VERSION 5.7 ;
  NOWIREEXTENSIONATPIN ON ;
  DIVIDERCHAR "/" ;
  BUSBITCHARS "[]" ;
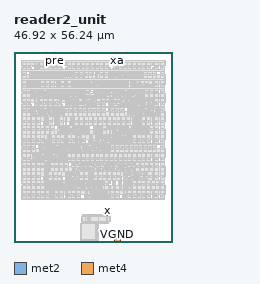
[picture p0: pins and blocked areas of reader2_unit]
MACRO reader2_unit
  CLASS BLOCK ;
  FOREIGN reader2_unit ;
  ORIGIN 0.000 0.000 ;
  SIZE 46.920 BY 56.240 ;
  PIN x
    DIRECTION INPUT ;
    USE SIGNAL ;
    ANTENNAGATEAREA 17.447500 ;
    ANTENNADIFFAREA 0.700000 ;
    PORT
      LAYER met2 ;
        RECT 27.690 9.000 27.970 9.400 ;
    END
  END x
  PIN VPWR
    DIRECTION INOUT ;
    USE POWER ;
    PORT
      LAYER met4 ;
        RECT 26.500 7.715 27.550 8.715 ;
    END
  END VPWR
  PIN VGND
    DIRECTION INOUT ;
    USE GROUND ;
    PORT
      LAYER met4 ;
        RECT 29.800 0.135 31.400 1.135 ;
    END
  END VGND
  PIN en
    DIRECTION INPUT ;
    USE SIGNAL ;
    ANTENNAGATEAREA 0.247500 ;
    PORT
      LAYER met2 ;
        RECT 9.290 55.960 9.570 56.240 ;
    END
  END en
  PIN pre
    DIRECTION INPUT ;
    USE SIGNAL ;
    ANTENNAGATEAREA 0.495000 ;
    PORT
      LAYER met2 ;
        RECT 12.050 55.960 12.330 56.240 ;
    END
  END pre
  PIN src[0]
    DIRECTION INPUT ;
    USE SIGNAL ;
    ANTENNAGATEAREA 1.615500 ;
    PORT
      LAYER met2 ;
        RECT 14.810 55.960 15.090 56.240 ;
    END
  END src[0]
  PIN src[1]
    DIRECTION INPUT ;
    USE SIGNAL ;
    ANTENNAGATEAREA 1.984500 ;
    PORT
      LAYER met2 ;
        RECT 17.570 55.960 17.850 56.240 ;
    END
  END src[1]
  PIN xa
    DIRECTION OUTPUT ;
    USE SIGNAL ;
    ANTENNADIFFAREA 0.445500 ;
    PORT
      LAYER met2 ;
        RECT 30.450 55.960 30.730 56.240 ;
    END
  END xa
  PIN xb
    DIRECTION OUTPUT ;
    USE SIGNAL ;
    ANTENNADIFFAREA 0.445500 ;
    PORT
      LAYER met2 ;
        RECT 33.210 55.960 33.490 56.240 ;
    END
  END xb
  OBS
      LAYER nwell ;
        RECT 2.110 52.105 44.810 53.710 ;
      LAYER pwell ;
        RECT 2.305 50.905 3.675 51.715 ;
        RECT 3.685 50.905 5.055 51.715 ;
        RECT 5.995 50.905 7.345 51.815 ;
        RECT 7.365 50.905 8.735 51.715 ;
        RECT 8.745 50.905 10.115 51.715 ;
        RECT 10.125 50.905 11.495 51.715 ;
        RECT 11.505 50.905 12.875 51.715 ;
        RECT 12.885 50.905 14.255 51.715 ;
        RECT 15.195 50.990 15.625 51.775 ;
        RECT 15.645 50.905 17.015 51.715 ;
        RECT 17.025 50.905 18.395 51.715 ;
        RECT 18.405 50.905 19.775 51.715 ;
        RECT 19.785 50.905 21.155 51.715 ;
        RECT 21.165 50.905 22.535 51.715 ;
        RECT 22.545 50.905 23.915 51.715 ;
        RECT 23.925 50.905 25.295 51.715 ;
        RECT 25.305 50.905 26.675 51.715 ;
        RECT 26.685 50.905 28.055 51.715 ;
        RECT 28.075 50.990 28.505 51.775 ;
        RECT 30.825 50.905 32.195 51.715 ;
        RECT 32.205 50.905 33.575 51.715 ;
        RECT 33.585 50.905 34.955 51.715 ;
        RECT 34.965 50.905 36.335 51.715 ;
        RECT 36.345 50.905 37.715 51.715 ;
        RECT 37.725 50.905 39.095 51.715 ;
        RECT 39.105 50.905 40.475 51.715 ;
        RECT 40.955 50.990 41.385 51.775 ;
        RECT 41.405 50.905 42.775 51.715 ;
        RECT 43.245 50.905 44.615 51.715 ;
        RECT 2.445 50.695 2.615 50.905 ;
        RECT 3.825 50.715 3.995 50.905 ;
        RECT 4.745 50.695 4.915 50.885 ;
        RECT 5.215 50.750 5.375 50.860 ;
        RECT 7.045 50.715 7.215 50.905 ;
        RECT 7.505 50.715 7.675 50.905 ;
        RECT 8.885 50.715 9.055 50.905 ;
        RECT 10.265 50.715 10.435 50.905 ;
        RECT 11.645 50.715 11.815 50.905 ;
        RECT 13.025 50.715 13.195 50.905 ;
        RECT 14.410 50.695 14.580 50.885 ;
        RECT 15.785 50.715 15.955 50.905 ;
        RECT 17.165 50.715 17.335 50.905 ;
        RECT 18.085 50.695 18.255 50.885 ;
        RECT 18.545 50.715 18.715 50.905 ;
        RECT 19.465 50.695 19.635 50.885 ;
        RECT 19.925 50.715 20.095 50.905 ;
        RECT 20.845 50.695 21.015 50.885 ;
        RECT 21.305 50.715 21.475 50.905 ;
        RECT 22.225 50.695 22.395 50.885 ;
        RECT 22.685 50.715 22.855 50.905 ;
        RECT 23.600 50.745 23.720 50.855 ;
        RECT 24.065 50.715 24.235 50.905 ;
        RECT 25.445 50.695 25.615 50.905 ;
        RECT 26.825 50.695 26.995 50.905 ;
        RECT 28.665 50.695 28.835 50.885 ;
        RECT 29.585 50.715 29.755 50.885 ;
        RECT 30.965 50.715 31.135 50.905 ;
        RECT 32.345 50.715 32.515 50.905 ;
        RECT 33.725 50.715 33.895 50.905 ;
        RECT 35.105 50.715 35.275 50.905 ;
        RECT 36.485 50.715 36.655 50.905 ;
        RECT 37.865 50.715 38.035 50.905 ;
        RECT 38.325 50.695 38.495 50.885 ;
        RECT 39.245 50.715 39.415 50.905 ;
        RECT 39.705 50.695 39.875 50.885 ;
        RECT 40.620 50.745 40.740 50.855 ;
        RECT 41.085 50.695 41.255 50.885 ;
        RECT 41.545 50.715 41.715 50.905 ;
        RECT 42.475 50.740 42.635 50.850 ;
        RECT 42.920 50.745 43.040 50.855 ;
        RECT 44.305 50.695 44.475 50.905 ;
        RECT 2.305 49.885 3.675 50.695 ;
        RECT 4.605 50.015 14.215 50.695 ;
        RECT 9.115 49.795 10.045 50.015 ;
        RECT 12.875 49.785 14.215 50.015 ;
        RECT 14.265 49.785 17.920 50.695 ;
        RECT 17.945 49.885 19.315 50.695 ;
        RECT 19.325 49.885 20.695 50.695 ;
        RECT 20.705 49.885 22.075 50.695 ;
        RECT 22.085 49.885 23.455 50.695 ;
        RECT 25.305 49.885 26.675 50.695 ;
        RECT 26.685 49.885 28.055 50.695 ;
        RECT 28.075 49.825 28.505 50.610 ;
        RECT 28.525 50.015 38.135 50.695 ;
        RECT 33.035 49.795 33.965 50.015 ;
        RECT 36.795 49.785 38.135 50.015 ;
        RECT 38.185 49.885 39.555 50.695 ;
        RECT 39.565 49.885 40.935 50.695 ;
        RECT 40.945 49.885 42.315 50.695 ;
        RECT 43.245 49.885 44.615 50.695 ;
      LAYER nwell ;
        RECT 2.110 46.665 44.810 49.495 ;
      LAYER pwell ;
        RECT 2.305 45.465 3.675 46.275 ;
        RECT 3.695 45.465 5.045 46.375 ;
        RECT 5.075 45.465 6.425 46.375 ;
        RECT 6.455 45.465 7.805 46.375 ;
        RECT 7.825 45.465 9.195 46.275 ;
        RECT 9.205 45.465 10.575 46.275 ;
        RECT 10.585 45.465 11.955 46.275 ;
        RECT 12.435 45.465 13.785 46.375 ;
        RECT 13.805 45.465 15.175 46.275 ;
        RECT 15.195 45.550 15.625 46.335 ;
        RECT 15.645 45.465 17.015 46.275 ;
        RECT 17.025 45.465 22.845 46.375 ;
        RECT 27.515 46.145 28.445 46.365 ;
        RECT 31.275 46.145 32.615 46.375 ;
        RECT 23.005 45.465 32.615 46.145 ;
        RECT 32.675 45.465 34.025 46.375 ;
        RECT 34.515 45.465 35.865 46.375 ;
        RECT 35.895 45.465 37.245 46.375 ;
        RECT 37.265 45.465 38.635 46.275 ;
        RECT 38.645 45.465 40.015 46.275 ;
        RECT 40.955 45.550 41.385 46.335 ;
        RECT 41.405 45.465 42.775 46.275 ;
        RECT 43.245 45.465 44.615 46.275 ;
        RECT 2.445 45.255 2.615 45.465 ;
        RECT 3.825 45.255 3.995 45.445 ;
        RECT 4.745 45.275 4.915 45.465 ;
        RECT 5.205 45.255 5.375 45.445 ;
        RECT 6.125 45.275 6.295 45.465 ;
        RECT 7.505 45.275 7.675 45.465 ;
        RECT 7.965 45.275 8.135 45.465 ;
        RECT 9.345 45.275 9.515 45.465 ;
        RECT 10.725 45.275 10.895 45.465 ;
        RECT 12.100 45.305 12.220 45.415 ;
        RECT 12.565 45.275 12.735 45.465 ;
        RECT 13.945 45.275 14.115 45.465 ;
        RECT 15.785 45.275 15.955 45.465 ;
        RECT 17.165 45.275 17.335 45.465 ;
        RECT 17.625 45.255 17.795 45.445 ;
        RECT 18.090 45.255 18.260 45.445 ;
        RECT 21.305 45.255 21.475 45.445 ;
        RECT 22.695 45.300 22.855 45.410 ;
        RECT 23.145 45.275 23.315 45.465 ;
        RECT 23.580 45.255 23.750 45.445 ;
        RECT 27.740 45.305 27.860 45.415 ;
        RECT 28.660 45.305 28.780 45.415 ;
        RECT 29.125 45.255 29.295 45.445 ;
        RECT 33.725 45.275 33.895 45.465 ;
        RECT 34.180 45.305 34.300 45.415 ;
        RECT 34.645 45.275 34.815 45.465 ;
        RECT 36.025 45.275 36.195 45.465 ;
        RECT 37.405 45.275 37.575 45.465 ;
        RECT 38.785 45.255 38.955 45.465 ;
        RECT 40.165 45.255 40.335 45.445 ;
        RECT 41.545 45.255 41.715 45.465 ;
        RECT 42.920 45.305 43.040 45.415 ;
        RECT 44.305 45.255 44.475 45.465 ;
        RECT 2.305 44.445 3.675 45.255 ;
        RECT 3.685 44.445 5.055 45.255 ;
        RECT 5.065 44.575 14.675 45.255 ;
        RECT 16.095 45.225 17.935 45.255 ;
        RECT 9.575 44.355 10.505 44.575 ;
        RECT 13.335 44.345 14.675 44.575 ;
        RECT 14.770 44.575 17.935 45.225 ;
        RECT 18.090 45.025 21.145 45.255 ;
        RECT 14.770 44.545 17.450 44.575 ;
        RECT 16.095 44.345 17.450 44.545 ;
        RECT 17.945 44.345 21.145 45.025 ;
        RECT 21.165 44.445 22.535 45.255 ;
        RECT 23.520 44.345 27.595 45.255 ;
        RECT 28.075 44.385 28.505 45.170 ;
        RECT 28.985 44.575 38.595 45.255 ;
        RECT 33.495 44.355 34.425 44.575 ;
        RECT 37.255 44.345 38.595 44.575 ;
        RECT 38.645 44.445 40.015 45.255 ;
        RECT 40.025 44.445 41.395 45.255 ;
        RECT 41.405 44.445 42.775 45.255 ;
        RECT 43.245 44.445 44.615 45.255 ;
      LAYER nwell ;
        RECT 2.110 41.225 44.810 44.055 ;
      LAYER pwell ;
        RECT 2.305 40.025 3.675 40.835 ;
        RECT 3.685 40.025 5.055 40.835 ;
        RECT 5.995 40.025 7.345 40.935 ;
        RECT 7.365 40.025 8.735 40.835 ;
        RECT 8.745 40.025 10.115 40.835 ;
        RECT 10.125 40.025 11.495 40.835 ;
        RECT 11.505 40.025 12.875 40.835 ;
        RECT 12.885 40.025 14.255 40.835 ;
        RECT 15.195 40.110 15.625 40.895 ;
        RECT 17.015 40.735 18.370 40.935 ;
        RECT 15.690 40.705 18.370 40.735 ;
        RECT 15.690 40.055 18.855 40.705 ;
        RECT 17.015 40.025 18.855 40.055 ;
        RECT 18.865 40.025 20.235 40.835 ;
        RECT 20.300 40.025 24.375 40.935 ;
        RECT 24.385 40.025 25.755 40.835 ;
        RECT 25.765 40.025 27.135 40.835 ;
        RECT 28.075 40.025 29.425 40.935 ;
        RECT 29.445 40.025 30.815 40.835 ;
        RECT 31.325 40.705 32.665 40.935 ;
        RECT 35.495 40.705 36.425 40.925 ;
        RECT 31.325 40.025 40.935 40.705 ;
        RECT 40.955 40.110 41.385 40.895 ;
        RECT 41.405 40.025 42.775 40.835 ;
        RECT 43.245 40.025 44.615 40.835 ;
        RECT 2.445 39.815 2.615 40.025 ;
        RECT 3.825 39.815 3.995 40.025 ;
        RECT 5.205 39.815 5.375 40.005 ;
        RECT 7.045 39.835 7.215 40.025 ;
        RECT 7.505 39.835 7.675 40.025 ;
        RECT 8.885 39.835 9.055 40.025 ;
        RECT 10.265 39.835 10.435 40.025 ;
        RECT 11.645 39.835 11.815 40.025 ;
        RECT 13.025 39.835 13.195 40.025 ;
        RECT 14.415 39.870 14.575 39.980 ;
        RECT 14.865 39.815 15.035 40.005 ;
        RECT 16.245 39.815 16.415 40.005 ;
        RECT 17.625 39.815 17.795 40.005 ;
        RECT 18.545 39.835 18.715 40.025 ;
        RECT 19.005 39.815 19.175 40.025 ;
        RECT 20.360 40.005 20.530 40.025 ;
        RECT 20.360 39.835 20.555 40.005 ;
        RECT 20.385 39.815 20.555 39.835 ;
        RECT 21.765 39.815 21.935 40.005 ;
        RECT 23.145 39.815 23.315 40.005 ;
        RECT 24.525 39.815 24.695 40.025 ;
        RECT 25.905 39.815 26.075 40.025 ;
        RECT 27.295 39.860 27.455 39.980 ;
        RECT 28.205 39.835 28.375 40.025 ;
        RECT 28.665 39.815 28.835 40.005 ;
        RECT 29.585 39.835 29.755 40.025 ;
        RECT 30.045 39.815 30.215 40.005 ;
        RECT 30.960 39.865 31.080 39.975 ;
        RECT 31.425 39.815 31.595 40.005 ;
        RECT 32.815 39.860 32.975 39.970 ;
        RECT 40.625 39.835 40.795 40.025 ;
        RECT 41.545 39.835 41.715 40.025 ;
        RECT 42.925 39.975 43.095 40.005 ;
        RECT 42.920 39.865 43.095 39.975 ;
        RECT 42.925 39.815 43.095 39.865 ;
        RECT 44.305 39.815 44.475 40.025 ;
        RECT 2.305 39.005 3.675 39.815 ;
        RECT 3.685 39.005 5.055 39.815 ;
        RECT 5.065 39.135 14.675 39.815 ;
        RECT 9.575 38.915 10.505 39.135 ;
        RECT 13.335 38.905 14.675 39.135 ;
        RECT 14.725 39.005 16.095 39.815 ;
        RECT 16.105 39.005 17.475 39.815 ;
        RECT 17.485 39.005 18.855 39.815 ;
        RECT 18.865 39.005 20.235 39.815 ;
        RECT 20.245 39.005 21.615 39.815 ;
        RECT 21.625 39.005 22.995 39.815 ;
        RECT 23.005 39.005 24.375 39.815 ;
        RECT 24.385 39.005 25.755 39.815 ;
        RECT 25.765 39.005 27.135 39.815 ;
        RECT 28.075 38.945 28.505 39.730 ;
        RECT 28.525 39.005 29.895 39.815 ;
        RECT 29.905 39.005 31.275 39.815 ;
        RECT 31.285 39.005 32.655 39.815 ;
        RECT 33.625 39.135 43.235 39.815 ;
        RECT 33.625 38.905 34.965 39.135 ;
        RECT 37.795 38.915 38.725 39.135 ;
        RECT 43.245 39.005 44.615 39.815 ;
      LAYER nwell ;
        RECT 2.110 35.785 44.810 38.615 ;
      LAYER pwell ;
        RECT 2.305 34.585 3.675 35.395 ;
        RECT 3.685 34.585 5.055 35.395 ;
        RECT 5.065 34.585 6.435 35.395 ;
        RECT 6.445 34.585 7.815 35.395 ;
        RECT 8.755 34.585 10.105 35.495 ;
        RECT 10.125 34.585 11.495 35.395 ;
        RECT 11.975 34.585 13.325 35.495 ;
        RECT 13.345 34.585 14.715 35.395 ;
        RECT 15.195 34.670 15.625 35.455 ;
        RECT 16.575 34.585 17.925 35.495 ;
        RECT 17.945 34.585 19.315 35.395 ;
        RECT 19.325 34.585 20.695 35.395 ;
        RECT 20.705 34.585 22.075 35.395 ;
        RECT 22.085 34.585 23.455 35.395 ;
        RECT 23.465 34.585 24.835 35.395 ;
        RECT 24.845 34.585 26.215 35.395 ;
        RECT 26.225 34.585 27.595 35.395 ;
        RECT 27.605 34.585 28.975 35.395 ;
        RECT 28.985 34.585 30.355 35.395 ;
        RECT 30.365 34.585 31.735 35.395 ;
        RECT 31.745 34.585 33.115 35.395 ;
        RECT 33.125 34.585 34.495 35.395 ;
        RECT 34.975 34.585 36.325 35.495 ;
        RECT 36.355 34.585 37.705 35.495 ;
        RECT 37.725 34.585 39.095 35.395 ;
        RECT 39.105 34.585 40.475 35.395 ;
        RECT 40.955 34.670 41.385 35.455 ;
        RECT 41.405 34.585 42.775 35.395 ;
        RECT 43.245 34.585 44.615 35.395 ;
        RECT 2.445 34.375 2.615 34.585 ;
        RECT 3.825 34.375 3.995 34.585 ;
        RECT 5.205 34.375 5.375 34.585 ;
        RECT 6.585 34.375 6.755 34.585 ;
        RECT 7.965 34.375 8.135 34.565 ;
        RECT 9.345 34.375 9.515 34.565 ;
        RECT 9.805 34.395 9.975 34.585 ;
        RECT 10.265 34.395 10.435 34.585 ;
        RECT 10.725 34.375 10.895 34.565 ;
        RECT 11.640 34.425 11.760 34.535 ;
        RECT 12.105 34.395 12.275 34.585 ;
        RECT 13.025 34.375 13.195 34.565 ;
        RECT 13.485 34.395 13.655 34.585 ;
        RECT 14.860 34.425 14.980 34.535 ;
        RECT 15.795 34.430 15.955 34.540 ;
        RECT 17.625 34.395 17.795 34.585 ;
        RECT 18.085 34.395 18.255 34.585 ;
        RECT 19.465 34.395 19.635 34.585 ;
        RECT 20.845 34.395 21.015 34.585 ;
        RECT 22.225 34.395 22.395 34.585 ;
        RECT 22.695 34.420 22.855 34.530 ;
        RECT 23.605 34.375 23.775 34.585 ;
        RECT 24.985 34.395 25.155 34.585 ;
        RECT 25.905 34.375 26.075 34.565 ;
        RECT 26.365 34.375 26.535 34.585 ;
        RECT 27.745 34.535 27.915 34.585 ;
        RECT 27.740 34.425 27.915 34.535 ;
        RECT 28.660 34.425 28.780 34.535 ;
        RECT 27.745 34.395 27.915 34.425 ;
        RECT 29.125 34.375 29.295 34.585 ;
        RECT 30.505 34.375 30.675 34.585 ;
        RECT 31.885 34.395 32.055 34.585 ;
        RECT 33.265 34.395 33.435 34.585 ;
        RECT 34.640 34.425 34.760 34.535 ;
        RECT 35.105 34.395 35.275 34.585 ;
        RECT 36.485 34.395 36.655 34.585 ;
        RECT 37.865 34.395 38.035 34.585 ;
        RECT 39.245 34.395 39.415 34.585 ;
        RECT 40.165 34.375 40.335 34.565 ;
        RECT 40.620 34.425 40.740 34.535 ;
        RECT 41.545 34.375 41.715 34.585 ;
        RECT 42.920 34.425 43.040 34.535 ;
        RECT 44.305 34.375 44.475 34.585 ;
        RECT 2.305 33.565 3.675 34.375 ;
        RECT 3.685 33.565 5.055 34.375 ;
        RECT 5.065 33.565 6.435 34.375 ;
        RECT 6.445 33.565 7.815 34.375 ;
        RECT 7.825 33.565 9.195 34.375 ;
        RECT 9.205 33.565 10.575 34.375 ;
        RECT 10.585 33.565 11.955 34.375 ;
        RECT 12.885 33.695 22.495 34.375 ;
        RECT 17.395 33.475 18.325 33.695 ;
        RECT 21.155 33.465 22.495 33.695 ;
        RECT 23.475 33.465 24.825 34.375 ;
        RECT 24.855 33.465 26.205 34.375 ;
        RECT 26.225 33.565 27.595 34.375 ;
        RECT 28.075 33.505 28.505 34.290 ;
        RECT 28.995 33.465 30.345 34.375 ;
        RECT 30.365 33.695 39.975 34.375 ;
        RECT 34.875 33.475 35.805 33.695 ;
        RECT 38.635 33.465 39.975 33.695 ;
        RECT 40.025 33.565 41.395 34.375 ;
        RECT 41.405 33.565 42.775 34.375 ;
        RECT 43.245 33.565 44.615 34.375 ;
      LAYER nwell ;
        RECT 2.110 30.345 44.810 33.175 ;
      LAYER pwell ;
        RECT 2.305 29.145 3.675 29.955 ;
        RECT 3.685 29.145 5.055 29.955 ;
        RECT 5.065 29.145 6.435 29.955 ;
        RECT 6.445 29.145 7.815 29.955 ;
        RECT 7.825 29.145 9.195 29.955 ;
        RECT 9.675 29.145 11.025 30.055 ;
        RECT 11.045 29.145 12.415 29.955 ;
        RECT 12.425 29.145 13.795 29.955 ;
        RECT 13.805 29.145 15.175 29.955 ;
        RECT 15.195 29.230 15.625 30.015 ;
        RECT 15.645 29.145 17.015 29.955 ;
        RECT 17.025 29.145 18.395 29.955 ;
        RECT 18.415 29.145 19.765 30.055 ;
        RECT 19.785 29.145 21.155 29.955 ;
        RECT 22.095 29.145 23.445 30.055 ;
        RECT 28.435 29.825 29.365 30.045 ;
        RECT 32.195 29.825 33.535 30.055 ;
        RECT 23.925 29.145 33.535 29.825 ;
        RECT 33.595 29.145 34.945 30.055 ;
        RECT 34.965 29.145 36.335 29.955 ;
        RECT 36.345 29.145 37.715 29.955 ;
        RECT 37.725 29.145 39.095 29.955 ;
        RECT 39.105 29.145 40.475 29.955 ;
        RECT 40.955 29.230 41.385 30.015 ;
        RECT 41.405 29.145 42.775 29.955 ;
        RECT 43.245 29.145 44.615 29.955 ;
        RECT 2.445 28.935 2.615 29.145 ;
        RECT 3.825 28.935 3.995 29.145 ;
        RECT 5.205 28.935 5.375 29.145 ;
        RECT 6.585 28.955 6.755 29.145 ;
        RECT 7.965 28.955 8.135 29.145 ;
        RECT 8.425 28.935 8.595 29.125 ;
        RECT 8.885 28.935 9.055 29.125 ;
        RECT 9.340 28.985 9.460 29.095 ;
        RECT 10.725 28.955 10.895 29.145 ;
        RECT 11.185 28.955 11.355 29.145 ;
        RECT 12.565 28.955 12.735 29.145 ;
        RECT 13.945 28.955 14.115 29.145 ;
        RECT 15.785 28.955 15.955 29.145 ;
        RECT 17.165 28.955 17.335 29.145 ;
        RECT 18.545 28.935 18.715 29.125 ;
        RECT 19.465 28.955 19.635 29.145 ;
        RECT 19.925 28.955 20.095 29.145 ;
        RECT 21.315 28.990 21.475 29.100 ;
        RECT 23.145 28.955 23.315 29.145 ;
        RECT 23.600 28.985 23.720 29.095 ;
        RECT 24.065 28.955 24.235 29.145 ;
        RECT 28.665 28.935 28.835 29.125 ;
        RECT 30.045 28.935 30.215 29.125 ;
        RECT 31.425 28.935 31.595 29.125 ;
        RECT 32.805 28.935 32.975 29.125 ;
        RECT 34.185 28.935 34.355 29.125 ;
        RECT 34.645 28.955 34.815 29.145 ;
        RECT 35.105 28.955 35.275 29.145 ;
        RECT 35.565 28.935 35.735 29.125 ;
        RECT 36.485 28.955 36.655 29.145 ;
        RECT 36.945 28.935 37.115 29.125 ;
        RECT 37.865 28.955 38.035 29.145 ;
        RECT 38.325 28.935 38.495 29.125 ;
        RECT 39.245 28.955 39.415 29.145 ;
        RECT 39.705 28.935 39.875 29.125 ;
        RECT 40.620 28.985 40.740 29.095 ;
        RECT 41.085 28.935 41.255 29.125 ;
        RECT 41.545 28.955 41.715 29.145 ;
        RECT 42.475 28.980 42.635 29.090 ;
        RECT 42.920 28.985 43.040 29.095 ;
        RECT 44.305 28.935 44.475 29.145 ;
        RECT 2.305 28.125 3.675 28.935 ;
        RECT 3.685 28.125 5.055 28.935 ;
        RECT 5.065 28.125 6.435 28.935 ;
        RECT 7.375 28.025 8.725 28.935 ;
        RECT 8.745 28.255 18.355 28.935 ;
        RECT 18.405 28.255 28.015 28.935 ;
        RECT 13.255 28.035 14.185 28.255 ;
        RECT 17.015 28.025 18.355 28.255 ;
        RECT 22.915 28.035 23.845 28.255 ;
        RECT 26.675 28.025 28.015 28.255 ;
        RECT 28.075 28.065 28.505 28.850 ;
        RECT 28.525 28.125 29.895 28.935 ;
        RECT 29.905 28.125 31.275 28.935 ;
        RECT 31.285 28.125 32.655 28.935 ;
        RECT 32.665 28.125 34.035 28.935 ;
        RECT 34.045 28.125 35.415 28.935 ;
        RECT 35.425 28.125 36.795 28.935 ;
        RECT 36.805 28.125 38.175 28.935 ;
        RECT 38.185 28.125 39.555 28.935 ;
        RECT 39.565 28.125 40.935 28.935 ;
        RECT 40.945 28.125 42.315 28.935 ;
        RECT 43.245 28.125 44.615 28.935 ;
      LAYER nwell ;
        RECT 2.110 24.905 44.810 27.735 ;
      LAYER pwell ;
        RECT 2.305 23.705 3.675 24.515 ;
        RECT 3.685 23.705 5.055 24.515 ;
        RECT 10.035 24.385 10.965 24.605 ;
        RECT 13.795 24.385 15.135 24.615 ;
        RECT 5.525 23.705 15.135 24.385 ;
        RECT 15.195 23.790 15.625 24.575 ;
        RECT 15.645 23.705 17.015 24.515 ;
        RECT 17.025 23.705 18.395 24.515 ;
        RECT 18.405 23.705 19.775 24.515 ;
        RECT 19.785 23.705 21.155 24.515 ;
        RECT 21.165 23.705 22.535 24.515 ;
        RECT 22.545 23.705 23.915 24.515 ;
        RECT 23.925 23.705 25.295 24.515 ;
        RECT 25.305 23.705 26.675 24.515 ;
        RECT 26.685 23.705 28.055 24.515 ;
        RECT 28.065 23.705 29.435 24.515 ;
        RECT 29.445 23.705 30.815 24.515 ;
        RECT 30.825 23.705 32.195 24.515 ;
        RECT 32.205 23.705 33.575 24.515 ;
        RECT 33.585 23.705 34.955 24.515 ;
        RECT 34.965 23.705 36.335 24.515 ;
        RECT 36.345 23.705 37.715 24.515 ;
        RECT 37.725 23.705 39.095 24.515 ;
        RECT 39.105 23.705 40.475 24.515 ;
        RECT 40.955 23.790 41.385 24.575 ;
        RECT 41.405 23.705 42.775 24.515 ;
        RECT 43.245 23.705 44.615 24.515 ;
        RECT 2.445 23.495 2.615 23.705 ;
        RECT 3.825 23.495 3.995 23.705 ;
        RECT 5.205 23.655 5.375 23.685 ;
        RECT 5.200 23.545 5.375 23.655 ;
        RECT 5.205 23.495 5.375 23.545 ;
        RECT 5.665 23.515 5.835 23.705 ;
        RECT 6.585 23.495 6.755 23.685 ;
        RECT 7.965 23.495 8.135 23.685 ;
        RECT 10.265 23.495 10.435 23.685 ;
        RECT 10.725 23.495 10.895 23.685 ;
        RECT 12.105 23.495 12.275 23.685 ;
        RECT 13.485 23.495 13.655 23.685 ;
        RECT 14.865 23.495 15.035 23.685 ;
        RECT 15.785 23.515 15.955 23.705 ;
        RECT 16.255 23.540 16.415 23.650 ;
        RECT 17.165 23.495 17.335 23.705 ;
        RECT 18.545 23.515 18.715 23.705 ;
        RECT 19.925 23.515 20.095 23.705 ;
        RECT 20.845 23.495 21.015 23.685 ;
        RECT 21.305 23.515 21.475 23.705 ;
        RECT 22.685 23.515 22.855 23.705 ;
        RECT 24.065 23.515 24.235 23.705 ;
        RECT 24.525 23.495 24.695 23.685 ;
        RECT 25.445 23.515 25.615 23.705 ;
        RECT 26.825 23.515 26.995 23.705 ;
        RECT 28.205 23.515 28.375 23.705 ;
        RECT 28.665 23.495 28.835 23.685 ;
        RECT 29.585 23.515 29.755 23.705 ;
        RECT 30.965 23.515 31.135 23.705 ;
        RECT 32.345 23.515 32.515 23.705 ;
        RECT 33.725 23.515 33.895 23.705 ;
        RECT 35.105 23.515 35.275 23.705 ;
        RECT 35.565 23.495 35.735 23.685 ;
        RECT 36.025 23.495 36.195 23.685 ;
        RECT 36.485 23.515 36.655 23.705 ;
        RECT 37.405 23.495 37.575 23.685 ;
        RECT 37.865 23.515 38.035 23.705 ;
        RECT 38.785 23.495 38.955 23.685 ;
        RECT 39.245 23.515 39.415 23.705 ;
        RECT 40.165 23.495 40.335 23.685 ;
        RECT 40.620 23.545 40.740 23.655 ;
        RECT 41.545 23.495 41.715 23.705 ;
        RECT 42.920 23.545 43.040 23.655 ;
        RECT 44.305 23.495 44.475 23.705 ;
        RECT 2.305 22.685 3.675 23.495 ;
        RECT 3.685 22.685 5.055 23.495 ;
        RECT 5.065 22.685 6.435 23.495 ;
        RECT 6.445 22.685 7.815 23.495 ;
        RECT 7.825 22.685 9.195 23.495 ;
        RECT 9.215 22.585 10.565 23.495 ;
        RECT 10.585 22.685 11.955 23.495 ;
        RECT 11.965 22.685 13.335 23.495 ;
        RECT 13.345 22.685 14.715 23.495 ;
        RECT 14.725 22.685 16.095 23.495 ;
        RECT 17.135 22.815 20.600 23.495 ;
        RECT 20.815 22.815 24.280 23.495 ;
        RECT 24.495 22.815 27.960 23.495 ;
        RECT 19.680 22.585 20.600 22.815 ;
        RECT 23.360 22.585 24.280 22.815 ;
        RECT 27.040 22.585 27.960 22.815 ;
        RECT 28.075 22.625 28.505 23.410 ;
        RECT 28.635 22.815 32.100 23.495 ;
        RECT 31.180 22.585 32.100 22.815 ;
        RECT 32.300 22.815 35.765 23.495 ;
        RECT 32.300 22.585 33.220 22.815 ;
        RECT 35.885 22.685 37.255 23.495 ;
        RECT 37.265 22.685 38.635 23.495 ;
        RECT 38.645 22.685 40.015 23.495 ;
        RECT 40.025 22.685 41.395 23.495 ;
        RECT 41.405 22.685 42.775 23.495 ;
        RECT 43.245 22.685 44.615 23.495 ;
      LAYER nwell ;
        RECT 2.110 19.465 44.810 22.295 ;
      LAYER pwell ;
        RECT 2.305 18.265 3.675 19.075 ;
        RECT 3.685 18.265 5.055 19.075 ;
        RECT 5.065 18.265 6.435 19.075 ;
        RECT 6.445 18.265 7.815 19.075 ;
        RECT 8.755 18.265 10.105 19.175 ;
        RECT 10.125 18.265 11.495 19.075 ;
        RECT 11.505 18.265 12.875 19.075 ;
        RECT 12.885 18.265 14.255 19.075 ;
        RECT 15.195 18.350 15.625 19.135 ;
        RECT 15.740 18.945 16.660 19.175 ;
        RECT 15.740 18.265 19.205 18.945 ;
        RECT 19.325 18.265 20.695 19.075 ;
        RECT 20.705 18.265 22.075 19.075 ;
        RECT 22.095 18.265 23.445 19.175 ;
        RECT 23.465 18.265 24.835 19.075 ;
        RECT 24.845 18.265 26.215 19.075 ;
        RECT 26.225 18.265 27.595 19.075 ;
        RECT 27.605 18.265 28.975 19.075 ;
        RECT 28.985 18.265 30.355 19.075 ;
        RECT 30.365 18.265 31.735 19.075 ;
        RECT 34.860 18.945 35.780 19.175 ;
        RECT 32.315 18.265 35.780 18.945 ;
        RECT 35.980 18.945 36.900 19.175 ;
        RECT 35.980 18.265 39.445 18.945 ;
        RECT 39.565 18.265 40.935 19.075 ;
        RECT 40.955 18.350 41.385 19.135 ;
        RECT 41.405 18.265 42.775 19.075 ;
        RECT 43.245 18.265 44.615 19.075 ;
        RECT 2.445 18.055 2.615 18.265 ;
        RECT 3.825 18.055 3.995 18.265 ;
        RECT 5.205 18.055 5.375 18.265 ;
        RECT 6.585 18.055 6.755 18.265 ;
        RECT 7.965 18.055 8.135 18.245 ;
        RECT 9.805 18.075 9.975 18.265 ;
        RECT 10.265 18.075 10.435 18.265 ;
        RECT 11.645 18.075 11.815 18.265 ;
        RECT 13.025 18.075 13.195 18.265 ;
        RECT 14.415 18.110 14.575 18.220 ;
        RECT 18.545 18.055 18.715 18.245 ;
        RECT 19.005 18.075 19.175 18.265 ;
        RECT 19.465 18.075 19.635 18.265 ;
        RECT 20.845 18.075 21.015 18.265 ;
        RECT 23.145 18.075 23.315 18.265 ;
        RECT 23.605 18.075 23.775 18.265 ;
        RECT 24.985 18.245 25.155 18.265 ;
        RECT 24.980 18.075 25.155 18.245 ;
        RECT 26.365 18.075 26.535 18.265 ;
        RECT 24.980 18.055 25.150 18.075 ;
        RECT 26.365 18.055 26.470 18.075 ;
        RECT 26.825 18.055 26.995 18.245 ;
        RECT 27.745 18.075 27.915 18.265 ;
        RECT 28.660 18.105 28.780 18.215 ;
        RECT 29.125 18.075 29.295 18.265 ;
        RECT 30.505 18.215 30.675 18.265 ;
        RECT 30.500 18.105 30.675 18.215 ;
        RECT 30.505 18.075 30.675 18.105 ;
        RECT 30.965 18.075 31.135 18.245 ;
        RECT 31.880 18.105 32.000 18.215 ;
        RECT 32.345 18.075 32.515 18.265 ;
        RECT 29.190 18.055 29.295 18.075 ;
        RECT 31.030 18.055 31.135 18.075 ;
        RECT 32.410 18.055 32.515 18.075 ;
        RECT 33.730 18.055 33.900 18.245 ;
        RECT 35.105 18.055 35.275 18.245 ;
        RECT 36.485 18.055 36.655 18.245 ;
        RECT 37.865 18.055 38.035 18.245 ;
        RECT 39.245 18.055 39.415 18.265 ;
        RECT 39.705 18.075 39.875 18.265 ;
        RECT 40.625 18.055 40.795 18.245 ;
        RECT 41.545 18.075 41.715 18.265 ;
        RECT 42.005 18.055 42.175 18.245 ;
        RECT 42.920 18.105 43.040 18.215 ;
        RECT 44.305 18.055 44.475 18.265 ;
        RECT 2.305 17.245 3.675 18.055 ;
        RECT 3.685 17.245 5.055 18.055 ;
        RECT 5.065 17.245 6.435 18.055 ;
        RECT 6.445 17.245 7.815 18.055 ;
        RECT 7.825 17.245 9.195 18.055 ;
        RECT 9.245 17.375 18.855 18.055 ;
        RECT 9.245 17.145 10.585 17.375 ;
        RECT 13.415 17.155 14.345 17.375 ;
        RECT 19.215 17.145 25.295 18.055 ;
        RECT 25.540 17.145 26.470 18.055 ;
        RECT 26.685 17.245 28.055 18.055 ;
        RECT 28.075 17.185 28.505 17.970 ;
        RECT 29.190 17.145 30.120 18.055 ;
        RECT 31.030 17.145 31.960 18.055 ;
        RECT 32.410 17.145 33.340 18.055 ;
        RECT 33.585 17.145 34.935 18.055 ;
        RECT 34.965 17.245 36.335 18.055 ;
        RECT 36.345 17.245 37.715 18.055 ;
        RECT 37.725 17.245 39.095 18.055 ;
        RECT 39.105 17.245 40.475 18.055 ;
        RECT 40.485 17.245 41.855 18.055 ;
        RECT 41.865 17.245 43.235 18.055 ;
        RECT 43.245 17.245 44.615 18.055 ;
      LAYER nwell ;
        RECT 2.110 14.025 44.810 16.855 ;
      LAYER pwell ;
        RECT 2.305 12.825 3.675 13.635 ;
        RECT 3.685 12.825 5.055 13.635 ;
        RECT 5.065 12.825 6.435 13.635 ;
        RECT 6.445 12.825 7.815 13.635 ;
        RECT 7.825 12.825 9.195 13.635 ;
        RECT 9.205 12.825 10.575 13.635 ;
        RECT 10.595 12.825 11.945 13.735 ;
        RECT 11.965 12.825 13.335 13.635 ;
        RECT 13.345 12.825 14.715 13.635 ;
        RECT 15.195 12.910 15.625 13.695 ;
        RECT 15.645 12.825 17.015 13.635 ;
        RECT 17.025 12.825 18.395 13.635 ;
        RECT 18.405 12.825 19.775 13.635 ;
        RECT 20.910 12.825 21.840 13.735 ;
        RECT 22.085 12.825 27.795 13.735 ;
        RECT 28.075 12.910 28.505 13.695 ;
        RECT 28.525 12.825 29.895 13.635 ;
        RECT 29.905 12.825 31.275 13.635 ;
        RECT 32.205 12.825 33.555 13.735 ;
        RECT 33.585 12.825 34.955 13.635 ;
        RECT 34.965 12.825 36.335 13.635 ;
        RECT 36.345 12.825 37.715 13.635 ;
        RECT 37.725 12.825 39.095 13.635 ;
        RECT 39.105 12.825 40.475 13.635 ;
        RECT 40.955 12.910 41.385 13.695 ;
        RECT 41.405 12.825 42.775 13.635 ;
        RECT 43.245 12.825 44.615 13.635 ;
        RECT 2.445 12.635 2.615 12.825 ;
        RECT 3.825 12.635 3.995 12.825 ;
        RECT 5.205 12.635 5.375 12.825 ;
        RECT 6.585 12.635 6.755 12.825 ;
        RECT 7.965 12.635 8.135 12.825 ;
        RECT 9.345 12.635 9.515 12.825 ;
        RECT 10.725 12.635 10.895 12.825 ;
        RECT 12.105 12.635 12.275 12.825 ;
        RECT 13.485 12.635 13.655 12.825 ;
        RECT 14.860 12.665 14.980 12.775 ;
        RECT 15.785 12.635 15.955 12.825 ;
        RECT 17.165 12.635 17.335 12.825 ;
        RECT 18.545 12.635 18.715 12.825 ;
        RECT 20.910 12.805 21.015 12.825 ;
        RECT 19.935 12.670 20.095 12.780 ;
        RECT 20.845 12.635 21.015 12.805 ;
        RECT 22.230 12.635 22.400 12.825 ;
        RECT 28.665 12.635 28.835 12.825 ;
        RECT 30.045 12.635 30.215 12.825 ;
        RECT 31.435 12.670 31.595 12.780 ;
        RECT 32.350 12.635 32.520 12.825 ;
        RECT 33.725 12.635 33.895 12.825 ;
        RECT 35.105 12.635 35.275 12.825 ;
        RECT 36.485 12.635 36.655 12.825 ;
        RECT 37.865 12.635 38.035 12.825 ;
        RECT 39.245 12.635 39.415 12.825 ;
        RECT 40.620 12.665 40.740 12.775 ;
        RECT 41.545 12.635 41.715 12.825 ;
        RECT 42.920 12.665 43.040 12.775 ;
        RECT 44.305 12.635 44.475 12.825 ;
      LAYER nwell ;
        RECT 19.940 6.100 28.600 7.460 ;
      LAYER pwell ;
        RECT 19.590 0.870 25.140 5.430 ;
      LAYER li1 ;
        RECT 2.300 53.435 44.620 53.605 ;
        RECT 2.385 52.345 3.595 53.435 ;
        RECT 3.765 52.345 4.975 53.435 ;
        RECT 2.385 51.635 2.905 52.175 ;
        RECT 3.075 51.805 3.595 52.345 ;
        RECT 3.765 51.635 4.285 52.175 ;
        RECT 4.455 51.805 4.975 52.345 ;
        RECT 6.125 52.295 6.335 53.435 ;
        RECT 6.505 52.285 6.835 53.265 ;
        RECT 7.005 52.295 7.235 53.435 ;
        RECT 7.445 52.345 8.655 53.435 ;
        RECT 8.825 52.345 10.035 53.435 ;
        RECT 10.205 52.345 11.415 53.435 ;
        RECT 11.585 52.345 12.795 53.435 ;
        RECT 12.965 52.345 14.175 53.435 ;
        RECT 2.385 50.885 3.595 51.635 ;
        RECT 3.765 50.885 4.975 51.635 ;
        RECT 6.125 50.885 6.335 51.705 ;
        RECT 6.505 51.685 6.755 52.285 ;
        RECT 6.925 51.875 7.255 52.125 ;
        RECT 6.505 51.055 6.835 51.685 ;
        RECT 7.005 50.885 7.235 51.705 ;
        RECT 7.445 51.635 7.965 52.175 ;
        RECT 8.135 51.805 8.655 52.345 ;
        RECT 8.825 51.635 9.345 52.175 ;
        RECT 9.515 51.805 10.035 52.345 ;
        RECT 10.205 51.635 10.725 52.175 ;
        RECT 10.895 51.805 11.415 52.345 ;
        RECT 11.585 51.635 12.105 52.175 ;
        RECT 12.275 51.805 12.795 52.345 ;
        RECT 12.965 51.635 13.485 52.175 ;
        RECT 13.655 51.805 14.175 52.345 ;
        RECT 15.265 52.270 15.555 53.435 ;
        RECT 15.725 52.345 16.935 53.435 ;
        RECT 17.105 52.345 18.315 53.435 ;
        RECT 18.485 52.345 19.695 53.435 ;
        RECT 19.865 52.345 21.075 53.435 ;
        RECT 21.245 52.345 22.455 53.435 ;
        RECT 22.625 52.345 23.835 53.435 ;
        RECT 24.005 52.345 25.215 53.435 ;
        RECT 25.385 52.345 26.595 53.435 ;
        RECT 26.765 52.345 27.975 53.435 ;
        RECT 15.725 51.635 16.245 52.175 ;
        RECT 16.415 51.805 16.935 52.345 ;
        RECT 17.105 51.635 17.625 52.175 ;
        RECT 17.795 51.805 18.315 52.345 ;
        RECT 18.485 51.635 19.005 52.175 ;
        RECT 19.175 51.805 19.695 52.345 ;
        RECT 19.865 51.635 20.385 52.175 ;
        RECT 20.555 51.805 21.075 52.345 ;
        RECT 21.245 51.635 21.765 52.175 ;
        RECT 21.935 51.805 22.455 52.345 ;
        RECT 22.625 51.635 23.145 52.175 ;
        RECT 23.315 51.805 23.835 52.345 ;
        RECT 24.005 51.635 24.525 52.175 ;
        RECT 24.695 51.805 25.215 52.345 ;
        RECT 25.385 51.635 25.905 52.175 ;
        RECT 26.075 51.805 26.595 52.345 ;
        RECT 26.765 51.635 27.285 52.175 ;
        RECT 27.455 51.805 27.975 52.345 ;
        RECT 28.145 52.270 28.435 53.435 ;
        RECT 29.715 52.710 30.045 53.435 ;
        RECT 7.445 50.885 8.655 51.635 ;
        RECT 8.825 50.885 10.035 51.635 ;
        RECT 10.205 50.885 11.415 51.635 ;
        RECT 11.585 50.885 12.795 51.635 ;
        RECT 12.965 50.885 14.175 51.635 ;
        RECT 15.265 50.885 15.555 51.610 ;
        RECT 15.725 50.885 16.935 51.635 ;
        RECT 17.105 50.885 18.315 51.635 ;
        RECT 18.485 50.885 19.695 51.635 ;
        RECT 19.865 50.885 21.075 51.635 ;
        RECT 21.245 50.885 22.455 51.635 ;
        RECT 22.625 50.885 23.835 51.635 ;
        RECT 24.005 50.885 25.215 51.635 ;
        RECT 25.385 50.885 26.595 51.635 ;
        RECT 26.765 50.885 27.975 51.635 ;
        RECT 28.145 50.885 28.435 51.610 ;
        RECT 29.525 51.055 30.045 52.540 ;
        RECT 30.215 51.715 30.735 53.265 ;
        RECT 30.905 52.345 32.115 53.435 ;
        RECT 32.285 52.345 33.495 53.435 ;
        RECT 33.665 52.345 34.875 53.435 ;
        RECT 35.045 52.345 36.255 53.435 ;
        RECT 36.425 52.345 37.635 53.435 ;
        RECT 37.805 52.345 39.015 53.435 ;
        RECT 39.185 52.345 40.395 53.435 ;
        RECT 30.905 51.635 31.425 52.175 ;
        RECT 31.595 51.805 32.115 52.345 ;
        RECT 32.285 51.635 32.805 52.175 ;
        RECT 32.975 51.805 33.495 52.345 ;
        RECT 33.665 51.635 34.185 52.175 ;
        RECT 34.355 51.805 34.875 52.345 ;
        RECT 35.045 51.635 35.565 52.175 ;
        RECT 35.735 51.805 36.255 52.345 ;
        RECT 36.425 51.635 36.945 52.175 ;
        RECT 37.115 51.805 37.635 52.345 ;
        RECT 37.805 51.635 38.325 52.175 ;
        RECT 38.495 51.805 39.015 52.345 ;
        RECT 39.185 51.635 39.705 52.175 ;
        RECT 39.875 51.805 40.395 52.345 ;
        RECT 41.025 52.270 41.315 53.435 ;
        RECT 41.485 52.345 42.695 53.435 ;
        RECT 41.485 51.635 42.005 52.175 ;
        RECT 42.175 51.805 42.695 52.345 ;
        RECT 43.325 52.345 44.535 53.435 ;
        RECT 43.325 51.805 43.845 52.345 ;
        RECT 44.015 51.635 44.535 52.175 ;
        RECT 30.215 50.885 30.555 51.545 ;
        RECT 30.905 50.885 32.115 51.635 ;
        RECT 32.285 50.885 33.495 51.635 ;
        RECT 33.665 50.885 34.875 51.635 ;
        RECT 35.045 50.885 36.255 51.635 ;
        RECT 36.425 50.885 37.635 51.635 ;
        RECT 37.805 50.885 39.015 51.635 ;
        RECT 39.185 50.885 40.395 51.635 ;
        RECT 41.025 50.885 41.315 51.610 ;
        RECT 41.485 50.885 42.695 51.635 ;
        RECT 43.325 50.885 44.535 51.635 ;
        RECT 2.300 50.715 44.620 50.885 ;
        RECT 2.385 49.965 3.595 50.715 ;
        RECT 4.690 50.165 4.945 50.455 ;
        RECT 5.115 50.335 5.445 50.715 ;
        RECT 4.690 49.995 5.440 50.165 ;
        RECT 2.385 49.425 2.905 49.965 ;
        RECT 3.075 49.255 3.595 49.795 ;
        RECT 2.385 48.165 3.595 49.255 ;
        RECT 4.690 49.175 5.040 49.825 ;
        RECT 5.210 49.005 5.440 49.995 ;
        RECT 4.690 48.835 5.440 49.005 ;
        RECT 4.690 48.335 4.945 48.835 ;
        RECT 5.115 48.165 5.445 48.665 ;
        RECT 5.615 48.335 5.785 50.455 ;
        RECT 6.145 50.355 6.475 50.715 ;
        RECT 6.645 50.325 7.140 50.495 ;
        RECT 7.345 50.325 8.200 50.495 ;
        RECT 6.015 49.135 6.475 50.185 ;
        RECT 5.955 48.350 6.280 49.135 ;
        RECT 6.645 48.965 6.815 50.325 ;
        RECT 6.985 49.415 7.335 50.035 ;
        RECT 7.505 49.815 7.860 50.035 ;
        RECT 7.505 49.225 7.675 49.815 ;
        RECT 8.030 49.615 8.200 50.325 ;
        RECT 9.075 50.255 9.405 50.715 ;
        RECT 9.615 50.355 9.965 50.525 ;
        RECT 8.405 49.785 9.195 50.035 ;
        RECT 9.615 49.965 9.875 50.355 ;
        RECT 10.185 50.265 11.135 50.545 ;
        RECT 11.305 50.275 11.495 50.715 ;
        RECT 11.665 50.335 12.735 50.505 ;
        RECT 9.365 49.615 9.535 49.795 ;
        RECT 6.645 48.795 7.040 48.965 ;
        RECT 7.210 48.835 7.675 49.225 ;
        RECT 7.845 49.445 9.535 49.615 ;
        RECT 6.870 48.665 7.040 48.795 ;
        RECT 7.845 48.665 8.015 49.445 ;
        RECT 9.705 49.275 9.875 49.965 ;
        RECT 8.375 49.105 9.875 49.275 ;
        RECT 10.065 49.305 10.275 50.095 ;
        RECT 10.445 49.475 10.795 50.095 ;
        RECT 10.965 49.485 11.135 50.265 ;
        RECT 11.665 50.105 11.835 50.335 ;
        RECT 11.305 49.935 11.835 50.105 ;
        RECT 11.305 49.655 11.525 49.935 ;
        RECT 12.005 49.765 12.245 50.165 ;
        RECT 10.965 49.315 11.370 49.485 ;
        RECT 11.705 49.395 12.245 49.765 ;
        RECT 12.415 49.980 12.735 50.335 ;
        RECT 12.980 50.255 13.285 50.715 ;
        RECT 13.455 50.005 13.705 50.535 ;
        RECT 12.415 49.805 12.740 49.980 ;
        RECT 12.415 49.505 13.330 49.805 ;
        RECT 12.590 49.475 13.330 49.505 ;
        RECT 10.065 49.145 10.740 49.305 ;
        RECT 11.200 49.225 11.370 49.315 ;
        RECT 10.065 49.135 11.030 49.145 ;
        RECT 9.705 48.965 9.875 49.105 ;
        RECT 6.450 48.165 6.700 48.625 ;
        RECT 6.870 48.335 7.120 48.665 ;
        RECT 7.335 48.335 8.015 48.665 ;
        RECT 8.185 48.765 9.260 48.935 ;
        RECT 9.705 48.795 10.265 48.965 ;
        RECT 10.570 48.845 11.030 49.135 ;
        RECT 11.200 49.055 12.420 49.225 ;
        RECT 8.185 48.425 8.355 48.765 ;
        RECT 8.590 48.165 8.920 48.595 ;
        RECT 9.090 48.425 9.260 48.765 ;
        RECT 9.555 48.165 9.925 48.625 ;
        RECT 10.095 48.335 10.265 48.795 ;
        RECT 11.200 48.675 11.370 49.055 ;
        RECT 12.590 48.885 12.760 49.475 ;
        RECT 13.500 49.355 13.705 50.005 ;
        RECT 13.875 49.960 14.125 50.715 ;
        RECT 14.355 50.375 14.690 50.545 ;
        RECT 14.355 49.975 14.970 50.375 ;
        RECT 15.650 50.335 15.985 50.715 ;
        RECT 16.575 50.275 16.810 50.715 ;
        RECT 16.980 50.185 17.310 50.545 ;
        RECT 17.480 50.355 17.810 50.715 ;
        RECT 15.140 49.975 16.410 50.165 ;
        RECT 16.980 50.015 17.800 50.185 ;
        RECT 14.345 49.475 14.620 49.805 ;
        RECT 10.500 48.335 11.370 48.675 ;
        RECT 11.960 48.715 12.760 48.885 ;
        RECT 11.540 48.165 11.790 48.625 ;
        RECT 11.960 48.425 12.130 48.715 ;
        RECT 12.310 48.165 12.640 48.545 ;
        RECT 12.980 48.165 13.285 49.305 ;
        RECT 13.455 48.475 13.705 49.355 ;
        RECT 13.875 48.165 14.125 49.305 ;
        RECT 14.790 49.290 14.970 49.975 ;
        RECT 15.140 49.475 15.500 49.805 ;
        RECT 15.790 49.695 16.080 49.805 ;
        RECT 15.785 49.525 16.080 49.695 ;
        RECT 15.790 49.475 16.080 49.525 ;
        RECT 16.250 49.475 16.585 49.805 ;
        RECT 16.755 49.475 17.435 49.805 ;
        RECT 16.755 49.290 16.925 49.475 ;
        RECT 14.350 49.035 16.925 49.290 ;
        RECT 14.350 48.335 14.615 49.035 ;
        RECT 14.785 48.165 15.115 48.865 ;
        RECT 15.285 48.335 15.955 49.035 ;
        RECT 17.605 48.895 17.800 50.015 ;
        RECT 18.025 49.965 19.235 50.715 ;
        RECT 19.405 49.965 20.615 50.715 ;
        RECT 20.785 49.965 21.995 50.715 ;
        RECT 22.165 49.965 23.375 50.715 ;
        RECT 18.025 49.425 18.545 49.965 ;
        RECT 18.715 49.255 19.235 49.795 ;
        RECT 19.405 49.425 19.925 49.965 ;
        RECT 20.095 49.255 20.615 49.795 ;
        RECT 20.785 49.425 21.305 49.965 ;
        RECT 21.475 49.255 21.995 49.795 ;
        RECT 22.165 49.425 22.685 49.965 ;
        RECT 22.855 49.255 23.375 49.795 ;
        RECT 16.460 48.165 16.890 48.865 ;
        RECT 17.070 48.725 17.800 48.895 ;
        RECT 17.070 48.335 17.260 48.725 ;
        RECT 17.430 48.165 17.760 48.545 ;
        RECT 18.025 48.165 19.235 49.255 ;
        RECT 19.405 48.165 20.615 49.255 ;
        RECT 20.785 48.165 21.995 49.255 ;
        RECT 22.165 48.165 23.375 49.255 ;
        RECT 24.005 49.060 24.525 50.545 ;
        RECT 24.695 50.055 25.035 50.715 ;
        RECT 25.385 49.965 26.595 50.715 ;
        RECT 26.765 49.965 27.975 50.715 ;
        RECT 28.145 49.990 28.435 50.715 ;
        RECT 28.610 50.165 28.865 50.455 ;
        RECT 29.035 50.335 29.365 50.715 ;
        RECT 28.610 49.995 29.360 50.165 ;
        RECT 24.195 48.165 24.525 48.890 ;
        RECT 24.695 48.335 25.215 49.885 ;
        RECT 25.385 49.425 25.905 49.965 ;
        RECT 26.075 49.255 26.595 49.795 ;
        RECT 26.765 49.425 27.285 49.965 ;
        RECT 27.455 49.255 27.975 49.795 ;
        RECT 25.385 48.165 26.595 49.255 ;
        RECT 26.765 48.165 27.975 49.255 ;
        RECT 28.145 48.165 28.435 49.330 ;
        RECT 28.610 49.175 28.960 49.825 ;
        RECT 29.130 49.005 29.360 49.995 ;
        RECT 28.610 48.835 29.360 49.005 ;
        RECT 28.610 48.335 28.865 48.835 ;
        RECT 29.035 48.165 29.365 48.665 ;
        RECT 29.535 48.335 29.705 50.455 ;
        RECT 30.065 50.355 30.395 50.715 ;
        RECT 30.565 50.325 31.060 50.495 ;
        RECT 31.265 50.325 32.120 50.495 ;
        RECT 29.935 49.135 30.395 50.185 ;
        RECT 29.875 48.350 30.200 49.135 ;
        RECT 30.565 48.965 30.735 50.325 ;
        RECT 30.905 49.415 31.255 50.035 ;
        RECT 31.425 49.815 31.780 50.035 ;
        RECT 31.425 49.225 31.595 49.815 ;
        RECT 31.950 49.615 32.120 50.325 ;
        RECT 32.995 50.255 33.325 50.715 ;
        RECT 33.535 50.355 33.885 50.525 ;
        RECT 32.325 49.785 33.115 50.035 ;
        RECT 33.535 49.965 33.795 50.355 ;
        RECT 34.105 50.265 35.055 50.545 ;
        RECT 35.225 50.275 35.415 50.715 ;
        RECT 35.585 50.335 36.655 50.505 ;
        RECT 33.285 49.615 33.455 49.795 ;
        RECT 30.565 48.795 30.960 48.965 ;
        RECT 31.130 48.835 31.595 49.225 ;
        RECT 31.765 49.445 33.455 49.615 ;
        RECT 30.790 48.665 30.960 48.795 ;
        RECT 31.765 48.665 31.935 49.445 ;
        RECT 33.625 49.275 33.795 49.965 ;
        RECT 32.295 49.105 33.795 49.275 ;
        RECT 33.985 49.305 34.195 50.095 ;
        RECT 34.365 49.475 34.715 50.095 ;
        RECT 34.885 49.485 35.055 50.265 ;
        RECT 35.585 50.105 35.755 50.335 ;
        RECT 35.225 49.935 35.755 50.105 ;
        RECT 35.225 49.655 35.445 49.935 ;
        RECT 35.925 49.765 36.165 50.165 ;
        RECT 34.885 49.315 35.290 49.485 ;
        RECT 35.625 49.395 36.165 49.765 ;
        RECT 36.335 49.980 36.655 50.335 ;
        RECT 36.900 50.255 37.205 50.715 ;
        RECT 37.375 50.005 37.625 50.535 ;
        RECT 36.335 49.805 36.660 49.980 ;
        RECT 36.335 49.505 37.250 49.805 ;
        RECT 36.510 49.475 37.250 49.505 ;
        RECT 33.985 49.145 34.660 49.305 ;
        RECT 35.120 49.225 35.290 49.315 ;
        RECT 33.985 49.135 34.950 49.145 ;
        RECT 33.625 48.965 33.795 49.105 ;
        RECT 30.370 48.165 30.620 48.625 ;
        RECT 30.790 48.335 31.040 48.665 ;
        RECT 31.255 48.335 31.935 48.665 ;
        RECT 32.105 48.765 33.180 48.935 ;
        RECT 33.625 48.795 34.185 48.965 ;
        RECT 34.490 48.845 34.950 49.135 ;
        RECT 35.120 49.055 36.340 49.225 ;
        RECT 32.105 48.425 32.275 48.765 ;
        RECT 32.510 48.165 32.840 48.595 ;
        RECT 33.010 48.425 33.180 48.765 ;
        RECT 33.475 48.165 33.845 48.625 ;
        RECT 34.015 48.335 34.185 48.795 ;
        RECT 35.120 48.675 35.290 49.055 ;
        RECT 36.510 48.885 36.680 49.475 ;
        RECT 37.420 49.355 37.625 50.005 ;
        RECT 37.795 49.960 38.045 50.715 ;
        RECT 38.265 49.965 39.475 50.715 ;
        RECT 39.645 49.965 40.855 50.715 ;
        RECT 41.025 49.965 42.235 50.715 ;
        RECT 43.325 49.965 44.535 50.715 ;
        RECT 38.265 49.425 38.785 49.965 ;
        RECT 34.420 48.335 35.290 48.675 ;
        RECT 35.880 48.715 36.680 48.885 ;
        RECT 35.460 48.165 35.710 48.625 ;
        RECT 35.880 48.425 36.050 48.715 ;
        RECT 36.230 48.165 36.560 48.545 ;
        RECT 36.900 48.165 37.205 49.305 ;
        RECT 37.375 48.475 37.625 49.355 ;
        RECT 37.795 48.165 38.045 49.305 ;
        RECT 38.955 49.255 39.475 49.795 ;
        RECT 39.645 49.425 40.165 49.965 ;
        RECT 40.335 49.255 40.855 49.795 ;
        RECT 41.025 49.425 41.545 49.965 ;
        RECT 41.715 49.255 42.235 49.795 ;
        RECT 38.265 48.165 39.475 49.255 ;
        RECT 39.645 48.165 40.855 49.255 ;
        RECT 41.025 48.165 42.235 49.255 ;
        RECT 43.325 49.255 43.845 49.795 ;
        RECT 44.015 49.425 44.535 49.965 ;
        RECT 43.325 48.165 44.535 49.255 ;
        RECT 2.300 47.995 44.620 48.165 ;
        RECT 2.385 46.905 3.595 47.995 ;
        RECT 2.385 46.195 2.905 46.735 ;
        RECT 3.075 46.365 3.595 46.905 ;
        RECT 3.825 46.855 4.035 47.995 ;
        RECT 4.205 46.845 4.535 47.825 ;
        RECT 4.705 46.855 4.935 47.995 ;
        RECT 5.205 46.855 5.415 47.995 ;
        RECT 5.585 46.845 5.915 47.825 ;
        RECT 6.085 46.855 6.315 47.995 ;
        RECT 6.585 46.855 6.795 47.995 ;
        RECT 6.965 46.845 7.295 47.825 ;
        RECT 7.465 46.855 7.695 47.995 ;
        RECT 7.905 46.905 9.115 47.995 ;
        RECT 9.285 46.905 10.495 47.995 ;
        RECT 10.665 46.905 11.875 47.995 ;
        RECT 2.385 45.445 3.595 46.195 ;
        RECT 3.825 45.445 4.035 46.265 ;
        RECT 4.205 46.245 4.455 46.845 ;
        RECT 4.625 46.435 4.955 46.685 ;
        RECT 4.205 45.615 4.535 46.245 ;
        RECT 4.705 45.445 4.935 46.265 ;
        RECT 5.205 45.445 5.415 46.265 ;
        RECT 5.585 46.245 5.835 46.845 ;
        RECT 6.005 46.435 6.335 46.685 ;
        RECT 5.585 45.615 5.915 46.245 ;
        RECT 6.085 45.445 6.315 46.265 ;
        RECT 6.585 45.445 6.795 46.265 ;
        RECT 6.965 46.245 7.215 46.845 ;
        RECT 7.385 46.435 7.715 46.685 ;
        RECT 6.965 45.615 7.295 46.245 ;
        RECT 7.465 45.445 7.695 46.265 ;
        RECT 7.905 46.195 8.425 46.735 ;
        RECT 8.595 46.365 9.115 46.905 ;
        RECT 9.285 46.195 9.805 46.735 ;
        RECT 9.975 46.365 10.495 46.905 ;
        RECT 10.665 46.195 11.185 46.735 ;
        RECT 11.355 46.365 11.875 46.905 ;
        RECT 12.545 46.855 12.775 47.995 ;
        RECT 12.945 46.845 13.275 47.825 ;
        RECT 13.445 46.855 13.655 47.995 ;
        RECT 13.885 46.905 15.095 47.995 ;
        RECT 12.525 46.435 12.855 46.685 ;
        RECT 7.905 45.445 9.115 46.195 ;
        RECT 9.285 45.445 10.495 46.195 ;
        RECT 10.665 45.445 11.875 46.195 ;
        RECT 12.545 45.445 12.775 46.265 ;
        RECT 13.025 46.245 13.275 46.845 ;
        RECT 12.945 45.615 13.275 46.245 ;
        RECT 13.445 45.445 13.655 46.265 ;
        RECT 13.885 46.195 14.405 46.735 ;
        RECT 14.575 46.365 15.095 46.905 ;
        RECT 15.265 46.830 15.555 47.995 ;
        RECT 15.725 46.905 16.935 47.995 ;
        RECT 17.140 47.495 17.420 47.825 ;
        RECT 17.590 47.495 17.840 47.995 ;
        RECT 18.010 47.655 19.100 47.825 ;
        RECT 18.010 47.495 18.260 47.655 ;
        RECT 18.850 47.495 19.100 47.655 ;
        RECT 17.165 47.485 17.335 47.495 ;
        RECT 18.085 47.485 18.255 47.495 ;
        RECT 19.305 47.485 19.620 47.825 ;
        RECT 19.790 47.495 20.040 47.995 ;
        RECT 18.430 47.315 18.680 47.485 ;
        RECT 19.410 47.315 19.620 47.485 ;
        RECT 20.210 47.315 20.460 47.825 ;
        RECT 20.630 47.495 20.935 47.995 ;
        RECT 21.105 47.655 22.715 47.825 ;
        RECT 21.105 47.315 21.875 47.655 ;
        RECT 15.725 46.195 16.245 46.735 ;
        RECT 16.415 46.365 16.935 46.905 ;
        RECT 17.140 47.145 19.240 47.315 ;
        RECT 19.410 47.145 21.875 47.315 ;
        RECT 17.140 46.265 17.310 47.145 ;
        RECT 19.070 46.975 19.240 47.145 ;
        RECT 22.045 46.985 22.295 47.485 ;
        RECT 22.465 47.155 22.715 47.655 ;
        RECT 23.090 47.325 23.345 47.825 ;
        RECT 23.515 47.495 23.845 47.995 ;
        RECT 23.090 47.155 23.840 47.325 ;
        RECT 17.725 46.805 18.900 46.975 ;
        RECT 19.070 46.805 21.805 46.975 ;
        RECT 17.725 46.635 17.895 46.805 ;
        RECT 18.730 46.635 18.900 46.805 ;
        RECT 17.565 46.435 17.895 46.635 ;
        RECT 18.065 46.435 18.560 46.635 ;
        RECT 18.730 46.435 20.250 46.635 ;
        RECT 20.440 46.435 21.110 46.635 ;
        RECT 21.635 46.605 21.805 46.805 ;
        RECT 22.045 46.775 22.915 46.985 ;
        RECT 21.635 46.435 22.295 46.605 ;
        RECT 21.305 46.265 21.475 46.295 ;
        RECT 22.505 46.265 22.915 46.775 ;
        RECT 23.090 46.335 23.440 46.985 ;
        RECT 13.885 45.445 15.095 46.195 ;
        RECT 15.265 45.445 15.555 46.170 ;
        RECT 15.725 45.445 16.935 46.195 ;
        RECT 17.140 46.085 18.720 46.265 ;
        RECT 17.210 45.445 17.380 45.915 ;
        RECT 17.550 45.615 17.880 46.085 ;
        RECT 18.050 45.445 18.220 45.915 ;
        RECT 18.390 45.615 18.720 46.085 ;
        RECT 19.330 46.085 20.420 46.265 ;
        RECT 18.890 45.445 19.060 45.915 ;
        RECT 19.330 45.615 19.660 46.085 ;
        RECT 19.830 45.445 20.000 45.915 ;
        RECT 20.170 45.835 20.420 46.085 ;
        RECT 20.645 46.085 22.915 46.265 ;
        RECT 23.610 46.165 23.840 47.155 ;
        RECT 20.645 46.005 20.975 46.085 ;
        RECT 22.005 46.005 22.335 46.085 ;
        RECT 23.090 45.995 23.840 46.165 ;
        RECT 20.170 45.615 21.400 45.835 ;
        RECT 21.665 45.445 21.835 45.915 ;
        RECT 22.505 45.445 22.675 45.915 ;
        RECT 23.090 45.705 23.345 45.995 ;
        RECT 23.515 45.445 23.845 45.825 ;
        RECT 24.015 45.705 24.185 47.825 ;
        RECT 24.355 47.025 24.680 47.810 ;
        RECT 24.850 47.535 25.100 47.995 ;
        RECT 25.270 47.495 25.520 47.825 ;
        RECT 25.735 47.495 26.415 47.825 ;
        RECT 25.270 47.365 25.440 47.495 ;
        RECT 25.045 47.195 25.440 47.365 ;
        RECT 24.415 45.975 24.875 47.025 ;
        RECT 25.045 45.835 25.215 47.195 ;
        RECT 25.610 46.935 26.075 47.325 ;
        RECT 25.385 46.125 25.735 46.745 ;
        RECT 25.905 46.345 26.075 46.935 ;
        RECT 26.245 46.715 26.415 47.495 ;
        RECT 26.585 47.395 26.755 47.735 ;
        RECT 26.990 47.565 27.320 47.995 ;
        RECT 27.490 47.395 27.660 47.735 ;
        RECT 27.955 47.535 28.325 47.995 ;
        RECT 26.585 47.225 27.660 47.395 ;
        RECT 28.495 47.365 28.665 47.825 ;
        RECT 28.900 47.485 29.770 47.825 ;
        RECT 29.940 47.535 30.190 47.995 ;
        RECT 28.105 47.195 28.665 47.365 ;
        RECT 28.105 47.055 28.275 47.195 ;
        RECT 26.775 46.885 28.275 47.055 ;
        RECT 28.970 47.025 29.430 47.315 ;
        RECT 26.245 46.545 27.935 46.715 ;
        RECT 25.905 46.125 26.260 46.345 ;
        RECT 26.430 45.835 26.600 46.545 ;
        RECT 26.805 46.125 27.595 46.375 ;
        RECT 27.765 46.365 27.935 46.545 ;
        RECT 28.105 46.195 28.275 46.885 ;
        RECT 24.545 45.445 24.875 45.805 ;
        RECT 25.045 45.665 25.540 45.835 ;
        RECT 25.745 45.665 26.600 45.835 ;
        RECT 27.475 45.445 27.805 45.905 ;
        RECT 28.015 45.805 28.275 46.195 ;
        RECT 28.465 47.015 29.430 47.025 ;
        RECT 29.600 47.105 29.770 47.485 ;
        RECT 30.360 47.445 30.530 47.735 ;
        RECT 30.710 47.615 31.040 47.995 ;
        RECT 30.360 47.275 31.160 47.445 ;
        RECT 28.465 46.855 29.140 47.015 ;
        RECT 29.600 46.935 30.820 47.105 ;
        RECT 28.465 46.065 28.675 46.855 ;
        RECT 29.600 46.845 29.770 46.935 ;
        RECT 28.845 46.065 29.195 46.685 ;
        RECT 29.365 46.675 29.770 46.845 ;
        RECT 29.365 45.895 29.535 46.675 ;
        RECT 29.705 46.225 29.925 46.505 ;
        RECT 30.105 46.395 30.645 46.765 ;
        RECT 30.990 46.685 31.160 47.275 ;
        RECT 31.380 46.855 31.685 47.995 ;
        RECT 31.855 46.805 32.105 47.685 ;
        RECT 32.275 46.855 32.525 47.995 ;
        RECT 32.805 46.855 33.015 47.995 ;
        RECT 30.990 46.655 31.730 46.685 ;
        RECT 29.705 46.055 30.235 46.225 ;
        RECT 28.015 45.635 28.365 45.805 ;
        RECT 28.585 45.615 29.535 45.895 ;
        RECT 29.705 45.445 29.895 45.885 ;
        RECT 30.065 45.825 30.235 46.055 ;
        RECT 30.405 45.995 30.645 46.395 ;
        RECT 30.815 46.355 31.730 46.655 ;
        RECT 30.815 46.180 31.140 46.355 ;
        RECT 30.815 45.825 31.135 46.180 ;
        RECT 31.900 46.155 32.105 46.805 ;
        RECT 33.185 46.845 33.515 47.825 ;
        RECT 33.685 46.855 33.915 47.995 ;
        RECT 34.625 46.855 34.855 47.995 ;
        RECT 35.025 46.845 35.355 47.825 ;
        RECT 35.525 46.855 35.735 47.995 ;
        RECT 36.005 46.855 36.235 47.995 ;
        RECT 36.405 46.845 36.735 47.825 ;
        RECT 36.905 46.855 37.115 47.995 ;
        RECT 37.345 46.905 38.555 47.995 ;
        RECT 38.725 46.905 39.935 47.995 ;
        RECT 30.065 45.655 31.135 45.825 ;
        RECT 31.380 45.445 31.685 45.905 ;
        RECT 31.855 45.625 32.105 46.155 ;
        RECT 32.275 45.445 32.525 46.200 ;
        RECT 32.805 45.445 33.015 46.265 ;
        RECT 33.185 46.245 33.435 46.845 ;
        RECT 33.605 46.435 33.935 46.685 ;
        RECT 34.605 46.435 34.935 46.685 ;
        RECT 33.185 45.615 33.515 46.245 ;
        RECT 33.685 45.445 33.915 46.265 ;
        RECT 34.625 45.445 34.855 46.265 ;
        RECT 35.105 46.245 35.355 46.845 ;
        RECT 35.985 46.435 36.315 46.685 ;
        RECT 35.025 45.615 35.355 46.245 ;
        RECT 35.525 45.445 35.735 46.265 ;
        RECT 36.005 45.445 36.235 46.265 ;
        RECT 36.485 46.245 36.735 46.845 ;
        RECT 36.405 45.615 36.735 46.245 ;
        RECT 36.905 45.445 37.115 46.265 ;
        RECT 37.345 46.195 37.865 46.735 ;
        RECT 38.035 46.365 38.555 46.905 ;
        RECT 38.725 46.195 39.245 46.735 ;
        RECT 39.415 46.365 39.935 46.905 ;
        RECT 41.025 46.830 41.315 47.995 ;
        RECT 41.485 46.905 42.695 47.995 ;
        RECT 41.485 46.195 42.005 46.735 ;
        RECT 42.175 46.365 42.695 46.905 ;
        RECT 43.325 46.905 44.535 47.995 ;
        RECT 43.325 46.365 43.845 46.905 ;
        RECT 44.015 46.195 44.535 46.735 ;
        RECT 37.345 45.445 38.555 46.195 ;
        RECT 38.725 45.445 39.935 46.195 ;
        RECT 41.025 45.445 41.315 46.170 ;
        RECT 41.485 45.445 42.695 46.195 ;
        RECT 43.325 45.445 44.535 46.195 ;
        RECT 2.300 45.275 44.620 45.445 ;
        RECT 2.385 44.525 3.595 45.275 ;
        RECT 3.765 44.525 4.975 45.275 ;
        RECT 5.150 44.725 5.405 45.015 ;
        RECT 5.575 44.895 5.905 45.275 ;
        RECT 5.150 44.555 5.900 44.725 ;
        RECT 2.385 43.985 2.905 44.525 ;
        RECT 3.075 43.815 3.595 44.355 ;
        RECT 3.765 43.985 4.285 44.525 ;
        RECT 4.455 43.815 4.975 44.355 ;
        RECT 2.385 42.725 3.595 43.815 ;
        RECT 3.765 42.725 4.975 43.815 ;
        RECT 5.150 43.735 5.500 44.385 ;
        RECT 5.670 43.565 5.900 44.555 ;
        RECT 5.150 43.395 5.900 43.565 ;
        RECT 5.150 42.895 5.405 43.395 ;
        RECT 5.575 42.725 5.905 43.225 ;
        RECT 6.075 42.895 6.245 45.015 ;
        RECT 6.605 44.915 6.935 45.275 ;
        RECT 7.105 44.885 7.600 45.055 ;
        RECT 7.805 44.885 8.660 45.055 ;
        RECT 6.475 43.695 6.935 44.745 ;
        RECT 6.415 42.910 6.740 43.695 ;
        RECT 7.105 43.525 7.275 44.885 ;
        RECT 7.445 43.975 7.795 44.595 ;
        RECT 7.965 44.375 8.320 44.595 ;
        RECT 7.965 43.785 8.135 44.375 ;
        RECT 8.490 44.175 8.660 44.885 ;
        RECT 9.535 44.815 9.865 45.275 ;
        RECT 10.075 44.915 10.425 45.085 ;
        RECT 8.865 44.345 9.655 44.595 ;
        RECT 10.075 44.525 10.335 44.915 ;
        RECT 10.645 44.825 11.595 45.105 ;
        RECT 11.765 44.835 11.955 45.275 ;
        RECT 12.125 44.895 13.195 45.065 ;
        RECT 9.825 44.175 9.995 44.355 ;
        RECT 7.105 43.355 7.500 43.525 ;
        RECT 7.670 43.395 8.135 43.785 ;
        RECT 8.305 44.005 9.995 44.175 ;
        RECT 7.330 43.225 7.500 43.355 ;
        RECT 8.305 43.225 8.475 44.005 ;
        RECT 10.165 43.835 10.335 44.525 ;
        RECT 8.835 43.665 10.335 43.835 ;
        RECT 10.525 43.865 10.735 44.655 ;
        RECT 10.905 44.035 11.255 44.655 ;
        RECT 11.425 44.045 11.595 44.825 ;
        RECT 12.125 44.665 12.295 44.895 ;
        RECT 11.765 44.495 12.295 44.665 ;
        RECT 11.765 44.215 11.985 44.495 ;
        RECT 12.465 44.325 12.705 44.725 ;
        RECT 11.425 43.875 11.830 44.045 ;
        RECT 12.165 43.955 12.705 44.325 ;
        RECT 12.875 44.540 13.195 44.895 ;
        RECT 13.440 44.815 13.745 45.275 ;
        RECT 13.915 44.565 14.165 45.095 ;
        RECT 12.875 44.365 13.200 44.540 ;
        RECT 12.875 44.065 13.790 44.365 ;
        RECT 13.050 44.035 13.790 44.065 ;
        RECT 10.525 43.705 11.200 43.865 ;
        RECT 11.660 43.785 11.830 43.875 ;
        RECT 10.525 43.695 11.490 43.705 ;
        RECT 10.165 43.525 10.335 43.665 ;
        RECT 6.910 42.725 7.160 43.185 ;
        RECT 7.330 42.895 7.580 43.225 ;
        RECT 7.795 42.895 8.475 43.225 ;
        RECT 8.645 43.325 9.720 43.495 ;
        RECT 10.165 43.355 10.725 43.525 ;
        RECT 11.030 43.405 11.490 43.695 ;
        RECT 11.660 43.615 12.880 43.785 ;
        RECT 8.645 42.985 8.815 43.325 ;
        RECT 9.050 42.725 9.380 43.155 ;
        RECT 9.550 42.985 9.720 43.325 ;
        RECT 10.015 42.725 10.385 43.185 ;
        RECT 10.555 42.895 10.725 43.355 ;
        RECT 11.660 43.235 11.830 43.615 ;
        RECT 13.050 43.445 13.220 44.035 ;
        RECT 13.960 43.915 14.165 44.565 ;
        RECT 14.335 44.520 14.585 45.275 ;
        RECT 14.855 44.755 15.110 45.055 ;
        RECT 15.280 44.875 15.610 45.275 ;
        RECT 14.805 44.705 15.110 44.755 ;
        RECT 15.780 44.705 15.950 45.055 ;
        RECT 16.250 44.795 16.420 45.275 ;
        RECT 16.655 44.765 17.005 45.095 ;
        RECT 17.175 44.795 17.345 45.275 ;
        RECT 14.805 44.625 15.950 44.705 ;
        RECT 14.805 44.595 16.515 44.625 ;
        RECT 14.805 44.535 16.665 44.595 ;
        RECT 10.960 42.895 11.830 43.235 ;
        RECT 12.420 43.275 13.220 43.445 ;
        RECT 12.000 42.725 12.250 43.185 ;
        RECT 12.420 42.985 12.590 43.275 ;
        RECT 12.770 42.725 13.100 43.105 ;
        RECT 13.440 42.725 13.745 43.865 ;
        RECT 13.915 43.035 14.165 43.915 ;
        RECT 14.805 43.865 14.975 44.535 ;
        RECT 15.780 44.455 16.665 44.535 ;
        RECT 16.345 44.425 16.665 44.455 ;
        RECT 15.150 44.035 15.450 44.365 ;
        RECT 14.335 42.725 14.585 43.865 ;
        RECT 14.805 43.435 15.110 43.865 ;
        RECT 15.280 43.575 15.450 44.035 ;
        RECT 15.710 43.745 16.245 44.285 ;
        RECT 16.495 44.035 16.665 44.425 ;
        RECT 16.835 43.865 17.005 44.765 ;
        RECT 17.595 44.625 17.855 45.070 ;
        RECT 16.610 43.660 17.005 43.865 ;
        RECT 17.175 44.455 17.855 44.625 ;
        RECT 18.050 44.520 18.285 44.850 ;
        RECT 18.455 44.535 18.785 45.275 ;
        RECT 19.020 44.895 20.215 45.105 ;
        RECT 15.280 43.490 16.390 43.575 ;
        RECT 17.175 43.550 17.345 44.455 ;
        RECT 17.515 43.720 17.855 44.285 ;
        RECT 18.050 43.865 18.220 44.520 ;
        RECT 19.020 44.455 19.295 44.895 ;
        RECT 19.465 44.555 19.795 44.725 ;
        RECT 19.470 44.455 19.795 44.555 ;
        RECT 19.965 44.665 20.215 44.895 ;
        RECT 20.385 44.835 20.555 45.275 ;
        RECT 20.725 44.665 21.075 45.105 ;
        RECT 19.965 44.455 21.075 44.665 ;
        RECT 21.245 44.525 22.455 45.275 ;
        RECT 23.630 44.725 23.960 45.105 ;
        RECT 24.130 44.895 25.315 45.065 ;
        RECT 25.575 44.805 25.745 45.275 ;
        RECT 23.630 44.555 24.175 44.725 ;
        RECT 18.395 44.035 18.740 44.365 ;
        RECT 18.970 43.865 19.300 44.285 ;
        RECT 18.050 43.695 19.300 43.865 ;
        RECT 17.175 43.490 17.855 43.550 ;
        RECT 18.050 43.500 18.350 43.695 ;
        RECT 19.470 43.525 19.750 44.455 ;
        RECT 19.930 44.085 21.075 44.285 ;
        RECT 19.930 43.915 20.120 44.085 ;
        RECT 21.245 43.985 21.765 44.525 ;
        RECT 19.925 43.745 20.120 43.915 ;
        RECT 19.930 43.705 20.120 43.745 ;
        RECT 20.300 43.525 20.575 43.865 ;
        RECT 15.280 43.405 17.855 43.490 ;
        RECT 16.220 43.320 17.855 43.405 ;
        RECT 14.805 42.995 16.005 43.235 ;
        RECT 16.185 42.725 16.515 43.150 ;
        RECT 17.030 42.725 17.390 43.150 ;
        RECT 17.595 43.140 17.855 43.320 ;
        RECT 18.520 42.725 18.775 43.525 ;
        RECT 18.975 43.355 20.575 43.525 ;
        RECT 18.975 42.895 19.305 43.355 ;
        RECT 19.475 42.725 20.050 43.185 ;
        RECT 20.220 42.895 20.575 43.355 ;
        RECT 20.745 42.725 21.075 43.865 ;
        RECT 21.935 43.815 22.455 44.355 ;
        RECT 23.545 44.035 23.805 44.385 ;
        RECT 24.005 43.915 24.175 44.555 ;
        RECT 24.545 44.625 24.930 44.715 ;
        RECT 25.915 44.625 26.245 45.090 ;
        RECT 24.545 44.455 26.245 44.625 ;
        RECT 26.415 44.455 26.585 45.275 ;
        RECT 26.755 44.625 27.085 45.095 ;
        RECT 27.255 44.795 27.425 45.275 ;
        RECT 26.755 44.455 27.515 44.625 ;
        RECT 28.145 44.550 28.435 45.275 ;
        RECT 29.070 44.725 29.325 45.015 ;
        RECT 29.495 44.895 29.825 45.275 ;
        RECT 29.070 44.555 29.820 44.725 ;
        RECT 24.345 44.085 24.690 44.285 ;
        RECT 24.860 44.085 25.250 44.285 ;
        RECT 24.005 43.865 24.790 43.915 ;
        RECT 21.245 42.725 22.455 43.815 ;
        RECT 23.710 43.690 24.790 43.865 ;
        RECT 23.710 42.895 24.040 43.690 ;
        RECT 24.210 42.725 24.450 43.510 ;
        RECT 24.620 43.485 24.790 43.690 ;
        RECT 24.960 43.655 25.250 44.085 ;
        RECT 25.440 44.075 25.925 44.285 ;
        RECT 26.095 44.075 26.535 44.285 ;
        RECT 26.705 44.075 27.035 44.285 ;
        RECT 25.440 43.655 25.745 44.075 ;
        RECT 26.705 43.905 26.875 44.075 ;
        RECT 25.915 43.735 26.875 43.905 ;
        RECT 25.915 43.485 26.085 43.735 ;
        RECT 24.620 43.315 26.085 43.485 ;
        RECT 25.010 42.895 25.765 43.315 ;
        RECT 26.255 42.725 26.585 43.565 ;
        RECT 27.205 43.485 27.515 44.455 ;
        RECT 26.755 43.315 27.515 43.485 ;
        RECT 26.755 42.895 27.005 43.315 ;
        RECT 27.175 42.725 27.515 43.145 ;
        RECT 28.145 42.725 28.435 43.890 ;
        RECT 29.070 43.735 29.420 44.385 ;
        RECT 29.590 43.565 29.820 44.555 ;
        RECT 29.070 43.395 29.820 43.565 ;
        RECT 29.070 42.895 29.325 43.395 ;
        RECT 29.495 42.725 29.825 43.225 ;
        RECT 29.995 42.895 30.165 45.015 ;
        RECT 30.525 44.915 30.855 45.275 ;
        RECT 31.025 44.885 31.520 45.055 ;
        RECT 31.725 44.885 32.580 45.055 ;
        RECT 30.395 43.695 30.855 44.745 ;
        RECT 30.335 42.910 30.660 43.695 ;
        RECT 31.025 43.525 31.195 44.885 ;
        RECT 31.365 43.975 31.715 44.595 ;
        RECT 31.885 44.375 32.240 44.595 ;
        RECT 31.885 43.785 32.055 44.375 ;
        RECT 32.410 44.175 32.580 44.885 ;
        RECT 33.455 44.815 33.785 45.275 ;
        RECT 33.995 44.915 34.345 45.085 ;
        RECT 32.785 44.345 33.575 44.595 ;
        RECT 33.995 44.525 34.255 44.915 ;
        RECT 34.565 44.825 35.515 45.105 ;
        RECT 35.685 44.835 35.875 45.275 ;
        RECT 36.045 44.895 37.115 45.065 ;
        RECT 33.745 44.175 33.915 44.355 ;
        RECT 31.025 43.355 31.420 43.525 ;
        RECT 31.590 43.395 32.055 43.785 ;
        RECT 32.225 44.005 33.915 44.175 ;
        RECT 31.250 43.225 31.420 43.355 ;
        RECT 32.225 43.225 32.395 44.005 ;
        RECT 34.085 43.835 34.255 44.525 ;
        RECT 32.755 43.665 34.255 43.835 ;
        RECT 34.445 43.865 34.655 44.655 ;
        RECT 34.825 44.035 35.175 44.655 ;
        RECT 35.345 44.045 35.515 44.825 ;
        RECT 36.045 44.665 36.215 44.895 ;
        RECT 35.685 44.495 36.215 44.665 ;
        RECT 35.685 44.215 35.905 44.495 ;
        RECT 36.385 44.325 36.625 44.725 ;
        RECT 35.345 43.875 35.750 44.045 ;
        RECT 36.085 43.955 36.625 44.325 ;
        RECT 36.795 44.540 37.115 44.895 ;
        RECT 37.360 44.815 37.665 45.275 ;
        RECT 37.835 44.565 38.085 45.095 ;
        RECT 36.795 44.365 37.120 44.540 ;
        RECT 36.795 44.065 37.710 44.365 ;
        RECT 36.970 44.035 37.710 44.065 ;
        RECT 34.445 43.705 35.120 43.865 ;
        RECT 35.580 43.785 35.750 43.875 ;
        RECT 34.445 43.695 35.410 43.705 ;
        RECT 34.085 43.525 34.255 43.665 ;
        RECT 30.830 42.725 31.080 43.185 ;
        RECT 31.250 42.895 31.500 43.225 ;
        RECT 31.715 42.895 32.395 43.225 ;
        RECT 32.565 43.325 33.640 43.495 ;
        RECT 34.085 43.355 34.645 43.525 ;
        RECT 34.950 43.405 35.410 43.695 ;
        RECT 35.580 43.615 36.800 43.785 ;
        RECT 32.565 42.985 32.735 43.325 ;
        RECT 32.970 42.725 33.300 43.155 ;
        RECT 33.470 42.985 33.640 43.325 ;
        RECT 33.935 42.725 34.305 43.185 ;
        RECT 34.475 42.895 34.645 43.355 ;
        RECT 35.580 43.235 35.750 43.615 ;
        RECT 36.970 43.445 37.140 44.035 ;
        RECT 37.880 43.915 38.085 44.565 ;
        RECT 38.255 44.520 38.505 45.275 ;
        RECT 38.725 44.525 39.935 45.275 ;
        RECT 40.105 44.525 41.315 45.275 ;
        RECT 41.485 44.525 42.695 45.275 ;
        RECT 43.325 44.525 44.535 45.275 ;
        RECT 38.725 43.985 39.245 44.525 ;
        RECT 34.880 42.895 35.750 43.235 ;
        RECT 36.340 43.275 37.140 43.445 ;
        RECT 35.920 42.725 36.170 43.185 ;
        RECT 36.340 42.985 36.510 43.275 ;
        RECT 36.690 42.725 37.020 43.105 ;
        RECT 37.360 42.725 37.665 43.865 ;
        RECT 37.835 43.035 38.085 43.915 ;
        RECT 38.255 42.725 38.505 43.865 ;
        RECT 39.415 43.815 39.935 44.355 ;
        RECT 40.105 43.985 40.625 44.525 ;
        RECT 40.795 43.815 41.315 44.355 ;
        RECT 41.485 43.985 42.005 44.525 ;
        RECT 42.175 43.815 42.695 44.355 ;
        RECT 38.725 42.725 39.935 43.815 ;
        RECT 40.105 42.725 41.315 43.815 ;
        RECT 41.485 42.725 42.695 43.815 ;
        RECT 43.325 43.815 43.845 44.355 ;
        RECT 44.015 43.985 44.535 44.525 ;
        RECT 43.325 42.725 44.535 43.815 ;
        RECT 2.300 42.555 44.620 42.725 ;
        RECT 2.385 41.465 3.595 42.555 ;
        RECT 3.765 41.465 4.975 42.555 ;
        RECT 2.385 40.755 2.905 41.295 ;
        RECT 3.075 40.925 3.595 41.465 ;
        RECT 3.765 40.755 4.285 41.295 ;
        RECT 4.455 40.925 4.975 41.465 ;
        RECT 6.125 41.415 6.335 42.555 ;
        RECT 6.505 41.405 6.835 42.385 ;
        RECT 7.005 41.415 7.235 42.555 ;
        RECT 7.445 41.465 8.655 42.555 ;
        RECT 8.825 41.465 10.035 42.555 ;
        RECT 10.205 41.465 11.415 42.555 ;
        RECT 11.585 41.465 12.795 42.555 ;
        RECT 12.965 41.465 14.175 42.555 ;
        RECT 2.385 40.005 3.595 40.755 ;
        RECT 3.765 40.005 4.975 40.755 ;
        RECT 6.125 40.005 6.335 40.825 ;
        RECT 6.505 40.805 6.755 41.405 ;
        RECT 6.925 40.995 7.255 41.245 ;
        RECT 6.505 40.175 6.835 40.805 ;
        RECT 7.005 40.005 7.235 40.825 ;
        RECT 7.445 40.755 7.965 41.295 ;
        RECT 8.135 40.925 8.655 41.465 ;
        RECT 8.825 40.755 9.345 41.295 ;
        RECT 9.515 40.925 10.035 41.465 ;
        RECT 10.205 40.755 10.725 41.295 ;
        RECT 10.895 40.925 11.415 41.465 ;
        RECT 11.585 40.755 12.105 41.295 ;
        RECT 12.275 40.925 12.795 41.465 ;
        RECT 12.965 40.755 13.485 41.295 ;
        RECT 13.655 40.925 14.175 41.465 ;
        RECT 15.265 41.390 15.555 42.555 ;
        RECT 15.725 42.045 16.925 42.285 ;
        RECT 17.105 42.130 17.435 42.555 ;
        RECT 17.950 42.130 18.310 42.555 ;
        RECT 18.515 41.960 18.775 42.140 ;
        RECT 17.140 41.875 18.775 41.960 ;
        RECT 15.725 41.415 16.030 41.845 ;
        RECT 16.200 41.790 18.775 41.875 ;
        RECT 16.200 41.705 17.310 41.790 ;
        RECT 18.095 41.730 18.775 41.790 ;
        RECT 7.445 40.005 8.655 40.755 ;
        RECT 8.825 40.005 10.035 40.755 ;
        RECT 10.205 40.005 11.415 40.755 ;
        RECT 11.585 40.005 12.795 40.755 ;
        RECT 12.965 40.005 14.175 40.755 ;
        RECT 15.725 40.745 15.895 41.415 ;
        RECT 16.200 41.245 16.370 41.705 ;
        RECT 16.070 40.915 16.370 41.245 ;
        RECT 16.630 40.995 17.165 41.535 ;
        RECT 17.530 41.415 17.925 41.620 ;
        RECT 17.415 40.855 17.585 41.245 ;
        RECT 17.265 40.825 17.585 40.855 ;
        RECT 16.700 40.745 17.585 40.825 ;
        RECT 15.265 40.005 15.555 40.730 ;
        RECT 15.725 40.685 17.585 40.745 ;
        RECT 15.725 40.655 17.435 40.685 ;
        RECT 15.725 40.575 16.870 40.655 ;
        RECT 15.725 40.525 16.030 40.575 ;
        RECT 15.775 40.225 16.030 40.525 ;
        RECT 16.200 40.005 16.530 40.405 ;
        RECT 16.700 40.225 16.870 40.575 ;
        RECT 17.755 40.515 17.925 41.415 ;
        RECT 18.095 40.825 18.265 41.730 ;
        RECT 18.435 40.995 18.775 41.560 ;
        RECT 18.945 41.465 20.155 42.555 ;
        RECT 18.095 40.655 18.775 40.825 ;
        RECT 17.170 40.005 17.340 40.485 ;
        RECT 17.575 40.185 17.925 40.515 ;
        RECT 18.095 40.005 18.265 40.485 ;
        RECT 18.515 40.210 18.775 40.655 ;
        RECT 18.945 40.755 19.465 41.295 ;
        RECT 19.635 40.925 20.155 41.465 ;
        RECT 20.490 41.590 20.820 42.385 ;
        RECT 20.990 41.770 21.230 42.555 ;
        RECT 21.790 41.965 22.545 42.385 ;
        RECT 21.400 41.795 22.865 41.965 ;
        RECT 21.400 41.590 21.570 41.795 ;
        RECT 20.490 41.415 21.570 41.590 ;
        RECT 20.785 41.365 21.570 41.415 ;
        RECT 20.325 40.895 20.585 41.245 ;
        RECT 18.945 40.005 20.155 40.755 ;
        RECT 20.785 40.725 20.955 41.365 ;
        RECT 21.740 41.195 22.030 41.625 ;
        RECT 21.125 40.995 21.470 41.195 ;
        RECT 21.640 40.995 22.030 41.195 ;
        RECT 22.220 41.205 22.525 41.625 ;
        RECT 22.695 41.545 22.865 41.795 ;
        RECT 23.035 41.715 23.365 42.555 ;
        RECT 23.535 41.965 23.785 42.385 ;
        RECT 23.955 42.135 24.295 42.555 ;
        RECT 23.535 41.795 24.295 41.965 ;
        RECT 22.695 41.375 23.655 41.545 ;
        RECT 23.485 41.205 23.655 41.375 ;
        RECT 22.220 40.995 22.705 41.205 ;
        RECT 22.875 40.995 23.315 41.205 ;
        RECT 23.485 40.995 23.815 41.205 ;
        RECT 23.985 40.825 24.295 41.795 ;
        RECT 24.465 41.465 25.675 42.555 ;
        RECT 25.845 41.465 27.055 42.555 ;
        RECT 20.410 40.555 20.955 40.725 ;
        RECT 21.325 40.655 23.025 40.825 ;
        RECT 21.325 40.565 21.710 40.655 ;
        RECT 20.410 40.175 20.740 40.555 ;
        RECT 20.910 40.215 22.095 40.385 ;
        RECT 22.355 40.005 22.525 40.475 ;
        RECT 22.695 40.190 23.025 40.655 ;
        RECT 23.195 40.005 23.365 40.825 ;
        RECT 23.535 40.655 24.295 40.825 ;
        RECT 24.465 40.755 24.985 41.295 ;
        RECT 25.155 40.925 25.675 41.465 ;
        RECT 25.845 40.755 26.365 41.295 ;
        RECT 26.535 40.925 27.055 41.465 ;
        RECT 28.185 41.415 28.415 42.555 ;
        RECT 28.585 41.405 28.915 42.385 ;
        RECT 29.085 41.415 29.295 42.555 ;
        RECT 29.525 41.465 30.735 42.555 ;
        RECT 28.165 40.995 28.495 41.245 ;
        RECT 23.535 40.185 23.865 40.655 ;
        RECT 24.035 40.005 24.205 40.485 ;
        RECT 24.465 40.005 25.675 40.755 ;
        RECT 25.845 40.005 27.055 40.755 ;
        RECT 28.185 40.005 28.415 40.825 ;
        RECT 28.665 40.805 28.915 41.405 ;
        RECT 28.585 40.175 28.915 40.805 ;
        RECT 29.085 40.005 29.295 40.825 ;
        RECT 29.525 40.755 30.045 41.295 ;
        RECT 30.215 40.925 30.735 41.465 ;
        RECT 31.415 41.415 31.665 42.555 ;
        RECT 31.835 41.365 32.085 42.245 ;
        RECT 32.255 41.415 32.560 42.555 ;
        RECT 32.900 42.175 33.230 42.555 ;
        RECT 33.410 42.005 33.580 42.295 ;
        RECT 33.750 42.095 34.000 42.555 ;
        RECT 32.780 41.835 33.580 42.005 ;
        RECT 34.170 42.045 35.040 42.385 ;
        RECT 29.525 40.005 30.735 40.755 ;
        RECT 31.415 40.005 31.665 40.760 ;
        RECT 31.835 40.715 32.040 41.365 ;
        RECT 32.780 41.245 32.950 41.835 ;
        RECT 34.170 41.665 34.340 42.045 ;
        RECT 35.275 41.925 35.445 42.385 ;
        RECT 35.615 42.095 35.985 42.555 ;
        RECT 36.280 41.955 36.450 42.295 ;
        RECT 36.620 42.125 36.950 42.555 ;
        RECT 37.185 41.955 37.355 42.295 ;
        RECT 33.120 41.495 34.340 41.665 ;
        RECT 34.510 41.585 34.970 41.875 ;
        RECT 35.275 41.755 35.835 41.925 ;
        RECT 36.280 41.785 37.355 41.955 ;
        RECT 37.525 42.055 38.205 42.385 ;
        RECT 38.420 42.055 38.670 42.385 ;
        RECT 38.840 42.095 39.090 42.555 ;
        RECT 35.665 41.615 35.835 41.755 ;
        RECT 34.510 41.575 35.475 41.585 ;
        RECT 34.170 41.405 34.340 41.495 ;
        RECT 34.800 41.415 35.475 41.575 ;
        RECT 32.210 41.215 32.950 41.245 ;
        RECT 32.210 40.915 33.125 41.215 ;
        RECT 32.800 40.740 33.125 40.915 ;
        RECT 31.835 40.185 32.085 40.715 ;
        RECT 32.255 40.005 32.560 40.465 ;
        RECT 32.805 40.385 33.125 40.740 ;
        RECT 33.295 40.955 33.835 41.325 ;
        RECT 34.170 41.235 34.575 41.405 ;
        RECT 33.295 40.555 33.535 40.955 ;
        RECT 34.015 40.785 34.235 41.065 ;
        RECT 33.705 40.615 34.235 40.785 ;
        RECT 33.705 40.385 33.875 40.615 ;
        RECT 34.405 40.455 34.575 41.235 ;
        RECT 34.745 40.625 35.095 41.245 ;
        RECT 35.265 40.625 35.475 41.415 ;
        RECT 35.665 41.445 37.165 41.615 ;
        RECT 35.665 40.755 35.835 41.445 ;
        RECT 37.525 41.275 37.695 42.055 ;
        RECT 38.500 41.925 38.670 42.055 ;
        RECT 36.005 41.105 37.695 41.275 ;
        RECT 37.865 41.495 38.330 41.885 ;
        RECT 38.500 41.755 38.895 41.925 ;
        RECT 36.005 40.925 36.175 41.105 ;
        RECT 32.805 40.215 33.875 40.385 ;
        RECT 34.045 40.005 34.235 40.445 ;
        RECT 34.405 40.175 35.355 40.455 ;
        RECT 35.665 40.365 35.925 40.755 ;
        RECT 36.345 40.685 37.135 40.935 ;
        RECT 35.575 40.195 35.925 40.365 ;
        RECT 36.135 40.005 36.465 40.465 ;
        RECT 37.340 40.395 37.510 41.105 ;
        RECT 37.865 40.905 38.035 41.495 ;
        RECT 37.680 40.685 38.035 40.905 ;
        RECT 38.205 40.685 38.555 41.305 ;
        RECT 38.725 40.395 38.895 41.755 ;
        RECT 39.260 41.585 39.585 42.370 ;
        RECT 39.065 40.535 39.525 41.585 ;
        RECT 37.340 40.225 38.195 40.395 ;
        RECT 38.400 40.225 38.895 40.395 ;
        RECT 39.065 40.005 39.395 40.365 ;
        RECT 39.755 40.265 39.925 42.385 ;
        RECT 40.095 42.055 40.425 42.555 ;
        RECT 40.595 41.885 40.850 42.385 ;
        RECT 40.100 41.715 40.850 41.885 ;
        RECT 40.100 40.725 40.330 41.715 ;
        RECT 40.500 40.895 40.850 41.545 ;
        RECT 41.025 41.390 41.315 42.555 ;
        RECT 41.485 41.465 42.695 42.555 ;
        RECT 41.485 40.755 42.005 41.295 ;
        RECT 42.175 40.925 42.695 41.465 ;
        RECT 43.325 41.465 44.535 42.555 ;
        RECT 43.325 40.925 43.845 41.465 ;
        RECT 44.015 40.755 44.535 41.295 ;
        RECT 40.100 40.555 40.850 40.725 ;
        RECT 40.095 40.005 40.425 40.385 ;
        RECT 40.595 40.265 40.850 40.555 ;
        RECT 41.025 40.005 41.315 40.730 ;
        RECT 41.485 40.005 42.695 40.755 ;
        RECT 43.325 40.005 44.535 40.755 ;
        RECT 2.300 39.835 44.620 40.005 ;
        RECT 2.385 39.085 3.595 39.835 ;
        RECT 3.765 39.085 4.975 39.835 ;
        RECT 5.150 39.285 5.405 39.575 ;
        RECT 5.575 39.455 5.905 39.835 ;
        RECT 5.150 39.115 5.900 39.285 ;
        RECT 2.385 38.545 2.905 39.085 ;
        RECT 3.075 38.375 3.595 38.915 ;
        RECT 3.765 38.545 4.285 39.085 ;
        RECT 4.455 38.375 4.975 38.915 ;
        RECT 2.385 37.285 3.595 38.375 ;
        RECT 3.765 37.285 4.975 38.375 ;
        RECT 5.150 38.295 5.500 38.945 ;
        RECT 5.670 38.125 5.900 39.115 ;
        RECT 5.150 37.955 5.900 38.125 ;
        RECT 5.150 37.455 5.405 37.955 ;
        RECT 5.575 37.285 5.905 37.785 ;
        RECT 6.075 37.455 6.245 39.575 ;
        RECT 6.605 39.475 6.935 39.835 ;
        RECT 7.105 39.445 7.600 39.615 ;
        RECT 7.805 39.445 8.660 39.615 ;
        RECT 6.475 38.255 6.935 39.305 ;
        RECT 6.415 37.470 6.740 38.255 ;
        RECT 7.105 38.085 7.275 39.445 ;
        RECT 7.445 38.535 7.795 39.155 ;
        RECT 7.965 38.935 8.320 39.155 ;
        RECT 7.965 38.345 8.135 38.935 ;
        RECT 8.490 38.735 8.660 39.445 ;
        RECT 9.535 39.375 9.865 39.835 ;
        RECT 10.075 39.475 10.425 39.645 ;
        RECT 8.865 38.905 9.655 39.155 ;
        RECT 10.075 39.085 10.335 39.475 ;
        RECT 10.645 39.385 11.595 39.665 ;
        RECT 11.765 39.395 11.955 39.835 ;
        RECT 12.125 39.455 13.195 39.625 ;
        RECT 9.825 38.735 9.995 38.915 ;
        RECT 7.105 37.915 7.500 38.085 ;
        RECT 7.670 37.955 8.135 38.345 ;
        RECT 8.305 38.565 9.995 38.735 ;
        RECT 7.330 37.785 7.500 37.915 ;
        RECT 8.305 37.785 8.475 38.565 ;
        RECT 10.165 38.395 10.335 39.085 ;
        RECT 8.835 38.225 10.335 38.395 ;
        RECT 10.525 38.425 10.735 39.215 ;
        RECT 10.905 38.595 11.255 39.215 ;
        RECT 11.425 38.605 11.595 39.385 ;
        RECT 12.125 39.225 12.295 39.455 ;
        RECT 11.765 39.055 12.295 39.225 ;
        RECT 11.765 38.775 11.985 39.055 ;
        RECT 12.465 38.885 12.705 39.285 ;
        RECT 11.425 38.435 11.830 38.605 ;
        RECT 12.165 38.515 12.705 38.885 ;
        RECT 12.875 39.100 13.195 39.455 ;
        RECT 13.440 39.375 13.745 39.835 ;
        RECT 13.915 39.125 14.165 39.655 ;
        RECT 12.875 38.925 13.200 39.100 ;
        RECT 12.875 38.625 13.790 38.925 ;
        RECT 13.050 38.595 13.790 38.625 ;
        RECT 10.525 38.265 11.200 38.425 ;
        RECT 11.660 38.345 11.830 38.435 ;
        RECT 10.525 38.255 11.490 38.265 ;
        RECT 10.165 38.085 10.335 38.225 ;
        RECT 6.910 37.285 7.160 37.745 ;
        RECT 7.330 37.455 7.580 37.785 ;
        RECT 7.795 37.455 8.475 37.785 ;
        RECT 8.645 37.885 9.720 38.055 ;
        RECT 10.165 37.915 10.725 38.085 ;
        RECT 11.030 37.965 11.490 38.255 ;
        RECT 11.660 38.175 12.880 38.345 ;
        RECT 8.645 37.545 8.815 37.885 ;
        RECT 9.050 37.285 9.380 37.715 ;
        RECT 9.550 37.545 9.720 37.885 ;
        RECT 10.015 37.285 10.385 37.745 ;
        RECT 10.555 37.455 10.725 37.915 ;
        RECT 11.660 37.795 11.830 38.175 ;
        RECT 13.050 38.005 13.220 38.595 ;
        RECT 13.960 38.475 14.165 39.125 ;
        RECT 14.335 39.080 14.585 39.835 ;
        RECT 14.805 39.085 16.015 39.835 ;
        RECT 16.185 39.085 17.395 39.835 ;
        RECT 17.565 39.085 18.775 39.835 ;
        RECT 18.945 39.085 20.155 39.835 ;
        RECT 20.325 39.085 21.535 39.835 ;
        RECT 21.705 39.085 22.915 39.835 ;
        RECT 23.085 39.085 24.295 39.835 ;
        RECT 24.465 39.085 25.675 39.835 ;
        RECT 25.845 39.085 27.055 39.835 ;
        RECT 28.145 39.110 28.435 39.835 ;
        RECT 28.605 39.085 29.815 39.835 ;
        RECT 29.985 39.085 31.195 39.835 ;
        RECT 31.365 39.085 32.575 39.835 ;
        RECT 14.805 38.545 15.325 39.085 ;
        RECT 10.960 37.455 11.830 37.795 ;
        RECT 12.420 37.835 13.220 38.005 ;
        RECT 12.000 37.285 12.250 37.745 ;
        RECT 12.420 37.545 12.590 37.835 ;
        RECT 12.770 37.285 13.100 37.665 ;
        RECT 13.440 37.285 13.745 38.425 ;
        RECT 13.915 37.595 14.165 38.475 ;
        RECT 14.335 37.285 14.585 38.425 ;
        RECT 15.495 38.375 16.015 38.915 ;
        RECT 16.185 38.545 16.705 39.085 ;
        RECT 16.875 38.375 17.395 38.915 ;
        RECT 17.565 38.545 18.085 39.085 ;
        RECT 18.255 38.375 18.775 38.915 ;
        RECT 18.945 38.545 19.465 39.085 ;
        RECT 19.635 38.375 20.155 38.915 ;
        RECT 20.325 38.545 20.845 39.085 ;
        RECT 21.015 38.375 21.535 38.915 ;
        RECT 21.705 38.545 22.225 39.085 ;
        RECT 22.395 38.375 22.915 38.915 ;
        RECT 23.085 38.545 23.605 39.085 ;
        RECT 23.775 38.375 24.295 38.915 ;
        RECT 24.465 38.545 24.985 39.085 ;
        RECT 25.155 38.375 25.675 38.915 ;
        RECT 25.845 38.545 26.365 39.085 ;
        RECT 26.535 38.375 27.055 38.915 ;
        RECT 28.605 38.545 29.125 39.085 ;
        RECT 14.805 37.285 16.015 38.375 ;
        RECT 16.185 37.285 17.395 38.375 ;
        RECT 17.565 37.285 18.775 38.375 ;
        RECT 18.945 37.285 20.155 38.375 ;
        RECT 20.325 37.285 21.535 38.375 ;
        RECT 21.705 37.285 22.915 38.375 ;
        RECT 23.085 37.285 24.295 38.375 ;
        RECT 24.465 37.285 25.675 38.375 ;
        RECT 25.845 37.285 27.055 38.375 ;
        RECT 28.145 37.285 28.435 38.450 ;
        RECT 29.295 38.375 29.815 38.915 ;
        RECT 29.985 38.545 30.505 39.085 ;
        RECT 30.675 38.375 31.195 38.915 ;
        RECT 31.365 38.545 31.885 39.085 ;
        RECT 33.715 39.080 33.965 39.835 ;
        RECT 34.135 39.125 34.385 39.655 ;
        RECT 34.555 39.375 34.860 39.835 ;
        RECT 35.105 39.455 36.175 39.625 ;
        RECT 32.055 38.375 32.575 38.915 ;
        RECT 34.135 38.475 34.340 39.125 ;
        RECT 35.105 39.100 35.425 39.455 ;
        RECT 35.100 38.925 35.425 39.100 ;
        RECT 34.510 38.625 35.425 38.925 ;
        RECT 35.595 38.885 35.835 39.285 ;
        RECT 36.005 39.225 36.175 39.455 ;
        RECT 36.345 39.395 36.535 39.835 ;
        RECT 36.705 39.385 37.655 39.665 ;
        RECT 37.875 39.475 38.225 39.645 ;
        RECT 36.005 39.055 36.535 39.225 ;
        RECT 34.510 38.595 35.250 38.625 ;
        RECT 28.605 37.285 29.815 38.375 ;
        RECT 29.985 37.285 31.195 38.375 ;
        RECT 31.365 37.285 32.575 38.375 ;
        RECT 33.715 37.285 33.965 38.425 ;
        RECT 34.135 37.595 34.385 38.475 ;
        RECT 34.555 37.285 34.860 38.425 ;
        RECT 35.080 38.005 35.250 38.595 ;
        RECT 35.595 38.515 36.135 38.885 ;
        RECT 36.315 38.775 36.535 39.055 ;
        RECT 36.705 38.605 36.875 39.385 ;
        RECT 36.470 38.435 36.875 38.605 ;
        RECT 37.045 38.595 37.395 39.215 ;
        RECT 36.470 38.345 36.640 38.435 ;
        RECT 37.565 38.425 37.775 39.215 ;
        RECT 35.420 38.175 36.640 38.345 ;
        RECT 37.100 38.265 37.775 38.425 ;
        RECT 35.080 37.835 35.880 38.005 ;
        RECT 35.200 37.285 35.530 37.665 ;
        RECT 35.710 37.545 35.880 37.835 ;
        RECT 36.470 37.795 36.640 38.175 ;
        RECT 36.810 38.255 37.775 38.265 ;
        RECT 37.965 39.085 38.225 39.475 ;
        RECT 38.435 39.375 38.765 39.835 ;
        RECT 39.640 39.445 40.495 39.615 ;
        RECT 40.700 39.445 41.195 39.615 ;
        RECT 41.365 39.475 41.695 39.835 ;
        RECT 37.965 38.395 38.135 39.085 ;
        RECT 38.305 38.735 38.475 38.915 ;
        RECT 38.645 38.905 39.435 39.155 ;
        RECT 39.640 38.735 39.810 39.445 ;
        RECT 39.980 38.935 40.335 39.155 ;
        RECT 38.305 38.565 39.995 38.735 ;
        RECT 36.810 37.965 37.270 38.255 ;
        RECT 37.965 38.225 39.465 38.395 ;
        RECT 37.965 38.085 38.135 38.225 ;
        RECT 37.575 37.915 38.135 38.085 ;
        RECT 36.050 37.285 36.300 37.745 ;
        RECT 36.470 37.455 37.340 37.795 ;
        RECT 37.575 37.455 37.745 37.915 ;
        RECT 38.580 37.885 39.655 38.055 ;
        RECT 37.915 37.285 38.285 37.745 ;
        RECT 38.580 37.545 38.750 37.885 ;
        RECT 38.920 37.285 39.250 37.715 ;
        RECT 39.485 37.545 39.655 37.885 ;
        RECT 39.825 37.785 39.995 38.565 ;
        RECT 40.165 38.345 40.335 38.935 ;
        RECT 40.505 38.535 40.855 39.155 ;
        RECT 40.165 37.955 40.630 38.345 ;
        RECT 41.025 38.085 41.195 39.445 ;
        RECT 41.365 38.255 41.825 39.305 ;
        RECT 40.800 37.915 41.195 38.085 ;
        RECT 40.800 37.785 40.970 37.915 ;
        RECT 39.825 37.455 40.505 37.785 ;
        RECT 40.720 37.455 40.970 37.785 ;
        RECT 41.140 37.285 41.390 37.745 ;
        RECT 41.560 37.470 41.885 38.255 ;
        RECT 42.055 37.455 42.225 39.575 ;
        RECT 42.395 39.455 42.725 39.835 ;
        RECT 42.895 39.285 43.150 39.575 ;
        RECT 42.400 39.115 43.150 39.285 ;
        RECT 42.400 38.125 42.630 39.115 ;
        RECT 43.325 39.085 44.535 39.835 ;
        RECT 42.800 38.295 43.150 38.945 ;
        RECT 43.325 38.375 43.845 38.915 ;
        RECT 44.015 38.545 44.535 39.085 ;
        RECT 42.400 37.955 43.150 38.125 ;
        RECT 42.395 37.285 42.725 37.785 ;
        RECT 42.895 37.455 43.150 37.955 ;
        RECT 43.325 37.285 44.535 38.375 ;
        RECT 2.300 37.115 44.620 37.285 ;
        RECT 2.385 36.025 3.595 37.115 ;
        RECT 3.765 36.025 4.975 37.115 ;
        RECT 5.145 36.025 6.355 37.115 ;
        RECT 6.525 36.025 7.735 37.115 ;
        RECT 2.385 35.315 2.905 35.855 ;
        RECT 3.075 35.485 3.595 36.025 ;
        RECT 3.765 35.315 4.285 35.855 ;
        RECT 4.455 35.485 4.975 36.025 ;
        RECT 5.145 35.315 5.665 35.855 ;
        RECT 5.835 35.485 6.355 36.025 ;
        RECT 6.525 35.315 7.045 35.855 ;
        RECT 7.215 35.485 7.735 36.025 ;
        RECT 8.885 35.975 9.095 37.115 ;
        RECT 9.265 35.965 9.595 36.945 ;
        RECT 9.765 35.975 9.995 37.115 ;
        RECT 10.205 36.025 11.415 37.115 ;
        RECT 2.385 34.565 3.595 35.315 ;
        RECT 3.765 34.565 4.975 35.315 ;
        RECT 5.145 34.565 6.355 35.315 ;
        RECT 6.525 34.565 7.735 35.315 ;
        RECT 8.885 34.565 9.095 35.385 ;
        RECT 9.265 35.365 9.515 35.965 ;
        RECT 9.685 35.555 10.015 35.805 ;
        RECT 9.265 34.735 9.595 35.365 ;
        RECT 9.765 34.565 9.995 35.385 ;
        RECT 10.205 35.315 10.725 35.855 ;
        RECT 10.895 35.485 11.415 36.025 ;
        RECT 12.085 35.975 12.315 37.115 ;
        RECT 12.485 35.965 12.815 36.945 ;
        RECT 12.985 35.975 13.195 37.115 ;
        RECT 13.425 36.025 14.635 37.115 ;
        RECT 12.065 35.555 12.395 35.805 ;
        RECT 10.205 34.565 11.415 35.315 ;
        RECT 12.085 34.565 12.315 35.385 ;
        RECT 12.565 35.365 12.815 35.965 ;
        RECT 12.485 34.735 12.815 35.365 ;
        RECT 12.985 34.565 13.195 35.385 ;
        RECT 13.425 35.315 13.945 35.855 ;
        RECT 14.115 35.485 14.635 36.025 ;
        RECT 15.265 35.950 15.555 37.115 ;
        RECT 16.705 35.975 16.915 37.115 ;
        RECT 17.085 35.965 17.415 36.945 ;
        RECT 17.585 35.975 17.815 37.115 ;
        RECT 18.025 36.025 19.235 37.115 ;
        RECT 19.405 36.025 20.615 37.115 ;
        RECT 20.785 36.025 21.995 37.115 ;
        RECT 22.165 36.025 23.375 37.115 ;
        RECT 23.545 36.025 24.755 37.115 ;
        RECT 24.925 36.025 26.135 37.115 ;
        RECT 26.305 36.025 27.515 37.115 ;
        RECT 27.685 36.025 28.895 37.115 ;
        RECT 29.065 36.025 30.275 37.115 ;
        RECT 30.445 36.025 31.655 37.115 ;
        RECT 31.825 36.025 33.035 37.115 ;
        RECT 33.205 36.025 34.415 37.115 ;
        RECT 13.425 34.565 14.635 35.315 ;
        RECT 15.265 34.565 15.555 35.290 ;
        RECT 16.705 34.565 16.915 35.385 ;
        RECT 17.085 35.365 17.335 35.965 ;
        RECT 17.505 35.555 17.835 35.805 ;
        RECT 17.085 34.735 17.415 35.365 ;
        RECT 17.585 34.565 17.815 35.385 ;
        RECT 18.025 35.315 18.545 35.855 ;
        RECT 18.715 35.485 19.235 36.025 ;
        RECT 19.405 35.315 19.925 35.855 ;
        RECT 20.095 35.485 20.615 36.025 ;
        RECT 20.785 35.315 21.305 35.855 ;
        RECT 21.475 35.485 21.995 36.025 ;
        RECT 22.165 35.315 22.685 35.855 ;
        RECT 22.855 35.485 23.375 36.025 ;
        RECT 23.545 35.315 24.065 35.855 ;
        RECT 24.235 35.485 24.755 36.025 ;
        RECT 24.925 35.315 25.445 35.855 ;
        RECT 25.615 35.485 26.135 36.025 ;
        RECT 26.305 35.315 26.825 35.855 ;
        RECT 26.995 35.485 27.515 36.025 ;
        RECT 27.685 35.315 28.205 35.855 ;
        RECT 28.375 35.485 28.895 36.025 ;
        RECT 29.065 35.315 29.585 35.855 ;
        RECT 29.755 35.485 30.275 36.025 ;
        RECT 30.445 35.315 30.965 35.855 ;
        RECT 31.135 35.485 31.655 36.025 ;
        RECT 31.825 35.315 32.345 35.855 ;
        RECT 32.515 35.485 33.035 36.025 ;
        RECT 33.205 35.315 33.725 35.855 ;
        RECT 33.895 35.485 34.415 36.025 ;
        RECT 35.085 35.975 35.315 37.115 ;
        RECT 35.485 35.965 35.815 36.945 ;
        RECT 35.985 35.975 36.195 37.115 ;
        RECT 36.465 35.975 36.695 37.115 ;
        RECT 36.865 35.965 37.195 36.945 ;
        RECT 37.365 35.975 37.575 37.115 ;
        RECT 37.805 36.025 39.015 37.115 ;
        RECT 39.185 36.025 40.395 37.115 ;
        RECT 35.065 35.555 35.395 35.805 ;
        RECT 18.025 34.565 19.235 35.315 ;
        RECT 19.405 34.565 20.615 35.315 ;
        RECT 20.785 34.565 21.995 35.315 ;
        RECT 22.165 34.565 23.375 35.315 ;
        RECT 23.545 34.565 24.755 35.315 ;
        RECT 24.925 34.565 26.135 35.315 ;
        RECT 26.305 34.565 27.515 35.315 ;
        RECT 27.685 34.565 28.895 35.315 ;
        RECT 29.065 34.565 30.275 35.315 ;
        RECT 30.445 34.565 31.655 35.315 ;
        RECT 31.825 34.565 33.035 35.315 ;
        RECT 33.205 34.565 34.415 35.315 ;
        RECT 35.085 34.565 35.315 35.385 ;
        RECT 35.565 35.365 35.815 35.965 ;
        RECT 36.445 35.555 36.775 35.805 ;
        RECT 35.485 34.735 35.815 35.365 ;
        RECT 35.985 34.565 36.195 35.385 ;
        RECT 36.465 34.565 36.695 35.385 ;
        RECT 36.945 35.365 37.195 35.965 ;
        RECT 36.865 34.735 37.195 35.365 ;
        RECT 37.365 34.565 37.575 35.385 ;
        RECT 37.805 35.315 38.325 35.855 ;
        RECT 38.495 35.485 39.015 36.025 ;
        RECT 39.185 35.315 39.705 35.855 ;
        RECT 39.875 35.485 40.395 36.025 ;
        RECT 41.025 35.950 41.315 37.115 ;
        RECT 41.485 36.025 42.695 37.115 ;
        RECT 41.485 35.315 42.005 35.855 ;
        RECT 42.175 35.485 42.695 36.025 ;
        RECT 43.325 36.025 44.535 37.115 ;
        RECT 43.325 35.485 43.845 36.025 ;
        RECT 44.015 35.315 44.535 35.855 ;
        RECT 37.805 34.565 39.015 35.315 ;
        RECT 39.185 34.565 40.395 35.315 ;
        RECT 41.025 34.565 41.315 35.290 ;
        RECT 41.485 34.565 42.695 35.315 ;
        RECT 43.325 34.565 44.535 35.315 ;
        RECT 2.300 34.395 44.620 34.565 ;
        RECT 2.385 33.645 3.595 34.395 ;
        RECT 3.765 33.645 4.975 34.395 ;
        RECT 5.145 33.645 6.355 34.395 ;
        RECT 6.525 33.645 7.735 34.395 ;
        RECT 7.905 33.645 9.115 34.395 ;
        RECT 9.285 33.645 10.495 34.395 ;
        RECT 10.665 33.645 11.875 34.395 ;
        RECT 12.970 33.845 13.225 34.135 ;
        RECT 13.395 34.015 13.725 34.395 ;
        RECT 12.970 33.675 13.720 33.845 ;
        RECT 2.385 33.105 2.905 33.645 ;
        RECT 3.075 32.935 3.595 33.475 ;
        RECT 3.765 33.105 4.285 33.645 ;
        RECT 4.455 32.935 4.975 33.475 ;
        RECT 5.145 33.105 5.665 33.645 ;
        RECT 5.835 32.935 6.355 33.475 ;
        RECT 6.525 33.105 7.045 33.645 ;
        RECT 7.215 32.935 7.735 33.475 ;
        RECT 7.905 33.105 8.425 33.645 ;
        RECT 8.595 32.935 9.115 33.475 ;
        RECT 9.285 33.105 9.805 33.645 ;
        RECT 9.975 32.935 10.495 33.475 ;
        RECT 10.665 33.105 11.185 33.645 ;
        RECT 11.355 32.935 11.875 33.475 ;
        RECT 2.385 31.845 3.595 32.935 ;
        RECT 3.765 31.845 4.975 32.935 ;
        RECT 5.145 31.845 6.355 32.935 ;
        RECT 6.525 31.845 7.735 32.935 ;
        RECT 7.905 31.845 9.115 32.935 ;
        RECT 9.285 31.845 10.495 32.935 ;
        RECT 10.665 31.845 11.875 32.935 ;
        RECT 12.970 32.855 13.320 33.505 ;
        RECT 13.490 32.685 13.720 33.675 ;
        RECT 12.970 32.515 13.720 32.685 ;
        RECT 12.970 32.015 13.225 32.515 ;
        RECT 13.395 31.845 13.725 32.345 ;
        RECT 13.895 32.015 14.065 34.135 ;
        RECT 14.425 34.035 14.755 34.395 ;
        RECT 14.925 34.005 15.420 34.175 ;
        RECT 15.625 34.005 16.480 34.175 ;
        RECT 14.295 32.815 14.755 33.865 ;
        RECT 14.235 32.030 14.560 32.815 ;
        RECT 14.925 32.645 15.095 34.005 ;
        RECT 15.265 33.095 15.615 33.715 ;
        RECT 15.785 33.495 16.140 33.715 ;
        RECT 15.785 32.905 15.955 33.495 ;
        RECT 16.310 33.295 16.480 34.005 ;
        RECT 17.355 33.935 17.685 34.395 ;
        RECT 17.895 34.035 18.245 34.205 ;
        RECT 16.685 33.465 17.475 33.715 ;
        RECT 17.895 33.645 18.155 34.035 ;
        RECT 18.465 33.945 19.415 34.225 ;
        RECT 19.585 33.955 19.775 34.395 ;
        RECT 19.945 34.015 21.015 34.185 ;
        RECT 17.645 33.295 17.815 33.475 ;
        RECT 14.925 32.475 15.320 32.645 ;
        RECT 15.490 32.515 15.955 32.905 ;
        RECT 16.125 33.125 17.815 33.295 ;
        RECT 15.150 32.345 15.320 32.475 ;
        RECT 16.125 32.345 16.295 33.125 ;
        RECT 17.985 32.955 18.155 33.645 ;
        RECT 16.655 32.785 18.155 32.955 ;
        RECT 18.345 32.985 18.555 33.775 ;
        RECT 18.725 33.155 19.075 33.775 ;
        RECT 19.245 33.165 19.415 33.945 ;
        RECT 19.945 33.785 20.115 34.015 ;
        RECT 19.585 33.615 20.115 33.785 ;
        RECT 19.585 33.335 19.805 33.615 ;
        RECT 20.285 33.445 20.525 33.845 ;
        RECT 19.245 32.995 19.650 33.165 ;
        RECT 19.985 33.075 20.525 33.445 ;
        RECT 20.695 33.660 21.015 34.015 ;
        RECT 21.260 33.935 21.565 34.395 ;
        RECT 21.735 33.685 21.985 34.215 ;
        RECT 20.695 33.485 21.020 33.660 ;
        RECT 20.695 33.185 21.610 33.485 ;
        RECT 20.870 33.155 21.610 33.185 ;
        RECT 18.345 32.825 19.020 32.985 ;
        RECT 19.480 32.905 19.650 32.995 ;
        RECT 18.345 32.815 19.310 32.825 ;
        RECT 17.985 32.645 18.155 32.785 ;
        RECT 14.730 31.845 14.980 32.305 ;
        RECT 15.150 32.015 15.400 32.345 ;
        RECT 15.615 32.015 16.295 32.345 ;
        RECT 16.465 32.445 17.540 32.615 ;
        RECT 17.985 32.475 18.545 32.645 ;
        RECT 18.850 32.525 19.310 32.815 ;
        RECT 19.480 32.735 20.700 32.905 ;
        RECT 16.465 32.105 16.635 32.445 ;
        RECT 16.870 31.845 17.200 32.275 ;
        RECT 17.370 32.105 17.540 32.445 ;
        RECT 17.835 31.845 18.205 32.305 ;
        RECT 18.375 32.015 18.545 32.475 ;
        RECT 19.480 32.355 19.650 32.735 ;
        RECT 20.870 32.565 21.040 33.155 ;
        RECT 21.780 33.035 21.985 33.685 ;
        RECT 22.155 33.640 22.405 34.395 ;
        RECT 23.585 33.575 23.815 34.395 ;
        RECT 23.985 33.595 24.315 34.225 ;
        RECT 23.565 33.155 23.895 33.405 ;
        RECT 18.780 32.015 19.650 32.355 ;
        RECT 20.240 32.395 21.040 32.565 ;
        RECT 19.820 31.845 20.070 32.305 ;
        RECT 20.240 32.105 20.410 32.395 ;
        RECT 20.590 31.845 20.920 32.225 ;
        RECT 21.260 31.845 21.565 32.985 ;
        RECT 21.735 32.155 21.985 33.035 ;
        RECT 24.065 32.995 24.315 33.595 ;
        RECT 24.485 33.575 24.695 34.395 ;
        RECT 24.985 33.575 25.195 34.395 ;
        RECT 25.365 33.595 25.695 34.225 ;
        RECT 22.155 31.845 22.405 32.985 ;
        RECT 23.585 31.845 23.815 32.985 ;
        RECT 23.985 32.015 24.315 32.995 ;
        RECT 25.365 32.995 25.615 33.595 ;
        RECT 25.865 33.575 26.095 34.395 ;
        RECT 26.305 33.645 27.515 34.395 ;
        RECT 28.145 33.670 28.435 34.395 ;
        RECT 25.785 33.155 26.115 33.405 ;
        RECT 26.305 33.105 26.825 33.645 ;
        RECT 29.105 33.575 29.335 34.395 ;
        RECT 29.505 33.595 29.835 34.225 ;
        RECT 24.485 31.845 24.695 32.985 ;
        RECT 24.985 31.845 25.195 32.985 ;
        RECT 25.365 32.015 25.695 32.995 ;
        RECT 25.865 31.845 26.095 32.985 ;
        RECT 26.995 32.935 27.515 33.475 ;
        RECT 29.085 33.155 29.415 33.405 ;
        RECT 26.305 31.845 27.515 32.935 ;
        RECT 28.145 31.845 28.435 33.010 ;
        RECT 29.585 32.995 29.835 33.595 ;
        RECT 30.005 33.575 30.215 34.395 ;
        RECT 30.450 33.845 30.705 34.135 ;
        RECT 30.875 34.015 31.205 34.395 ;
        RECT 30.450 33.675 31.200 33.845 ;
        RECT 29.105 31.845 29.335 32.985 ;
        RECT 29.505 32.015 29.835 32.995 ;
        RECT 30.005 31.845 30.215 32.985 ;
        RECT 30.450 32.855 30.800 33.505 ;
        RECT 30.970 32.685 31.200 33.675 ;
        RECT 30.450 32.515 31.200 32.685 ;
        RECT 30.450 32.015 30.705 32.515 ;
        RECT 30.875 31.845 31.205 32.345 ;
        RECT 31.375 32.015 31.545 34.135 ;
        RECT 31.905 34.035 32.235 34.395 ;
        RECT 32.405 34.005 32.900 34.175 ;
        RECT 33.105 34.005 33.960 34.175 ;
        RECT 31.775 32.815 32.235 33.865 ;
        RECT 31.715 32.030 32.040 32.815 ;
        RECT 32.405 32.645 32.575 34.005 ;
        RECT 32.745 33.095 33.095 33.715 ;
        RECT 33.265 33.495 33.620 33.715 ;
        RECT 33.265 32.905 33.435 33.495 ;
        RECT 33.790 33.295 33.960 34.005 ;
        RECT 34.835 33.935 35.165 34.395 ;
        RECT 35.375 34.035 35.725 34.205 ;
        RECT 34.165 33.465 34.955 33.715 ;
        RECT 35.375 33.645 35.635 34.035 ;
        RECT 35.945 33.945 36.895 34.225 ;
        RECT 37.065 33.955 37.255 34.395 ;
        RECT 37.425 34.015 38.495 34.185 ;
        RECT 35.125 33.295 35.295 33.475 ;
        RECT 32.405 32.475 32.800 32.645 ;
        RECT 32.970 32.515 33.435 32.905 ;
        RECT 33.605 33.125 35.295 33.295 ;
        RECT 32.630 32.345 32.800 32.475 ;
        RECT 33.605 32.345 33.775 33.125 ;
        RECT 35.465 32.955 35.635 33.645 ;
        RECT 34.135 32.785 35.635 32.955 ;
        RECT 35.825 32.985 36.035 33.775 ;
        RECT 36.205 33.155 36.555 33.775 ;
        RECT 36.725 33.165 36.895 33.945 ;
        RECT 37.425 33.785 37.595 34.015 ;
        RECT 37.065 33.615 37.595 33.785 ;
        RECT 37.065 33.335 37.285 33.615 ;
        RECT 37.765 33.445 38.005 33.845 ;
        RECT 36.725 32.995 37.130 33.165 ;
        RECT 37.465 33.075 38.005 33.445 ;
        RECT 38.175 33.660 38.495 34.015 ;
        RECT 38.740 33.935 39.045 34.395 ;
        RECT 39.215 33.685 39.465 34.215 ;
        RECT 38.175 33.485 38.500 33.660 ;
        RECT 38.175 33.185 39.090 33.485 ;
        RECT 38.350 33.155 39.090 33.185 ;
        RECT 35.825 32.825 36.500 32.985 ;
        RECT 36.960 32.905 37.130 32.995 ;
        RECT 35.825 32.815 36.790 32.825 ;
        RECT 35.465 32.645 35.635 32.785 ;
        RECT 32.210 31.845 32.460 32.305 ;
        RECT 32.630 32.015 32.880 32.345 ;
        RECT 33.095 32.015 33.775 32.345 ;
        RECT 33.945 32.445 35.020 32.615 ;
        RECT 35.465 32.475 36.025 32.645 ;
        RECT 36.330 32.525 36.790 32.815 ;
        RECT 36.960 32.735 38.180 32.905 ;
        RECT 33.945 32.105 34.115 32.445 ;
        RECT 34.350 31.845 34.680 32.275 ;
        RECT 34.850 32.105 35.020 32.445 ;
        RECT 35.315 31.845 35.685 32.305 ;
        RECT 35.855 32.015 36.025 32.475 ;
        RECT 36.960 32.355 37.130 32.735 ;
        RECT 38.350 32.565 38.520 33.155 ;
        RECT 39.260 33.035 39.465 33.685 ;
        RECT 39.635 33.640 39.885 34.395 ;
        RECT 40.105 33.645 41.315 34.395 ;
        RECT 41.485 33.645 42.695 34.395 ;
        RECT 43.325 33.645 44.535 34.395 ;
        RECT 40.105 33.105 40.625 33.645 ;
        RECT 36.260 32.015 37.130 32.355 ;
        RECT 37.720 32.395 38.520 32.565 ;
        RECT 37.300 31.845 37.550 32.305 ;
        RECT 37.720 32.105 37.890 32.395 ;
        RECT 38.070 31.845 38.400 32.225 ;
        RECT 38.740 31.845 39.045 32.985 ;
        RECT 39.215 32.155 39.465 33.035 ;
        RECT 39.635 31.845 39.885 32.985 ;
        RECT 40.795 32.935 41.315 33.475 ;
        RECT 41.485 33.105 42.005 33.645 ;
        RECT 42.175 32.935 42.695 33.475 ;
        RECT 40.105 31.845 41.315 32.935 ;
        RECT 41.485 31.845 42.695 32.935 ;
        RECT 43.325 32.935 43.845 33.475 ;
        RECT 44.015 33.105 44.535 33.645 ;
        RECT 43.325 31.845 44.535 32.935 ;
        RECT 2.300 31.675 44.620 31.845 ;
        RECT 2.385 30.585 3.595 31.675 ;
        RECT 3.765 30.585 4.975 31.675 ;
        RECT 5.145 30.585 6.355 31.675 ;
        RECT 6.525 30.585 7.735 31.675 ;
        RECT 7.905 30.585 9.115 31.675 ;
        RECT 2.385 29.875 2.905 30.415 ;
        RECT 3.075 30.045 3.595 30.585 ;
        RECT 3.765 29.875 4.285 30.415 ;
        RECT 4.455 30.045 4.975 30.585 ;
        RECT 5.145 29.875 5.665 30.415 ;
        RECT 5.835 30.045 6.355 30.585 ;
        RECT 6.525 29.875 7.045 30.415 ;
        RECT 7.215 30.045 7.735 30.585 ;
        RECT 7.905 29.875 8.425 30.415 ;
        RECT 8.595 30.045 9.115 30.585 ;
        RECT 9.805 30.535 10.015 31.675 ;
        RECT 10.185 30.525 10.515 31.505 ;
        RECT 10.685 30.535 10.915 31.675 ;
        RECT 11.125 30.585 12.335 31.675 ;
        RECT 12.505 30.585 13.715 31.675 ;
        RECT 13.885 30.585 15.095 31.675 ;
        RECT 2.385 29.125 3.595 29.875 ;
        RECT 3.765 29.125 4.975 29.875 ;
        RECT 5.145 29.125 6.355 29.875 ;
        RECT 6.525 29.125 7.735 29.875 ;
        RECT 7.905 29.125 9.115 29.875 ;
        RECT 9.805 29.125 10.015 29.945 ;
        RECT 10.185 29.925 10.435 30.525 ;
        RECT 10.605 30.115 10.935 30.365 ;
        RECT 10.185 29.295 10.515 29.925 ;
        RECT 10.685 29.125 10.915 29.945 ;
        RECT 11.125 29.875 11.645 30.415 ;
        RECT 11.815 30.045 12.335 30.585 ;
        RECT 12.505 29.875 13.025 30.415 ;
        RECT 13.195 30.045 13.715 30.585 ;
        RECT 13.885 29.875 14.405 30.415 ;
        RECT 14.575 30.045 15.095 30.585 ;
        RECT 15.265 30.510 15.555 31.675 ;
        RECT 15.725 30.585 16.935 31.675 ;
        RECT 17.105 30.585 18.315 31.675 ;
        RECT 15.725 29.875 16.245 30.415 ;
        RECT 16.415 30.045 16.935 30.585 ;
        RECT 17.105 29.875 17.625 30.415 ;
        RECT 17.795 30.045 18.315 30.585 ;
        RECT 18.545 30.535 18.755 31.675 ;
        RECT 18.925 30.525 19.255 31.505 ;
        RECT 19.425 30.535 19.655 31.675 ;
        RECT 19.865 30.585 21.075 31.675 ;
        RECT 11.125 29.125 12.335 29.875 ;
        RECT 12.505 29.125 13.715 29.875 ;
        RECT 13.885 29.125 15.095 29.875 ;
        RECT 15.265 29.125 15.555 29.850 ;
        RECT 15.725 29.125 16.935 29.875 ;
        RECT 17.105 29.125 18.315 29.875 ;
        RECT 18.545 29.125 18.755 29.945 ;
        RECT 18.925 29.925 19.175 30.525 ;
        RECT 19.345 30.115 19.675 30.365 ;
        RECT 18.925 29.295 19.255 29.925 ;
        RECT 19.425 29.125 19.655 29.945 ;
        RECT 19.865 29.875 20.385 30.415 ;
        RECT 20.555 30.045 21.075 30.585 ;
        RECT 22.225 30.535 22.435 31.675 ;
        RECT 22.605 30.525 22.935 31.505 ;
        RECT 23.105 30.535 23.335 31.675 ;
        RECT 24.010 31.005 24.265 31.505 ;
        RECT 24.435 31.175 24.765 31.675 ;
        RECT 24.010 30.835 24.760 31.005 ;
        RECT 19.865 29.125 21.075 29.875 ;
        RECT 22.225 29.125 22.435 29.945 ;
        RECT 22.605 29.925 22.855 30.525 ;
        RECT 23.025 30.115 23.355 30.365 ;
        RECT 24.010 30.015 24.360 30.665 ;
        RECT 22.605 29.295 22.935 29.925 ;
        RECT 23.105 29.125 23.335 29.945 ;
        RECT 24.530 29.845 24.760 30.835 ;
        RECT 24.010 29.675 24.760 29.845 ;
        RECT 24.010 29.385 24.265 29.675 ;
        RECT 24.435 29.125 24.765 29.505 ;
        RECT 24.935 29.385 25.105 31.505 ;
        RECT 25.275 30.705 25.600 31.490 ;
        RECT 25.770 31.215 26.020 31.675 ;
        RECT 26.190 31.175 26.440 31.505 ;
        RECT 26.655 31.175 27.335 31.505 ;
        RECT 26.190 31.045 26.360 31.175 ;
        RECT 25.965 30.875 26.360 31.045 ;
        RECT 25.335 29.655 25.795 30.705 ;
        RECT 25.965 29.515 26.135 30.875 ;
        RECT 26.530 30.615 26.995 31.005 ;
        RECT 26.305 29.805 26.655 30.425 ;
        RECT 26.825 30.025 26.995 30.615 ;
        RECT 27.165 30.395 27.335 31.175 ;
        RECT 27.505 31.075 27.675 31.415 ;
        RECT 27.910 31.245 28.240 31.675 ;
        RECT 28.410 31.075 28.580 31.415 ;
        RECT 28.875 31.215 29.245 31.675 ;
        RECT 27.505 30.905 28.580 31.075 ;
        RECT 29.415 31.045 29.585 31.505 ;
        RECT 29.820 31.165 30.690 31.505 ;
        RECT 30.860 31.215 31.110 31.675 ;
        RECT 29.025 30.875 29.585 31.045 ;
        RECT 29.025 30.735 29.195 30.875 ;
        RECT 27.695 30.565 29.195 30.735 ;
        RECT 29.890 30.705 30.350 30.995 ;
        RECT 27.165 30.225 28.855 30.395 ;
        RECT 26.825 29.805 27.180 30.025 ;
        RECT 27.350 29.515 27.520 30.225 ;
        RECT 27.725 29.805 28.515 30.055 ;
        RECT 28.685 30.045 28.855 30.225 ;
        RECT 29.025 29.875 29.195 30.565 ;
        RECT 25.465 29.125 25.795 29.485 ;
        RECT 25.965 29.345 26.460 29.515 ;
        RECT 26.665 29.345 27.520 29.515 ;
        RECT 28.395 29.125 28.725 29.585 ;
        RECT 28.935 29.485 29.195 29.875 ;
        RECT 29.385 30.695 30.350 30.705 ;
        RECT 30.520 30.785 30.690 31.165 ;
        RECT 31.280 31.125 31.450 31.415 ;
        RECT 31.630 31.295 31.960 31.675 ;
        RECT 31.280 30.955 32.080 31.125 ;
        RECT 29.385 30.535 30.060 30.695 ;
        RECT 30.520 30.615 31.740 30.785 ;
        RECT 29.385 29.745 29.595 30.535 ;
        RECT 30.520 30.525 30.690 30.615 ;
        RECT 29.765 29.745 30.115 30.365 ;
        RECT 30.285 30.355 30.690 30.525 ;
        RECT 30.285 29.575 30.455 30.355 ;
        RECT 30.625 29.905 30.845 30.185 ;
        RECT 31.025 30.075 31.565 30.445 ;
        RECT 31.910 30.365 32.080 30.955 ;
        RECT 32.300 30.535 32.605 31.675 ;
        RECT 32.775 30.485 33.025 31.365 ;
        RECT 33.195 30.535 33.445 31.675 ;
        RECT 33.725 30.535 33.935 31.675 ;
        RECT 31.910 30.335 32.650 30.365 ;
        RECT 30.625 29.735 31.155 29.905 ;
        RECT 28.935 29.315 29.285 29.485 ;
        RECT 29.505 29.295 30.455 29.575 ;
        RECT 30.625 29.125 30.815 29.565 ;
        RECT 30.985 29.505 31.155 29.735 ;
        RECT 31.325 29.675 31.565 30.075 ;
        RECT 31.735 30.035 32.650 30.335 ;
        RECT 31.735 29.860 32.060 30.035 ;
        RECT 31.735 29.505 32.055 29.860 ;
        RECT 32.820 29.835 33.025 30.485 ;
        RECT 34.105 30.525 34.435 31.505 ;
        RECT 34.605 30.535 34.835 31.675 ;
        RECT 35.045 30.585 36.255 31.675 ;
        RECT 36.425 30.585 37.635 31.675 ;
        RECT 37.805 30.585 39.015 31.675 ;
        RECT 39.185 30.585 40.395 31.675 ;
        RECT 30.985 29.335 32.055 29.505 ;
        RECT 32.300 29.125 32.605 29.585 ;
        RECT 32.775 29.305 33.025 29.835 ;
        RECT 33.195 29.125 33.445 29.880 ;
        RECT 33.725 29.125 33.935 29.945 ;
        RECT 34.105 29.925 34.355 30.525 ;
        RECT 34.525 30.115 34.855 30.365 ;
        RECT 34.105 29.295 34.435 29.925 ;
        RECT 34.605 29.125 34.835 29.945 ;
        RECT 35.045 29.875 35.565 30.415 ;
        RECT 35.735 30.045 36.255 30.585 ;
        RECT 36.425 29.875 36.945 30.415 ;
        RECT 37.115 30.045 37.635 30.585 ;
        RECT 37.805 29.875 38.325 30.415 ;
        RECT 38.495 30.045 39.015 30.585 ;
        RECT 39.185 29.875 39.705 30.415 ;
        RECT 39.875 30.045 40.395 30.585 ;
        RECT 41.025 30.510 41.315 31.675 ;
        RECT 41.485 30.585 42.695 31.675 ;
        RECT 41.485 29.875 42.005 30.415 ;
        RECT 42.175 30.045 42.695 30.585 ;
        RECT 43.325 30.585 44.535 31.675 ;
        RECT 43.325 30.045 43.845 30.585 ;
        RECT 44.015 29.875 44.535 30.415 ;
        RECT 35.045 29.125 36.255 29.875 ;
        RECT 36.425 29.125 37.635 29.875 ;
        RECT 37.805 29.125 39.015 29.875 ;
        RECT 39.185 29.125 40.395 29.875 ;
        RECT 41.025 29.125 41.315 29.850 ;
        RECT 41.485 29.125 42.695 29.875 ;
        RECT 43.325 29.125 44.535 29.875 ;
        RECT 2.300 28.955 44.620 29.125 ;
        RECT 2.385 28.205 3.595 28.955 ;
        RECT 3.765 28.205 4.975 28.955 ;
        RECT 5.145 28.205 6.355 28.955 ;
        RECT 2.385 27.665 2.905 28.205 ;
        RECT 3.075 27.495 3.595 28.035 ;
        RECT 3.765 27.665 4.285 28.205 ;
        RECT 4.455 27.495 4.975 28.035 ;
        RECT 5.145 27.665 5.665 28.205 ;
        RECT 7.505 28.135 7.715 28.955 ;
        RECT 7.885 28.155 8.215 28.785 ;
        RECT 5.835 27.495 6.355 28.035 ;
        RECT 7.885 27.555 8.135 28.155 ;
        RECT 8.385 28.135 8.615 28.955 ;
        RECT 8.830 28.405 9.085 28.695 ;
        RECT 9.255 28.575 9.585 28.955 ;
        RECT 8.830 28.235 9.580 28.405 ;
        RECT 8.305 27.715 8.635 27.965 ;
        RECT 2.385 26.405 3.595 27.495 ;
        RECT 3.765 26.405 4.975 27.495 ;
        RECT 5.145 26.405 6.355 27.495 ;
        RECT 7.505 26.405 7.715 27.545 ;
        RECT 7.885 26.575 8.215 27.555 ;
        RECT 8.385 26.405 8.615 27.545 ;
        RECT 8.830 27.415 9.180 28.065 ;
        RECT 9.350 27.245 9.580 28.235 ;
        RECT 8.830 27.075 9.580 27.245 ;
        RECT 8.830 26.575 9.085 27.075 ;
        RECT 9.255 26.405 9.585 26.905 ;
        RECT 9.755 26.575 9.925 28.695 ;
        RECT 10.285 28.595 10.615 28.955 ;
        RECT 10.785 28.565 11.280 28.735 ;
        RECT 11.485 28.565 12.340 28.735 ;
        RECT 10.155 27.375 10.615 28.425 ;
        RECT 10.095 26.590 10.420 27.375 ;
        RECT 10.785 27.205 10.955 28.565 ;
        RECT 11.125 27.655 11.475 28.275 ;
        RECT 11.645 28.055 12.000 28.275 ;
        RECT 11.645 27.465 11.815 28.055 ;
        RECT 12.170 27.855 12.340 28.565 ;
        RECT 13.215 28.495 13.545 28.955 ;
        RECT 13.755 28.595 14.105 28.765 ;
        RECT 12.545 28.025 13.335 28.275 ;
        RECT 13.755 28.205 14.015 28.595 ;
        RECT 14.325 28.505 15.275 28.785 ;
        RECT 15.445 28.515 15.635 28.955 ;
        RECT 15.805 28.575 16.875 28.745 ;
        RECT 13.505 27.855 13.675 28.035 ;
        RECT 10.785 27.035 11.180 27.205 ;
        RECT 11.350 27.075 11.815 27.465 ;
        RECT 11.985 27.685 13.675 27.855 ;
        RECT 11.010 26.905 11.180 27.035 ;
        RECT 11.985 26.905 12.155 27.685 ;
        RECT 13.845 27.515 14.015 28.205 ;
        RECT 12.515 27.345 14.015 27.515 ;
        RECT 14.205 27.545 14.415 28.335 ;
        RECT 14.585 27.715 14.935 28.335 ;
        RECT 15.105 27.725 15.275 28.505 ;
        RECT 15.805 28.345 15.975 28.575 ;
        RECT 15.445 28.175 15.975 28.345 ;
        RECT 15.445 27.895 15.665 28.175 ;
        RECT 16.145 28.005 16.385 28.405 ;
        RECT 15.105 27.555 15.510 27.725 ;
        RECT 15.845 27.635 16.385 28.005 ;
        RECT 16.555 28.220 16.875 28.575 ;
        RECT 17.120 28.495 17.425 28.955 ;
        RECT 17.595 28.245 17.845 28.775 ;
        RECT 16.555 28.045 16.880 28.220 ;
        RECT 16.555 27.745 17.470 28.045 ;
        RECT 16.730 27.715 17.470 27.745 ;
        RECT 14.205 27.385 14.880 27.545 ;
        RECT 15.340 27.465 15.510 27.555 ;
        RECT 14.205 27.375 15.170 27.385 ;
        RECT 13.845 27.205 14.015 27.345 ;
        RECT 10.590 26.405 10.840 26.865 ;
        RECT 11.010 26.575 11.260 26.905 ;
        RECT 11.475 26.575 12.155 26.905 ;
        RECT 12.325 27.005 13.400 27.175 ;
        RECT 13.845 27.035 14.405 27.205 ;
        RECT 14.710 27.085 15.170 27.375 ;
        RECT 15.340 27.295 16.560 27.465 ;
        RECT 12.325 26.665 12.495 27.005 ;
        RECT 12.730 26.405 13.060 26.835 ;
        RECT 13.230 26.665 13.400 27.005 ;
        RECT 13.695 26.405 14.065 26.865 ;
        RECT 14.235 26.575 14.405 27.035 ;
        RECT 15.340 26.915 15.510 27.295 ;
        RECT 16.730 27.125 16.900 27.715 ;
        RECT 17.640 27.595 17.845 28.245 ;
        RECT 18.015 28.200 18.265 28.955 ;
        RECT 18.490 28.405 18.745 28.695 ;
        RECT 18.915 28.575 19.245 28.955 ;
        RECT 18.490 28.235 19.240 28.405 ;
        RECT 14.640 26.575 15.510 26.915 ;
        RECT 16.100 26.955 16.900 27.125 ;
        RECT 15.680 26.405 15.930 26.865 ;
        RECT 16.100 26.665 16.270 26.955 ;
        RECT 16.450 26.405 16.780 26.785 ;
        RECT 17.120 26.405 17.425 27.545 ;
        RECT 17.595 26.715 17.845 27.595 ;
        RECT 18.015 26.405 18.265 27.545 ;
        RECT 18.490 27.415 18.840 28.065 ;
        RECT 19.010 27.245 19.240 28.235 ;
        RECT 18.490 27.075 19.240 27.245 ;
        RECT 18.490 26.575 18.745 27.075 ;
        RECT 18.915 26.405 19.245 26.905 ;
        RECT 19.415 26.575 19.585 28.695 ;
        RECT 19.945 28.595 20.275 28.955 ;
        RECT 20.445 28.565 20.940 28.735 ;
        RECT 21.145 28.565 22.000 28.735 ;
        RECT 19.815 27.375 20.275 28.425 ;
        RECT 19.755 26.590 20.080 27.375 ;
        RECT 20.445 27.205 20.615 28.565 ;
        RECT 20.785 27.655 21.135 28.275 ;
        RECT 21.305 28.055 21.660 28.275 ;
        RECT 21.305 27.465 21.475 28.055 ;
        RECT 21.830 27.855 22.000 28.565 ;
        RECT 22.875 28.495 23.205 28.955 ;
        RECT 23.415 28.595 23.765 28.765 ;
        RECT 22.205 28.025 22.995 28.275 ;
        RECT 23.415 28.205 23.675 28.595 ;
        RECT 23.985 28.505 24.935 28.785 ;
        RECT 25.105 28.515 25.295 28.955 ;
        RECT 25.465 28.575 26.535 28.745 ;
        RECT 23.165 27.855 23.335 28.035 ;
        RECT 20.445 27.035 20.840 27.205 ;
        RECT 21.010 27.075 21.475 27.465 ;
        RECT 21.645 27.685 23.335 27.855 ;
        RECT 20.670 26.905 20.840 27.035 ;
        RECT 21.645 26.905 21.815 27.685 ;
        RECT 23.505 27.515 23.675 28.205 ;
        RECT 22.175 27.345 23.675 27.515 ;
        RECT 23.865 27.545 24.075 28.335 ;
        RECT 24.245 27.715 24.595 28.335 ;
        RECT 24.765 27.725 24.935 28.505 ;
        RECT 25.465 28.345 25.635 28.575 ;
        RECT 25.105 28.175 25.635 28.345 ;
        RECT 25.105 27.895 25.325 28.175 ;
        RECT 25.805 28.005 26.045 28.405 ;
        RECT 24.765 27.555 25.170 27.725 ;
        RECT 25.505 27.635 26.045 28.005 ;
        RECT 26.215 28.220 26.535 28.575 ;
        RECT 26.780 28.495 27.085 28.955 ;
        RECT 27.255 28.245 27.505 28.775 ;
        RECT 26.215 28.045 26.540 28.220 ;
        RECT 26.215 27.745 27.130 28.045 ;
        RECT 26.390 27.715 27.130 27.745 ;
        RECT 23.865 27.385 24.540 27.545 ;
        RECT 25.000 27.465 25.170 27.555 ;
        RECT 23.865 27.375 24.830 27.385 ;
        RECT 23.505 27.205 23.675 27.345 ;
        RECT 20.250 26.405 20.500 26.865 ;
        RECT 20.670 26.575 20.920 26.905 ;
        RECT 21.135 26.575 21.815 26.905 ;
        RECT 21.985 27.005 23.060 27.175 ;
        RECT 23.505 27.035 24.065 27.205 ;
        RECT 24.370 27.085 24.830 27.375 ;
        RECT 25.000 27.295 26.220 27.465 ;
        RECT 21.985 26.665 22.155 27.005 ;
        RECT 22.390 26.405 22.720 26.835 ;
        RECT 22.890 26.665 23.060 27.005 ;
        RECT 23.355 26.405 23.725 26.865 ;
        RECT 23.895 26.575 24.065 27.035 ;
        RECT 25.000 26.915 25.170 27.295 ;
        RECT 26.390 27.125 26.560 27.715 ;
        RECT 27.300 27.595 27.505 28.245 ;
        RECT 27.675 28.200 27.925 28.955 ;
        RECT 28.145 28.230 28.435 28.955 ;
        RECT 28.605 28.205 29.815 28.955 ;
        RECT 29.985 28.205 31.195 28.955 ;
        RECT 31.365 28.205 32.575 28.955 ;
        RECT 32.745 28.205 33.955 28.955 ;
        RECT 34.125 28.205 35.335 28.955 ;
        RECT 35.505 28.205 36.715 28.955 ;
        RECT 36.885 28.205 38.095 28.955 ;
        RECT 38.265 28.205 39.475 28.955 ;
        RECT 39.645 28.205 40.855 28.955 ;
        RECT 41.025 28.205 42.235 28.955 ;
        RECT 43.325 28.205 44.535 28.955 ;
        RECT 28.605 27.665 29.125 28.205 ;
        RECT 24.300 26.575 25.170 26.915 ;
        RECT 25.760 26.955 26.560 27.125 ;
        RECT 25.340 26.405 25.590 26.865 ;
        RECT 25.760 26.665 25.930 26.955 ;
        RECT 26.110 26.405 26.440 26.785 ;
        RECT 26.780 26.405 27.085 27.545 ;
        RECT 27.255 26.715 27.505 27.595 ;
        RECT 27.675 26.405 27.925 27.545 ;
        RECT 28.145 26.405 28.435 27.570 ;
        RECT 29.295 27.495 29.815 28.035 ;
        RECT 29.985 27.665 30.505 28.205 ;
        RECT 30.675 27.495 31.195 28.035 ;
        RECT 31.365 27.665 31.885 28.205 ;
        RECT 32.055 27.495 32.575 28.035 ;
        RECT 32.745 27.665 33.265 28.205 ;
        RECT 33.435 27.495 33.955 28.035 ;
        RECT 34.125 27.665 34.645 28.205 ;
        RECT 34.815 27.495 35.335 28.035 ;
        RECT 35.505 27.665 36.025 28.205 ;
        RECT 36.195 27.495 36.715 28.035 ;
        RECT 36.885 27.665 37.405 28.205 ;
        RECT 37.575 27.495 38.095 28.035 ;
        RECT 38.265 27.665 38.785 28.205 ;
        RECT 38.955 27.495 39.475 28.035 ;
        RECT 39.645 27.665 40.165 28.205 ;
        RECT 40.335 27.495 40.855 28.035 ;
        RECT 41.025 27.665 41.545 28.205 ;
        RECT 41.715 27.495 42.235 28.035 ;
        RECT 28.605 26.405 29.815 27.495 ;
        RECT 29.985 26.405 31.195 27.495 ;
        RECT 31.365 26.405 32.575 27.495 ;
        RECT 32.745 26.405 33.955 27.495 ;
        RECT 34.125 26.405 35.335 27.495 ;
        RECT 35.505 26.405 36.715 27.495 ;
        RECT 36.885 26.405 38.095 27.495 ;
        RECT 38.265 26.405 39.475 27.495 ;
        RECT 39.645 26.405 40.855 27.495 ;
        RECT 41.025 26.405 42.235 27.495 ;
        RECT 43.325 27.495 43.845 28.035 ;
        RECT 44.015 27.665 44.535 28.205 ;
        RECT 43.325 26.405 44.535 27.495 ;
        RECT 2.300 26.235 44.620 26.405 ;
        RECT 2.385 25.145 3.595 26.235 ;
        RECT 3.765 25.145 4.975 26.235 ;
        RECT 5.610 25.565 5.865 26.065 ;
        RECT 6.035 25.735 6.365 26.235 ;
        RECT 5.610 25.395 6.360 25.565 ;
        RECT 2.385 24.435 2.905 24.975 ;
        RECT 3.075 24.605 3.595 25.145 ;
        RECT 3.765 24.435 4.285 24.975 ;
        RECT 4.455 24.605 4.975 25.145 ;
        RECT 5.610 24.575 5.960 25.225 ;
        RECT 2.385 23.685 3.595 24.435 ;
        RECT 3.765 23.685 4.975 24.435 ;
        RECT 6.130 24.405 6.360 25.395 ;
        RECT 5.610 24.235 6.360 24.405 ;
        RECT 5.610 23.945 5.865 24.235 ;
        RECT 6.035 23.685 6.365 24.065 ;
        RECT 6.535 23.945 6.705 26.065 ;
        RECT 6.875 25.265 7.200 26.050 ;
        RECT 7.370 25.775 7.620 26.235 ;
        RECT 7.790 25.735 8.040 26.065 ;
        RECT 8.255 25.735 8.935 26.065 ;
        RECT 7.790 25.605 7.960 25.735 ;
        RECT 7.565 25.435 7.960 25.605 ;
        RECT 6.935 24.215 7.395 25.265 ;
        RECT 7.565 24.075 7.735 25.435 ;
        RECT 8.130 25.175 8.595 25.565 ;
        RECT 7.905 24.365 8.255 24.985 ;
        RECT 8.425 24.585 8.595 25.175 ;
        RECT 8.765 24.955 8.935 25.735 ;
        RECT 9.105 25.635 9.275 25.975 ;
        RECT 9.510 25.805 9.840 26.235 ;
        RECT 10.010 25.635 10.180 25.975 ;
        RECT 10.475 25.775 10.845 26.235 ;
        RECT 9.105 25.465 10.180 25.635 ;
        RECT 11.015 25.605 11.185 26.065 ;
        RECT 11.420 25.725 12.290 26.065 ;
        RECT 12.460 25.775 12.710 26.235 ;
        RECT 10.625 25.435 11.185 25.605 ;
        RECT 10.625 25.295 10.795 25.435 ;
        RECT 9.295 25.125 10.795 25.295 ;
        RECT 11.490 25.265 11.950 25.555 ;
        RECT 8.765 24.785 10.455 24.955 ;
        RECT 8.425 24.365 8.780 24.585 ;
        RECT 8.950 24.075 9.120 24.785 ;
        RECT 9.325 24.365 10.115 24.615 ;
        RECT 10.285 24.605 10.455 24.785 ;
        RECT 10.625 24.435 10.795 25.125 ;
        RECT 7.065 23.685 7.395 24.045 ;
        RECT 7.565 23.905 8.060 24.075 ;
        RECT 8.265 23.905 9.120 24.075 ;
        RECT 9.995 23.685 10.325 24.145 ;
        RECT 10.535 24.045 10.795 24.435 ;
        RECT 10.985 25.255 11.950 25.265 ;
        RECT 12.120 25.345 12.290 25.725 ;
        RECT 12.880 25.685 13.050 25.975 ;
        RECT 13.230 25.855 13.560 26.235 ;
        RECT 12.880 25.515 13.680 25.685 ;
        RECT 10.985 25.095 11.660 25.255 ;
        RECT 12.120 25.175 13.340 25.345 ;
        RECT 10.985 24.305 11.195 25.095 ;
        RECT 12.120 25.085 12.290 25.175 ;
        RECT 11.365 24.305 11.715 24.925 ;
        RECT 11.885 24.915 12.290 25.085 ;
        RECT 11.885 24.135 12.055 24.915 ;
        RECT 12.225 24.465 12.445 24.745 ;
        RECT 12.625 24.635 13.165 25.005 ;
        RECT 13.510 24.925 13.680 25.515 ;
        RECT 13.900 25.095 14.205 26.235 ;
        RECT 14.375 25.045 14.625 25.925 ;
        RECT 14.795 25.095 15.045 26.235 ;
        RECT 15.265 25.070 15.555 26.235 ;
        RECT 15.725 25.145 16.935 26.235 ;
        RECT 17.105 25.145 18.315 26.235 ;
        RECT 18.485 25.145 19.695 26.235 ;
        RECT 19.865 25.145 21.075 26.235 ;
        RECT 21.245 25.145 22.455 26.235 ;
        RECT 22.625 25.145 23.835 26.235 ;
        RECT 24.005 25.145 25.215 26.235 ;
        RECT 25.385 25.145 26.595 26.235 ;
        RECT 26.765 25.145 27.975 26.235 ;
        RECT 28.145 25.145 29.355 26.235 ;
        RECT 29.525 25.145 30.735 26.235 ;
        RECT 30.905 25.145 32.115 26.235 ;
        RECT 32.285 25.145 33.495 26.235 ;
        RECT 33.665 25.145 34.875 26.235 ;
        RECT 35.045 25.145 36.255 26.235 ;
        RECT 36.425 25.145 37.635 26.235 ;
        RECT 37.805 25.145 39.015 26.235 ;
        RECT 39.185 25.145 40.395 26.235 ;
        RECT 13.510 24.895 14.250 24.925 ;
        RECT 12.225 24.295 12.755 24.465 ;
        RECT 10.535 23.875 10.885 24.045 ;
        RECT 11.105 23.855 12.055 24.135 ;
        RECT 12.225 23.685 12.415 24.125 ;
        RECT 12.585 24.065 12.755 24.295 ;
        RECT 12.925 24.235 13.165 24.635 ;
        RECT 13.335 24.595 14.250 24.895 ;
        RECT 13.335 24.420 13.660 24.595 ;
        RECT 13.335 24.065 13.655 24.420 ;
        RECT 14.420 24.395 14.625 25.045 ;
        RECT 12.585 23.895 13.655 24.065 ;
        RECT 13.900 23.685 14.205 24.145 ;
        RECT 14.375 23.865 14.625 24.395 ;
        RECT 14.795 23.685 15.045 24.440 ;
        RECT 15.725 24.435 16.245 24.975 ;
        RECT 16.415 24.605 16.935 25.145 ;
        RECT 17.105 24.435 17.625 24.975 ;
        RECT 17.795 24.605 18.315 25.145 ;
        RECT 18.485 24.435 19.005 24.975 ;
        RECT 19.175 24.605 19.695 25.145 ;
        RECT 19.865 24.435 20.385 24.975 ;
        RECT 20.555 24.605 21.075 25.145 ;
        RECT 21.245 24.435 21.765 24.975 ;
        RECT 21.935 24.605 22.455 25.145 ;
        RECT 22.625 24.435 23.145 24.975 ;
        RECT 23.315 24.605 23.835 25.145 ;
        RECT 24.005 24.435 24.525 24.975 ;
        RECT 24.695 24.605 25.215 25.145 ;
        RECT 25.385 24.435 25.905 24.975 ;
        RECT 26.075 24.605 26.595 25.145 ;
        RECT 26.765 24.435 27.285 24.975 ;
        RECT 27.455 24.605 27.975 25.145 ;
        RECT 28.145 24.435 28.665 24.975 ;
        RECT 28.835 24.605 29.355 25.145 ;
        RECT 29.525 24.435 30.045 24.975 ;
        RECT 30.215 24.605 30.735 25.145 ;
        RECT 30.905 24.435 31.425 24.975 ;
        RECT 31.595 24.605 32.115 25.145 ;
        RECT 32.285 24.435 32.805 24.975 ;
        RECT 32.975 24.605 33.495 25.145 ;
        RECT 33.665 24.435 34.185 24.975 ;
        RECT 34.355 24.605 34.875 25.145 ;
        RECT 35.045 24.435 35.565 24.975 ;
        RECT 35.735 24.605 36.255 25.145 ;
        RECT 36.425 24.435 36.945 24.975 ;
        RECT 37.115 24.605 37.635 25.145 ;
        RECT 37.805 24.435 38.325 24.975 ;
        RECT 38.495 24.605 39.015 25.145 ;
        RECT 39.185 24.435 39.705 24.975 ;
        RECT 39.875 24.605 40.395 25.145 ;
        RECT 41.025 25.070 41.315 26.235 ;
        RECT 41.485 25.145 42.695 26.235 ;
        RECT 41.485 24.435 42.005 24.975 ;
        RECT 42.175 24.605 42.695 25.145 ;
        RECT 43.325 25.145 44.535 26.235 ;
        RECT 43.325 24.605 43.845 25.145 ;
        RECT 44.015 24.435 44.535 24.975 ;
        RECT 15.265 23.685 15.555 24.410 ;
        RECT 15.725 23.685 16.935 24.435 ;
        RECT 17.105 23.685 18.315 24.435 ;
        RECT 18.485 23.685 19.695 24.435 ;
        RECT 19.865 23.685 21.075 24.435 ;
        RECT 21.245 23.685 22.455 24.435 ;
        RECT 22.625 23.685 23.835 24.435 ;
        RECT 24.005 23.685 25.215 24.435 ;
        RECT 25.385 23.685 26.595 24.435 ;
        RECT 26.765 23.685 27.975 24.435 ;
        RECT 28.145 23.685 29.355 24.435 ;
        RECT 29.525 23.685 30.735 24.435 ;
        RECT 30.905 23.685 32.115 24.435 ;
        RECT 32.285 23.685 33.495 24.435 ;
        RECT 33.665 23.685 34.875 24.435 ;
        RECT 35.045 23.685 36.255 24.435 ;
        RECT 36.425 23.685 37.635 24.435 ;
        RECT 37.805 23.685 39.015 24.435 ;
        RECT 39.185 23.685 40.395 24.435 ;
        RECT 41.025 23.685 41.315 24.410 ;
        RECT 41.485 23.685 42.695 24.435 ;
        RECT 43.325 23.685 44.535 24.435 ;
        RECT 2.300 23.515 44.620 23.685 ;
        RECT 2.385 22.765 3.595 23.515 ;
        RECT 3.765 22.765 4.975 23.515 ;
        RECT 5.145 22.765 6.355 23.515 ;
        RECT 6.525 22.765 7.735 23.515 ;
        RECT 7.905 22.765 9.115 23.515 ;
        RECT 2.385 22.225 2.905 22.765 ;
        RECT 3.075 22.055 3.595 22.595 ;
        RECT 3.765 22.225 4.285 22.765 ;
        RECT 4.455 22.055 4.975 22.595 ;
        RECT 5.145 22.225 5.665 22.765 ;
        RECT 5.835 22.055 6.355 22.595 ;
        RECT 6.525 22.225 7.045 22.765 ;
        RECT 7.215 22.055 7.735 22.595 ;
        RECT 7.905 22.225 8.425 22.765 ;
        RECT 9.345 22.695 9.555 23.515 ;
        RECT 9.725 22.715 10.055 23.345 ;
        RECT 8.595 22.055 9.115 22.595 ;
        RECT 9.725 22.115 9.975 22.715 ;
        RECT 10.225 22.695 10.455 23.515 ;
        RECT 10.665 22.765 11.875 23.515 ;
        RECT 12.045 22.765 13.255 23.515 ;
        RECT 13.425 22.765 14.635 23.515 ;
        RECT 14.805 22.765 16.015 23.515 ;
        RECT 17.220 22.885 17.505 23.345 ;
        RECT 17.675 23.055 17.945 23.515 ;
        RECT 10.145 22.275 10.475 22.525 ;
        RECT 10.665 22.225 11.185 22.765 ;
        RECT 2.385 20.965 3.595 22.055 ;
        RECT 3.765 20.965 4.975 22.055 ;
        RECT 5.145 20.965 6.355 22.055 ;
        RECT 6.525 20.965 7.735 22.055 ;
        RECT 7.905 20.965 9.115 22.055 ;
        RECT 9.345 20.965 9.555 22.105 ;
        RECT 9.725 21.135 10.055 22.115 ;
        RECT 10.225 20.965 10.455 22.105 ;
        RECT 11.355 22.055 11.875 22.595 ;
        RECT 12.045 22.225 12.565 22.765 ;
        RECT 12.735 22.055 13.255 22.595 ;
        RECT 13.425 22.225 13.945 22.765 ;
        RECT 14.115 22.055 14.635 22.595 ;
        RECT 14.805 22.225 15.325 22.765 ;
        RECT 17.220 22.715 18.175 22.885 ;
        RECT 15.495 22.055 16.015 22.595 ;
        RECT 10.665 20.965 11.875 22.055 ;
        RECT 12.045 20.965 13.255 22.055 ;
        RECT 13.425 20.965 14.635 22.055 ;
        RECT 14.805 20.965 16.015 22.055 ;
        RECT 17.105 21.985 17.795 22.545 ;
        RECT 17.965 21.815 18.175 22.715 ;
        RECT 17.220 21.595 18.175 21.815 ;
        RECT 18.345 22.545 18.745 23.345 ;
        RECT 18.935 22.885 19.215 23.345 ;
        RECT 19.735 23.055 20.060 23.515 ;
        RECT 18.935 22.715 20.060 22.885 ;
        RECT 20.230 22.775 20.615 23.345 ;
        RECT 19.610 22.605 20.060 22.715 ;
        RECT 18.345 21.985 19.440 22.545 ;
        RECT 19.610 22.275 20.165 22.605 ;
        RECT 17.220 21.135 17.505 21.595 ;
        RECT 17.675 20.965 17.945 21.425 ;
        RECT 18.345 21.135 18.745 21.985 ;
        RECT 19.610 21.815 20.060 22.275 ;
        RECT 20.335 22.105 20.615 22.775 ;
        RECT 20.900 22.885 21.185 23.345 ;
        RECT 21.355 23.055 21.625 23.515 ;
        RECT 20.900 22.715 21.855 22.885 ;
        RECT 18.935 21.595 20.060 21.815 ;
        RECT 18.935 21.135 19.215 21.595 ;
        RECT 19.735 20.965 20.060 21.425 ;
        RECT 20.230 21.135 20.615 22.105 ;
        RECT 20.785 21.985 21.475 22.545 ;
        RECT 21.645 21.815 21.855 22.715 ;
        RECT 20.900 21.595 21.855 21.815 ;
        RECT 22.025 22.545 22.425 23.345 ;
        RECT 22.615 22.885 22.895 23.345 ;
        RECT 23.415 23.055 23.740 23.515 ;
        RECT 22.615 22.715 23.740 22.885 ;
        RECT 23.910 22.775 24.295 23.345 ;
        RECT 23.290 22.605 23.740 22.715 ;
        RECT 22.025 21.985 23.120 22.545 ;
        RECT 23.290 22.275 23.845 22.605 ;
        RECT 20.900 21.135 21.185 21.595 ;
        RECT 21.355 20.965 21.625 21.425 ;
        RECT 22.025 21.135 22.425 21.985 ;
        RECT 23.290 21.815 23.740 22.275 ;
        RECT 24.015 22.105 24.295 22.775 ;
        RECT 24.580 22.885 24.865 23.345 ;
        RECT 25.035 23.055 25.305 23.515 ;
        RECT 24.580 22.715 25.535 22.885 ;
        RECT 22.615 21.595 23.740 21.815 ;
        RECT 22.615 21.135 22.895 21.595 ;
        RECT 23.415 20.965 23.740 21.425 ;
        RECT 23.910 21.135 24.295 22.105 ;
        RECT 24.465 21.985 25.155 22.545 ;
        RECT 25.325 21.815 25.535 22.715 ;
        RECT 24.580 21.595 25.535 21.815 ;
        RECT 25.705 22.545 26.105 23.345 ;
        RECT 26.295 22.885 26.575 23.345 ;
        RECT 27.095 23.055 27.420 23.515 ;
        RECT 26.295 22.715 27.420 22.885 ;
        RECT 27.590 22.775 27.975 23.345 ;
        RECT 28.145 22.790 28.435 23.515 ;
        RECT 28.720 22.885 29.005 23.345 ;
        RECT 29.175 23.055 29.445 23.515 ;
        RECT 26.970 22.605 27.420 22.715 ;
        RECT 25.705 21.985 26.800 22.545 ;
        RECT 26.970 22.275 27.525 22.605 ;
        RECT 24.580 21.135 24.865 21.595 ;
        RECT 25.035 20.965 25.305 21.425 ;
        RECT 25.705 21.135 26.105 21.985 ;
        RECT 26.970 21.815 27.420 22.275 ;
        RECT 27.695 22.105 27.975 22.775 ;
        RECT 28.720 22.715 29.675 22.885 ;
        RECT 26.295 21.595 27.420 21.815 ;
        RECT 26.295 21.135 26.575 21.595 ;
        RECT 27.095 20.965 27.420 21.425 ;
        RECT 27.590 21.135 27.975 22.105 ;
        RECT 28.145 20.965 28.435 22.130 ;
        RECT 28.605 21.985 29.295 22.545 ;
        RECT 29.465 21.815 29.675 22.715 ;
        RECT 28.720 21.595 29.675 21.815 ;
        RECT 29.845 22.545 30.245 23.345 ;
        RECT 30.435 22.885 30.715 23.345 ;
        RECT 31.235 23.055 31.560 23.515 ;
        RECT 30.435 22.715 31.560 22.885 ;
        RECT 31.730 22.775 32.115 23.345 ;
        RECT 31.110 22.605 31.560 22.715 ;
        RECT 29.845 21.985 30.940 22.545 ;
        RECT 31.110 22.275 31.665 22.605 ;
        RECT 28.720 21.135 29.005 21.595 ;
        RECT 29.175 20.965 29.445 21.425 ;
        RECT 29.845 21.135 30.245 21.985 ;
        RECT 31.110 21.815 31.560 22.275 ;
        RECT 31.835 22.105 32.115 22.775 ;
        RECT 30.435 21.595 31.560 21.815 ;
        RECT 30.435 21.135 30.715 21.595 ;
        RECT 31.235 20.965 31.560 21.425 ;
        RECT 31.730 21.135 32.115 22.105 ;
        RECT 32.285 22.775 32.670 23.345 ;
        RECT 32.840 23.055 33.165 23.515 ;
        RECT 33.685 22.885 33.965 23.345 ;
        RECT 32.285 22.105 32.565 22.775 ;
        RECT 32.840 22.715 33.965 22.885 ;
        RECT 32.840 22.605 33.290 22.715 ;
        RECT 32.735 22.275 33.290 22.605 ;
        RECT 34.155 22.545 34.555 23.345 ;
        RECT 34.955 23.055 35.225 23.515 ;
        RECT 35.395 22.885 35.680 23.345 ;
        RECT 32.285 21.135 32.670 22.105 ;
        RECT 32.840 21.815 33.290 22.275 ;
        RECT 33.460 21.985 34.555 22.545 ;
        RECT 32.840 21.595 33.965 21.815 ;
        RECT 32.840 20.965 33.165 21.425 ;
        RECT 33.685 21.135 33.965 21.595 ;
        RECT 34.155 21.135 34.555 21.985 ;
        RECT 34.725 22.715 35.680 22.885 ;
        RECT 35.965 22.765 37.175 23.515 ;
        RECT 37.345 22.765 38.555 23.515 ;
        RECT 38.725 22.765 39.935 23.515 ;
        RECT 40.105 22.765 41.315 23.515 ;
        RECT 41.485 22.765 42.695 23.515 ;
        RECT 43.325 22.765 44.535 23.515 ;
        RECT 34.725 21.815 34.935 22.715 ;
        RECT 35.105 21.985 35.795 22.545 ;
        RECT 35.965 22.225 36.485 22.765 ;
        RECT 36.655 22.055 37.175 22.595 ;
        RECT 37.345 22.225 37.865 22.765 ;
        RECT 38.035 22.055 38.555 22.595 ;
        RECT 38.725 22.225 39.245 22.765 ;
        RECT 39.415 22.055 39.935 22.595 ;
        RECT 40.105 22.225 40.625 22.765 ;
        RECT 40.795 22.055 41.315 22.595 ;
        RECT 41.485 22.225 42.005 22.765 ;
        RECT 42.175 22.055 42.695 22.595 ;
        RECT 34.725 21.595 35.680 21.815 ;
        RECT 34.955 20.965 35.225 21.425 ;
        RECT 35.395 21.135 35.680 21.595 ;
        RECT 35.965 20.965 37.175 22.055 ;
        RECT 37.345 20.965 38.555 22.055 ;
        RECT 38.725 20.965 39.935 22.055 ;
        RECT 40.105 20.965 41.315 22.055 ;
        RECT 41.485 20.965 42.695 22.055 ;
        RECT 43.325 22.055 43.845 22.595 ;
        RECT 44.015 22.225 44.535 22.765 ;
        RECT 43.325 20.965 44.535 22.055 ;
        RECT 2.300 20.795 44.620 20.965 ;
        RECT 2.385 19.705 3.595 20.795 ;
        RECT 3.765 19.705 4.975 20.795 ;
        RECT 5.145 19.705 6.355 20.795 ;
        RECT 6.525 19.705 7.735 20.795 ;
        RECT 2.385 18.995 2.905 19.535 ;
        RECT 3.075 19.165 3.595 19.705 ;
        RECT 3.765 18.995 4.285 19.535 ;
        RECT 4.455 19.165 4.975 19.705 ;
        RECT 5.145 18.995 5.665 19.535 ;
        RECT 5.835 19.165 6.355 19.705 ;
        RECT 6.525 18.995 7.045 19.535 ;
        RECT 7.215 19.165 7.735 19.705 ;
        RECT 8.885 19.655 9.095 20.795 ;
        RECT 9.265 19.645 9.595 20.625 ;
        RECT 9.765 19.655 9.995 20.795 ;
        RECT 10.205 19.705 11.415 20.795 ;
        RECT 11.585 19.705 12.795 20.795 ;
        RECT 12.965 19.705 14.175 20.795 ;
        RECT 2.385 18.245 3.595 18.995 ;
        RECT 3.765 18.245 4.975 18.995 ;
        RECT 5.145 18.245 6.355 18.995 ;
        RECT 6.525 18.245 7.735 18.995 ;
        RECT 8.885 18.245 9.095 19.065 ;
        RECT 9.265 19.045 9.515 19.645 ;
        RECT 9.685 19.235 10.015 19.485 ;
        RECT 9.265 18.415 9.595 19.045 ;
        RECT 9.765 18.245 9.995 19.065 ;
        RECT 10.205 18.995 10.725 19.535 ;
        RECT 10.895 19.165 11.415 19.705 ;
        RECT 11.585 18.995 12.105 19.535 ;
        RECT 12.275 19.165 12.795 19.705 ;
        RECT 12.965 18.995 13.485 19.535 ;
        RECT 13.655 19.165 14.175 19.705 ;
        RECT 15.265 19.630 15.555 20.795 ;
        RECT 15.725 19.655 16.110 20.625 ;
        RECT 16.280 20.335 16.605 20.795 ;
        RECT 17.125 20.165 17.405 20.625 ;
        RECT 16.280 19.945 17.405 20.165 ;
        RECT 10.205 18.245 11.415 18.995 ;
        RECT 11.585 18.245 12.795 18.995 ;
        RECT 12.965 18.245 14.175 18.995 ;
        RECT 15.725 18.985 16.005 19.655 ;
        RECT 16.280 19.485 16.730 19.945 ;
        RECT 17.595 19.775 17.995 20.625 ;
        RECT 18.395 20.335 18.665 20.795 ;
        RECT 18.835 20.165 19.120 20.625 ;
        RECT 16.175 19.155 16.730 19.485 ;
        RECT 16.900 19.215 17.995 19.775 ;
        RECT 16.280 19.045 16.730 19.155 ;
        RECT 15.265 18.245 15.555 18.970 ;
        RECT 15.725 18.415 16.110 18.985 ;
        RECT 16.280 18.875 17.405 19.045 ;
        RECT 16.280 18.245 16.605 18.705 ;
        RECT 17.125 18.415 17.405 18.875 ;
        RECT 17.595 18.415 17.995 19.215 ;
        RECT 18.165 19.945 19.120 20.165 ;
        RECT 18.165 19.045 18.375 19.945 ;
        RECT 18.545 19.215 19.235 19.775 ;
        RECT 19.405 19.705 20.615 20.795 ;
        RECT 20.785 19.705 21.995 20.795 ;
        RECT 18.165 18.875 19.120 19.045 ;
        RECT 18.395 18.245 18.665 18.705 ;
        RECT 18.835 18.415 19.120 18.875 ;
        RECT 19.405 18.995 19.925 19.535 ;
        RECT 20.095 19.165 20.615 19.705 ;
        RECT 20.785 18.995 21.305 19.535 ;
        RECT 21.475 19.165 21.995 19.705 ;
        RECT 22.225 19.655 22.435 20.795 ;
        RECT 22.605 19.645 22.935 20.625 ;
        RECT 23.105 19.655 23.335 20.795 ;
        RECT 23.545 19.705 24.755 20.795 ;
        RECT 24.925 19.705 26.135 20.795 ;
        RECT 26.305 19.705 27.515 20.795 ;
        RECT 27.685 19.705 28.895 20.795 ;
        RECT 29.065 19.705 30.275 20.795 ;
        RECT 30.445 19.705 31.655 20.795 ;
        RECT 32.400 20.165 32.685 20.625 ;
        RECT 32.855 20.335 33.125 20.795 ;
        RECT 32.400 19.945 33.355 20.165 ;
        RECT 19.405 18.245 20.615 18.995 ;
        RECT 20.785 18.245 21.995 18.995 ;
        RECT 22.225 18.245 22.435 19.065 ;
        RECT 22.605 19.045 22.855 19.645 ;
        RECT 23.025 19.235 23.355 19.485 ;
        RECT 22.605 18.415 22.935 19.045 ;
        RECT 23.105 18.245 23.335 19.065 ;
        RECT 23.545 18.995 24.065 19.535 ;
        RECT 24.235 19.165 24.755 19.705 ;
        RECT 24.925 18.995 25.445 19.535 ;
        RECT 25.615 19.165 26.135 19.705 ;
        RECT 26.305 18.995 26.825 19.535 ;
        RECT 26.995 19.165 27.515 19.705 ;
        RECT 27.685 18.995 28.205 19.535 ;
        RECT 28.375 19.165 28.895 19.705 ;
        RECT 29.065 18.995 29.585 19.535 ;
        RECT 29.755 19.165 30.275 19.705 ;
        RECT 30.445 18.995 30.965 19.535 ;
        RECT 31.135 19.165 31.655 19.705 ;
        RECT 32.285 19.215 32.975 19.775 ;
        RECT 33.145 19.045 33.355 19.945 ;
        RECT 23.545 18.245 24.755 18.995 ;
        RECT 24.925 18.245 26.135 18.995 ;
        RECT 26.305 18.245 27.515 18.995 ;
        RECT 27.685 18.245 28.895 18.995 ;
        RECT 29.065 18.245 30.275 18.995 ;
        RECT 30.445 18.245 31.655 18.995 ;
        RECT 32.400 18.875 33.355 19.045 ;
        RECT 33.525 19.775 33.925 20.625 ;
        RECT 34.115 20.165 34.395 20.625 ;
        RECT 34.915 20.335 35.240 20.795 ;
        RECT 34.115 19.945 35.240 20.165 ;
        RECT 33.525 19.215 34.620 19.775 ;
        RECT 34.790 19.485 35.240 19.945 ;
        RECT 35.410 19.655 35.795 20.625 ;
        RECT 32.400 18.415 32.685 18.875 ;
        RECT 32.855 18.245 33.125 18.705 ;
        RECT 33.525 18.415 33.925 19.215 ;
        RECT 34.790 19.155 35.345 19.485 ;
        RECT 34.790 19.045 35.240 19.155 ;
        RECT 34.115 18.875 35.240 19.045 ;
        RECT 35.515 18.985 35.795 19.655 ;
        RECT 34.115 18.415 34.395 18.875 ;
        RECT 34.915 18.245 35.240 18.705 ;
        RECT 35.410 18.415 35.795 18.985 ;
        RECT 35.965 19.655 36.350 20.625 ;
        RECT 36.520 20.335 36.845 20.795 ;
        RECT 37.365 20.165 37.645 20.625 ;
        RECT 36.520 19.945 37.645 20.165 ;
        RECT 35.965 18.985 36.245 19.655 ;
        RECT 36.520 19.485 36.970 19.945 ;
        RECT 37.835 19.775 38.235 20.625 ;
        RECT 38.635 20.335 38.905 20.795 ;
        RECT 39.075 20.165 39.360 20.625 ;
        RECT 36.415 19.155 36.970 19.485 ;
        RECT 37.140 19.215 38.235 19.775 ;
        RECT 36.520 19.045 36.970 19.155 ;
        RECT 35.965 18.415 36.350 18.985 ;
        RECT 36.520 18.875 37.645 19.045 ;
        RECT 36.520 18.245 36.845 18.705 ;
        RECT 37.365 18.415 37.645 18.875 ;
        RECT 37.835 18.415 38.235 19.215 ;
        RECT 38.405 19.945 39.360 20.165 ;
        RECT 38.405 19.045 38.615 19.945 ;
        RECT 38.785 19.215 39.475 19.775 ;
        RECT 39.645 19.705 40.855 20.795 ;
        RECT 38.405 18.875 39.360 19.045 ;
        RECT 38.635 18.245 38.905 18.705 ;
        RECT 39.075 18.415 39.360 18.875 ;
        RECT 39.645 18.995 40.165 19.535 ;
        RECT 40.335 19.165 40.855 19.705 ;
        RECT 41.025 19.630 41.315 20.795 ;
        RECT 41.485 19.705 42.695 20.795 ;
        RECT 41.485 18.995 42.005 19.535 ;
        RECT 42.175 19.165 42.695 19.705 ;
        RECT 43.325 19.705 44.535 20.795 ;
        RECT 43.325 19.165 43.845 19.705 ;
        RECT 44.015 18.995 44.535 19.535 ;
        RECT 39.645 18.245 40.855 18.995 ;
        RECT 41.025 18.245 41.315 18.970 ;
        RECT 41.485 18.245 42.695 18.995 ;
        RECT 43.325 18.245 44.535 18.995 ;
        RECT 2.300 18.075 44.620 18.245 ;
        RECT 2.385 17.325 3.595 18.075 ;
        RECT 3.765 17.325 4.975 18.075 ;
        RECT 5.145 17.325 6.355 18.075 ;
        RECT 6.525 17.325 7.735 18.075 ;
        RECT 7.905 17.325 9.115 18.075 ;
        RECT 2.385 16.785 2.905 17.325 ;
        RECT 3.075 16.615 3.595 17.155 ;
        RECT 3.765 16.785 4.285 17.325 ;
        RECT 4.455 16.615 4.975 17.155 ;
        RECT 5.145 16.785 5.665 17.325 ;
        RECT 5.835 16.615 6.355 17.155 ;
        RECT 6.525 16.785 7.045 17.325 ;
        RECT 7.215 16.615 7.735 17.155 ;
        RECT 7.905 16.785 8.425 17.325 ;
        RECT 9.335 17.320 9.585 18.075 ;
        RECT 9.755 17.365 10.005 17.895 ;
        RECT 10.175 17.615 10.480 18.075 ;
        RECT 10.725 17.695 11.795 17.865 ;
        RECT 8.595 16.615 9.115 17.155 ;
        RECT 9.755 16.715 9.960 17.365 ;
        RECT 10.725 17.340 11.045 17.695 ;
        RECT 10.720 17.165 11.045 17.340 ;
        RECT 10.130 16.865 11.045 17.165 ;
        RECT 11.215 17.125 11.455 17.525 ;
        RECT 11.625 17.465 11.795 17.695 ;
        RECT 11.965 17.635 12.155 18.075 ;
        RECT 12.325 17.625 13.275 17.905 ;
        RECT 13.495 17.715 13.845 17.885 ;
        RECT 11.625 17.295 12.155 17.465 ;
        RECT 10.130 16.835 10.870 16.865 ;
        RECT 2.385 15.525 3.595 16.615 ;
        RECT 3.765 15.525 4.975 16.615 ;
        RECT 5.145 15.525 6.355 16.615 ;
        RECT 6.525 15.525 7.735 16.615 ;
        RECT 7.905 15.525 9.115 16.615 ;
        RECT 9.335 15.525 9.585 16.665 ;
        RECT 9.755 15.835 10.005 16.715 ;
        RECT 10.175 15.525 10.480 16.665 ;
        RECT 10.700 16.245 10.870 16.835 ;
        RECT 11.215 16.755 11.755 17.125 ;
        RECT 11.935 17.015 12.155 17.295 ;
        RECT 12.325 16.845 12.495 17.625 ;
        RECT 12.090 16.675 12.495 16.845 ;
        RECT 12.665 16.835 13.015 17.455 ;
        RECT 12.090 16.585 12.260 16.675 ;
        RECT 13.185 16.665 13.395 17.455 ;
        RECT 11.040 16.415 12.260 16.585 ;
        RECT 12.720 16.505 13.395 16.665 ;
        RECT 10.700 16.075 11.500 16.245 ;
        RECT 10.820 15.525 11.150 15.905 ;
        RECT 11.330 15.785 11.500 16.075 ;
        RECT 12.090 16.035 12.260 16.415 ;
        RECT 12.430 16.495 13.395 16.505 ;
        RECT 13.585 17.325 13.845 17.715 ;
        RECT 14.055 17.615 14.385 18.075 ;
        RECT 15.260 17.685 16.115 17.855 ;
        RECT 16.320 17.685 16.815 17.855 ;
        RECT 16.985 17.715 17.315 18.075 ;
        RECT 13.585 16.635 13.755 17.325 ;
        RECT 13.925 16.975 14.095 17.155 ;
        RECT 14.265 17.145 15.055 17.395 ;
        RECT 15.260 16.975 15.430 17.685 ;
        RECT 15.600 17.175 15.955 17.395 ;
        RECT 13.925 16.805 15.615 16.975 ;
        RECT 12.430 16.205 12.890 16.495 ;
        RECT 13.585 16.465 15.085 16.635 ;
        RECT 13.585 16.325 13.755 16.465 ;
        RECT 13.195 16.155 13.755 16.325 ;
        RECT 11.670 15.525 11.920 15.985 ;
        RECT 12.090 15.695 12.960 16.035 ;
        RECT 13.195 15.695 13.365 16.155 ;
        RECT 14.200 16.125 15.275 16.295 ;
        RECT 13.535 15.525 13.905 15.985 ;
        RECT 14.200 15.785 14.370 16.125 ;
        RECT 14.540 15.525 14.870 15.955 ;
        RECT 15.105 15.785 15.275 16.125 ;
        RECT 15.445 16.025 15.615 16.805 ;
        RECT 15.785 16.585 15.955 17.175 ;
        RECT 16.125 16.775 16.475 17.395 ;
        RECT 15.785 16.195 16.250 16.585 ;
        RECT 16.645 16.325 16.815 17.685 ;
        RECT 16.985 16.495 17.445 17.545 ;
        RECT 16.420 16.155 16.815 16.325 ;
        RECT 16.420 16.025 16.590 16.155 ;
        RECT 15.445 15.695 16.125 16.025 ;
        RECT 16.340 15.695 16.590 16.025 ;
        RECT 16.760 15.525 17.010 15.985 ;
        RECT 17.180 15.710 17.505 16.495 ;
        RECT 17.675 15.695 17.845 17.815 ;
        RECT 18.015 17.695 18.345 18.075 ;
        RECT 18.515 17.525 18.770 17.815 ;
        RECT 19.300 17.675 23.105 17.905 ;
        RECT 23.695 17.595 23.865 18.075 ;
        RECT 18.020 17.355 18.770 17.525 ;
        RECT 18.020 16.365 18.250 17.355 ;
        RECT 18.945 17.255 20.905 17.505 ;
        RECT 21.515 17.425 21.845 17.505 ;
        RECT 22.355 17.425 22.685 17.505 ;
        RECT 23.195 17.425 23.525 17.505 ;
        RECT 24.035 17.425 24.365 17.905 ;
        RECT 24.535 17.595 24.705 18.075 ;
        RECT 24.875 17.425 25.210 17.905 ;
        RECT 21.515 17.255 25.210 17.425 ;
        RECT 25.630 17.275 25.960 17.905 ;
        RECT 18.420 16.535 18.770 17.185 ;
        RECT 18.945 16.715 19.175 17.255 ;
        RECT 19.735 16.885 21.450 17.085 ;
        RECT 21.760 16.885 23.310 17.085 ;
        RECT 23.600 16.885 25.190 17.085 ;
        RECT 18.945 16.495 24.785 16.715 ;
        RECT 18.020 16.195 18.770 16.365 ;
        RECT 18.015 15.525 18.345 16.025 ;
        RECT 18.515 15.695 18.770 16.195 ;
        RECT 19.300 15.525 19.565 16.325 ;
        RECT 19.735 15.695 20.065 16.495 ;
        RECT 20.235 15.525 20.405 16.325 ;
        RECT 20.575 15.695 20.905 16.495 ;
        RECT 21.075 15.525 21.765 16.325 ;
        RECT 21.935 15.695 22.265 16.495 ;
        RECT 22.435 15.525 22.605 16.325 ;
        RECT 22.775 15.695 23.105 16.495 ;
        RECT 23.275 15.525 23.445 16.325 ;
        RECT 23.615 15.695 23.945 16.495 ;
        RECT 24.115 15.525 24.285 16.325 ;
        RECT 24.455 15.695 24.785 16.495 ;
        RECT 24.955 15.525 25.210 16.715 ;
        RECT 25.630 16.675 25.860 17.275 ;
        RECT 26.130 17.255 26.360 18.075 ;
        RECT 26.765 17.325 27.975 18.075 ;
        RECT 28.145 17.350 28.435 18.075 ;
        RECT 26.030 16.845 26.360 17.085 ;
        RECT 26.765 16.785 27.285 17.325 ;
        RECT 29.300 17.255 29.530 18.075 ;
        RECT 29.700 17.275 30.030 17.905 ;
        RECT 25.630 15.695 25.960 16.675 ;
        RECT 26.130 15.525 26.340 16.665 ;
        RECT 27.455 16.615 27.975 17.155 ;
        RECT 29.300 16.845 29.630 17.085 ;
        RECT 26.765 15.525 27.975 16.615 ;
        RECT 28.145 15.525 28.435 16.690 ;
        RECT 29.800 16.675 30.030 17.275 ;
        RECT 31.140 17.255 31.370 18.075 ;
        RECT 31.540 17.275 31.870 17.905 ;
        RECT 31.140 16.845 31.470 17.085 ;
        RECT 31.640 16.675 31.870 17.275 ;
        RECT 32.520 17.255 32.750 18.075 ;
        RECT 32.920 17.275 33.250 17.905 ;
        RECT 32.520 16.845 32.850 17.085 ;
        RECT 33.020 16.675 33.250 17.275 ;
        RECT 33.685 17.265 33.925 18.075 ;
        RECT 34.095 17.265 34.425 17.905 ;
        RECT 34.595 17.265 34.865 18.075 ;
        RECT 35.045 17.325 36.255 18.075 ;
        RECT 36.425 17.325 37.635 18.075 ;
        RECT 37.805 17.325 39.015 18.075 ;
        RECT 39.185 17.325 40.395 18.075 ;
        RECT 40.565 17.325 41.775 18.075 ;
        RECT 41.945 17.325 43.155 18.075 ;
        RECT 43.325 17.325 44.535 18.075 ;
        RECT 33.665 16.835 34.015 17.085 ;
        RECT 29.320 15.525 29.530 16.665 ;
        RECT 29.700 15.695 30.030 16.675 ;
        RECT 31.160 15.525 31.370 16.665 ;
        RECT 31.540 15.695 31.870 16.675 ;
        RECT 32.540 15.525 32.750 16.665 ;
        RECT 32.920 15.695 33.250 16.675 ;
        RECT 34.185 16.665 34.355 17.265 ;
        RECT 34.525 16.835 34.875 17.085 ;
        RECT 35.045 16.785 35.565 17.325 ;
        RECT 33.675 16.495 34.355 16.665 ;
        RECT 33.675 15.710 34.005 16.495 ;
        RECT 34.535 15.525 34.865 16.665 ;
        RECT 35.735 16.615 36.255 17.155 ;
        RECT 36.425 16.785 36.945 17.325 ;
        RECT 37.115 16.615 37.635 17.155 ;
        RECT 37.805 16.785 38.325 17.325 ;
        RECT 38.495 16.615 39.015 17.155 ;
        RECT 39.185 16.785 39.705 17.325 ;
        RECT 39.875 16.615 40.395 17.155 ;
        RECT 40.565 16.785 41.085 17.325 ;
        RECT 41.255 16.615 41.775 17.155 ;
        RECT 41.945 16.785 42.465 17.325 ;
        RECT 42.635 16.615 43.155 17.155 ;
        RECT 35.045 15.525 36.255 16.615 ;
        RECT 36.425 15.525 37.635 16.615 ;
        RECT 37.805 15.525 39.015 16.615 ;
        RECT 39.185 15.525 40.395 16.615 ;
        RECT 40.565 15.525 41.775 16.615 ;
        RECT 41.945 15.525 43.155 16.615 ;
        RECT 43.325 16.615 43.845 17.155 ;
        RECT 44.015 16.785 44.535 17.325 ;
        RECT 43.325 15.525 44.535 16.615 ;
        RECT 2.300 15.355 44.620 15.525 ;
        RECT 2.385 14.265 3.595 15.355 ;
        RECT 3.765 14.265 4.975 15.355 ;
        RECT 5.145 14.265 6.355 15.355 ;
        RECT 6.525 14.265 7.735 15.355 ;
        RECT 7.905 14.265 9.115 15.355 ;
        RECT 9.285 14.265 10.495 15.355 ;
        RECT 2.385 13.555 2.905 14.095 ;
        RECT 3.075 13.725 3.595 14.265 ;
        RECT 3.765 13.555 4.285 14.095 ;
        RECT 4.455 13.725 4.975 14.265 ;
        RECT 5.145 13.555 5.665 14.095 ;
        RECT 5.835 13.725 6.355 14.265 ;
        RECT 6.525 13.555 7.045 14.095 ;
        RECT 7.215 13.725 7.735 14.265 ;
        RECT 7.905 13.555 8.425 14.095 ;
        RECT 8.595 13.725 9.115 14.265 ;
        RECT 9.285 13.555 9.805 14.095 ;
        RECT 9.975 13.725 10.495 14.265 ;
        RECT 10.705 14.215 10.935 15.355 ;
        RECT 11.105 14.205 11.435 15.185 ;
        RECT 11.605 14.215 11.815 15.355 ;
        RECT 12.045 14.265 13.255 15.355 ;
        RECT 13.425 14.265 14.635 15.355 ;
        RECT 10.685 13.795 11.015 14.045 ;
        RECT 2.385 12.805 3.595 13.555 ;
        RECT 3.765 12.805 4.975 13.555 ;
        RECT 5.145 12.805 6.355 13.555 ;
        RECT 6.525 12.805 7.735 13.555 ;
        RECT 7.905 12.805 9.115 13.555 ;
        RECT 9.285 12.805 10.495 13.555 ;
        RECT 10.705 12.805 10.935 13.625 ;
        RECT 11.185 13.605 11.435 14.205 ;
        RECT 11.105 12.975 11.435 13.605 ;
        RECT 11.605 12.805 11.815 13.625 ;
        RECT 12.045 13.555 12.565 14.095 ;
        RECT 12.735 13.725 13.255 14.265 ;
        RECT 13.425 13.555 13.945 14.095 ;
        RECT 14.115 13.725 14.635 14.265 ;
        RECT 15.265 14.190 15.555 15.355 ;
        RECT 15.725 14.265 16.935 15.355 ;
        RECT 17.105 14.265 18.315 15.355 ;
        RECT 18.485 14.265 19.695 15.355 ;
        RECT 15.725 13.555 16.245 14.095 ;
        RECT 16.415 13.725 16.935 14.265 ;
        RECT 17.105 13.555 17.625 14.095 ;
        RECT 17.795 13.725 18.315 14.265 ;
        RECT 18.485 13.555 19.005 14.095 ;
        RECT 19.175 13.725 19.695 14.265 ;
        RECT 21.040 14.215 21.250 15.355 ;
        RECT 21.420 14.205 21.750 15.185 ;
        RECT 22.260 14.935 24.195 15.185 ;
        RECT 24.365 14.995 24.695 15.355 ;
        RECT 22.260 14.515 22.455 14.935 ;
        RECT 23.035 14.925 24.195 14.935 ;
        RECT 23.995 14.825 24.195 14.925 ;
        RECT 24.865 14.825 25.055 15.185 ;
        RECT 25.225 14.995 25.555 15.355 ;
        RECT 25.725 14.825 25.915 15.185 ;
        RECT 26.085 14.995 26.415 15.355 ;
        RECT 26.585 14.825 26.765 15.185 ;
        RECT 26.945 14.995 27.275 15.355 ;
        RECT 27.445 14.825 27.705 15.185 ;
        RECT 22.660 14.425 23.825 14.755 ;
        RECT 23.995 14.595 27.705 14.825 ;
        RECT 22.660 14.305 23.960 14.425 ;
        RECT 21.020 13.795 21.350 14.035 ;
        RECT 12.045 12.805 13.255 13.555 ;
        RECT 13.425 12.805 14.635 13.555 ;
        RECT 15.265 12.805 15.555 13.530 ;
        RECT 15.725 12.805 16.935 13.555 ;
        RECT 17.105 12.805 18.315 13.555 ;
        RECT 18.485 12.805 19.695 13.555 ;
        RECT 21.020 12.805 21.250 13.625 ;
        RECT 21.520 13.605 21.750 14.205 ;
        RECT 22.170 13.755 23.510 14.135 ;
        RECT 22.170 13.715 22.480 13.755 ;
        RECT 21.420 12.975 21.750 13.605 ;
        RECT 23.680 13.615 23.960 14.305 ;
        RECT 24.130 14.200 27.550 14.425 ;
        RECT 24.130 13.785 24.475 14.200 ;
        RECT 24.645 13.785 26.080 14.030 ;
        RECT 26.305 13.795 27.550 14.200 ;
        RECT 28.145 14.190 28.435 15.355 ;
        RECT 28.605 14.265 29.815 15.355 ;
        RECT 29.985 14.265 31.195 15.355 ;
        RECT 23.680 13.585 25.985 13.615 ;
        RECT 22.170 12.805 22.505 13.525 ;
        RECT 22.675 13.415 25.985 13.585 ;
        RECT 22.675 13.335 23.725 13.415 ;
        RECT 24.355 13.395 25.985 13.415 ;
        RECT 26.155 13.455 27.275 13.625 ;
        RECT 22.675 13.090 22.865 13.335 ;
        RECT 23.035 12.805 23.365 13.165 ;
        RECT 23.535 12.975 23.725 13.335 ;
        RECT 23.915 12.805 24.195 13.245 ;
        RECT 26.155 13.225 26.415 13.455 ;
        RECT 24.365 12.975 26.415 13.225 ;
        RECT 26.585 12.805 26.775 13.285 ;
        RECT 26.945 12.975 27.275 13.455 ;
        RECT 27.445 12.805 27.705 13.605 ;
        RECT 28.605 13.555 29.125 14.095 ;
        RECT 29.295 13.725 29.815 14.265 ;
        RECT 29.985 13.555 30.505 14.095 ;
        RECT 30.675 13.725 31.195 14.265 ;
        RECT 32.295 14.385 32.625 15.170 ;
        RECT 32.295 14.215 32.975 14.385 ;
        RECT 33.155 14.215 33.485 15.355 ;
        RECT 33.665 14.265 34.875 15.355 ;
        RECT 35.045 14.265 36.255 15.355 ;
        RECT 36.425 14.265 37.635 15.355 ;
        RECT 37.805 14.265 39.015 15.355 ;
        RECT 39.185 14.265 40.395 15.355 ;
        RECT 32.285 13.795 32.635 14.045 ;
        RECT 32.805 13.615 32.975 14.215 ;
        RECT 33.145 13.795 33.495 14.045 ;
        RECT 28.145 12.805 28.435 13.530 ;
        RECT 28.605 12.805 29.815 13.555 ;
        RECT 29.985 12.805 31.195 13.555 ;
        RECT 32.305 12.805 32.545 13.615 ;
        RECT 32.715 12.975 33.045 13.615 ;
        RECT 33.215 12.805 33.485 13.615 ;
        RECT 33.665 13.555 34.185 14.095 ;
        RECT 34.355 13.725 34.875 14.265 ;
        RECT 35.045 13.555 35.565 14.095 ;
        RECT 35.735 13.725 36.255 14.265 ;
        RECT 36.425 13.555 36.945 14.095 ;
        RECT 37.115 13.725 37.635 14.265 ;
        RECT 37.805 13.555 38.325 14.095 ;
        RECT 38.495 13.725 39.015 14.265 ;
        RECT 39.185 13.555 39.705 14.095 ;
        RECT 39.875 13.725 40.395 14.265 ;
        RECT 41.025 14.190 41.315 15.355 ;
        RECT 41.485 14.265 42.695 15.355 ;
        RECT 41.485 13.555 42.005 14.095 ;
        RECT 42.175 13.725 42.695 14.265 ;
        RECT 43.325 14.265 44.535 15.355 ;
        RECT 43.325 13.725 43.845 14.265 ;
        RECT 44.015 13.555 44.535 14.095 ;
        RECT 33.665 12.805 34.875 13.555 ;
        RECT 35.045 12.805 36.255 13.555 ;
        RECT 36.425 12.805 37.635 13.555 ;
        RECT 37.805 12.805 39.015 13.555 ;
        RECT 39.185 12.805 40.395 13.555 ;
        RECT 41.025 12.805 41.315 13.530 ;
        RECT 41.485 12.805 42.695 13.555 ;
        RECT 43.325 12.805 44.535 13.555 ;
        RECT 2.300 12.635 44.620 12.805 ;
        RECT 20.160 7.980 28.295 8.150 ;
        RECT 20.160 6.260 20.330 7.980 ;
        RECT 20.940 7.520 21.270 7.690 ;
        RECT 21.020 5.720 21.190 7.300 ;
        RECT 21.880 6.260 22.050 7.980 ;
        RECT 22.400 6.260 22.570 7.980 ;
        RECT 24.880 7.520 25.210 7.690 ;
        RECT 24.960 5.720 25.130 7.300 ;
        RECT 27.520 6.260 27.690 7.980 ;
        RECT 28.125 6.260 28.295 7.980 ;
        RECT 20.110 5.550 28.030 5.720 ;
        RECT 19.760 0.570 19.930 5.320 ;
        RECT 24.110 0.570 24.280 5.320 ;
        RECT 24.715 0.570 24.885 5.320 ;
        RECT 19.760 0.400 24.885 0.570 ;
      LAYER met1 ;
        RECT 2.300 53.280 44.620 53.760 ;
        RECT 5.590 52.060 5.910 52.120 ;
        RECT 6.985 52.060 7.275 52.105 ;
        RECT 5.590 51.920 7.275 52.060 ;
        RECT 5.590 51.860 5.910 51.920 ;
        RECT 6.985 51.875 7.275 51.920 ;
        RECT 6.050 51.380 6.370 51.440 ;
        RECT 6.525 51.380 6.815 51.425 ;
        RECT 6.050 51.240 6.815 51.380 ;
        RECT 6.050 51.180 6.370 51.240 ;
        RECT 6.525 51.195 6.815 51.240 ;
        RECT 29.050 51.380 29.370 51.440 ;
        RECT 29.525 51.380 29.815 51.425 ;
        RECT 29.050 51.240 29.815 51.380 ;
        RECT 29.050 51.180 29.370 51.240 ;
        RECT 29.525 51.195 29.815 51.240 ;
        RECT 2.300 50.560 44.620 51.040 ;
        RECT 9.270 50.360 9.590 50.420 ;
        RECT 9.270 50.220 15.480 50.360 ;
        RECT 9.270 50.160 9.590 50.220 ;
        RECT 6.050 49.820 6.370 50.080 ;
        RECT 8.345 50.020 8.995 50.065 ;
        RECT 11.945 50.020 12.235 50.065 ;
        RECT 8.345 49.880 12.235 50.020 ;
        RECT 8.345 49.835 8.995 49.880 ;
        RECT 11.645 49.835 12.235 49.880 ;
        RECT 11.645 49.740 11.935 49.835 ;
        RECT 5.150 49.680 5.440 49.725 ;
        RECT 6.985 49.680 7.275 49.725 ;
        RECT 10.565 49.680 10.855 49.725 ;
        RECT 5.150 49.540 10.855 49.680 ;
        RECT 5.150 49.495 5.440 49.540 ;
        RECT 6.985 49.495 7.275 49.540 ;
        RECT 10.565 49.495 10.855 49.540 ;
        RECT 11.570 49.520 11.935 49.740 ;
        RECT 12.950 49.680 13.270 49.740 ;
        RECT 15.340 49.725 15.480 50.220 ;
        RECT 29.050 50.160 29.370 50.420 ;
        RECT 33.190 50.360 33.510 50.420 ;
        RECT 37.345 50.360 37.635 50.405 ;
        RECT 33.190 50.220 37.635 50.360 ;
        RECT 33.190 50.160 33.510 50.220 ;
        RECT 37.345 50.175 37.635 50.220 ;
        RECT 17.550 50.020 17.870 50.080 ;
        RECT 15.800 49.880 17.870 50.020 ;
        RECT 29.140 50.020 29.280 50.160 ;
        RECT 32.270 50.065 32.590 50.080 ;
        RECT 29.985 50.020 30.275 50.065 ;
        RECT 29.140 49.880 30.275 50.020 ;
        RECT 15.800 49.725 15.940 49.880 ;
        RECT 17.550 49.820 17.870 49.880 ;
        RECT 29.985 49.835 30.275 49.880 ;
        RECT 32.265 50.020 32.915 50.065 ;
        RECT 35.865 50.020 36.155 50.065 ;
        RECT 32.265 49.880 36.155 50.020 ;
        RECT 32.265 49.835 32.915 49.880 ;
        RECT 35.565 49.835 36.155 49.880 ;
        RECT 32.270 49.820 32.590 49.835 ;
        RECT 14.345 49.680 14.635 49.725 ;
        RECT 12.950 49.540 14.635 49.680 ;
        RECT 11.570 49.480 11.890 49.520 ;
        RECT 12.950 49.480 13.270 49.540 ;
        RECT 14.345 49.495 14.635 49.540 ;
        RECT 15.265 49.495 15.555 49.725 ;
        RECT 15.725 49.495 16.015 49.725 ;
        RECT 16.170 49.680 16.490 49.740 ;
        RECT 29.070 49.680 29.360 49.725 ;
        RECT 30.905 49.680 31.195 49.725 ;
        RECT 34.485 49.680 34.775 49.725 ;
        RECT 16.170 49.540 16.685 49.680 ;
        RECT 29.070 49.540 34.775 49.680 ;
        RECT 16.170 49.480 16.490 49.540 ;
        RECT 29.070 49.495 29.360 49.540 ;
        RECT 30.905 49.495 31.195 49.540 ;
        RECT 34.485 49.495 34.775 49.540 ;
        RECT 35.565 49.520 35.855 49.835 ;
        RECT 4.670 49.140 4.990 49.400 ;
        RECT 6.050 49.340 6.370 49.400 ;
        RECT 13.425 49.340 13.715 49.385 ;
        RECT 6.050 49.200 13.715 49.340 ;
        RECT 6.050 49.140 6.370 49.200 ;
        RECT 13.425 49.155 13.715 49.200 ;
        RECT 24.005 49.340 24.295 49.385 ;
        RECT 24.450 49.340 24.770 49.400 ;
        RECT 24.005 49.200 24.770 49.340 ;
        RECT 24.005 49.155 24.295 49.200 ;
        RECT 24.450 49.140 24.770 49.200 ;
        RECT 28.130 49.340 28.450 49.400 ;
        RECT 28.605 49.340 28.895 49.385 ;
        RECT 28.130 49.200 28.895 49.340 ;
        RECT 28.130 49.140 28.450 49.200 ;
        RECT 28.605 49.155 28.895 49.200 ;
        RECT 5.555 49.000 5.845 49.045 ;
        RECT 7.445 49.000 7.735 49.045 ;
        RECT 10.565 49.000 10.855 49.045 ;
        RECT 5.555 48.860 10.855 49.000 ;
        RECT 5.555 48.815 5.845 48.860 ;
        RECT 7.445 48.815 7.735 48.860 ;
        RECT 10.565 48.815 10.855 48.860 ;
        RECT 11.570 49.000 11.890 49.060 ;
        RECT 17.565 49.000 17.855 49.045 ;
        RECT 20.310 49.000 20.630 49.060 ;
        RECT 11.570 48.860 20.630 49.000 ;
        RECT 11.570 48.800 11.890 48.860 ;
        RECT 17.565 48.815 17.855 48.860 ;
        RECT 20.310 48.800 20.630 48.860 ;
        RECT 29.475 49.000 29.765 49.045 ;
        RECT 31.365 49.000 31.655 49.045 ;
        RECT 34.485 49.000 34.775 49.045 ;
        RECT 29.475 48.860 34.775 49.000 ;
        RECT 29.475 48.815 29.765 48.860 ;
        RECT 31.365 48.815 31.655 48.860 ;
        RECT 34.485 48.815 34.775 48.860 ;
        RECT 2.300 47.840 44.620 48.320 ;
        RECT 4.670 47.640 4.990 47.700 ;
        RECT 5.605 47.640 5.895 47.685 ;
        RECT 4.670 47.500 5.895 47.640 ;
        RECT 4.670 47.440 4.990 47.500 ;
        RECT 5.605 47.455 5.895 47.500 ;
        RECT 12.950 47.440 13.270 47.700 ;
        RECT 17.105 47.640 17.395 47.685 ;
        RECT 18.025 47.640 18.315 47.685 ;
        RECT 17.105 47.500 18.315 47.640 ;
        RECT 17.105 47.455 17.395 47.500 ;
        RECT 18.025 47.455 18.315 47.500 ;
        RECT 31.810 47.440 32.130 47.700 ;
        RECT 23.955 47.300 24.245 47.345 ;
        RECT 25.845 47.300 26.135 47.345 ;
        RECT 28.965 47.300 29.255 47.345 ;
        RECT 23.955 47.160 29.255 47.300 ;
        RECT 23.955 47.115 24.245 47.160 ;
        RECT 25.845 47.115 26.135 47.160 ;
        RECT 28.965 47.115 29.255 47.160 ;
        RECT 24.450 46.760 24.770 47.020 ;
        RECT 4.685 46.620 4.975 46.665 ;
        RECT 5.590 46.620 5.910 46.680 ;
        RECT 4.685 46.480 5.910 46.620 ;
        RECT 4.685 46.435 4.975 46.480 ;
        RECT 5.590 46.420 5.910 46.480 ;
        RECT 6.065 46.620 6.355 46.665 ;
        RECT 6.510 46.620 6.830 46.680 ;
        RECT 6.065 46.480 6.830 46.620 ;
        RECT 6.065 46.435 6.355 46.480 ;
        RECT 6.510 46.420 6.830 46.480 ;
        RECT 7.445 46.620 7.735 46.665 ;
        RECT 8.350 46.620 8.670 46.680 ;
        RECT 7.445 46.480 8.670 46.620 ;
        RECT 7.445 46.435 7.735 46.480 ;
        RECT 8.350 46.420 8.670 46.480 ;
        RECT 12.030 46.620 12.350 46.680 ;
        RECT 12.505 46.620 12.795 46.665 ;
        RECT 12.030 46.480 12.795 46.620 ;
        RECT 12.030 46.420 12.350 46.480 ;
        RECT 12.505 46.435 12.795 46.480 ;
        RECT 16.170 46.620 16.490 46.680 ;
        RECT 18.040 46.665 18.300 46.710 ;
        RECT 17.565 46.620 17.855 46.665 ;
        RECT 16.170 46.480 17.855 46.620 ;
        RECT 16.170 46.420 16.490 46.480 ;
        RECT 17.565 46.435 17.855 46.480 ;
        RECT 18.025 46.620 18.315 46.665 ;
        RECT 20.785 46.620 21.075 46.665 ;
        RECT 18.025 46.480 21.075 46.620 ;
        RECT 18.025 46.435 18.315 46.480 ;
        RECT 20.785 46.435 21.075 46.480 ;
        RECT 18.040 46.390 18.300 46.435 ;
        RECT 23.070 46.420 23.390 46.680 ;
        RECT 23.550 46.620 23.840 46.665 ;
        RECT 25.385 46.620 25.675 46.665 ;
        RECT 28.965 46.620 29.255 46.665 ;
        RECT 23.550 46.480 29.255 46.620 ;
        RECT 23.550 46.435 23.840 46.480 ;
        RECT 25.385 46.435 25.675 46.480 ;
        RECT 28.965 46.435 29.255 46.480 ;
        RECT 21.230 46.080 21.550 46.340 ;
        RECT 30.045 46.325 30.335 46.640 ;
        RECT 33.665 46.620 33.955 46.665 ;
        RECT 34.570 46.620 34.890 46.680 ;
        RECT 33.665 46.480 34.890 46.620 ;
        RECT 33.665 46.435 33.955 46.480 ;
        RECT 34.570 46.420 34.890 46.480 ;
        RECT 35.490 46.620 35.810 46.680 ;
        RECT 35.965 46.620 36.255 46.665 ;
        RECT 35.490 46.480 36.255 46.620 ;
        RECT 35.490 46.420 35.810 46.480 ;
        RECT 35.965 46.435 36.255 46.480 ;
        RECT 26.745 46.280 27.395 46.325 ;
        RECT 30.045 46.280 30.635 46.325 ;
        RECT 32.270 46.280 32.590 46.340 ;
        RECT 26.380 46.140 32.590 46.280 ;
        RECT 4.210 45.740 4.530 46.000 ;
        RECT 6.510 45.940 6.830 46.000 ;
        RECT 6.985 45.940 7.275 45.985 ;
        RECT 6.510 45.800 7.275 45.940 ;
        RECT 6.510 45.740 6.830 45.800 ;
        RECT 6.985 45.755 7.275 45.800 ;
        RECT 20.310 45.940 20.630 46.000 ;
        RECT 26.380 45.940 26.520 46.140 ;
        RECT 26.745 46.095 27.395 46.140 ;
        RECT 30.345 46.095 30.635 46.140 ;
        RECT 32.270 46.080 32.590 46.140 ;
        RECT 35.045 46.280 35.335 46.325 ;
        RECT 40.550 46.280 40.870 46.340 ;
        RECT 35.045 46.140 40.870 46.280 ;
        RECT 35.045 46.095 35.335 46.140 ;
        RECT 40.550 46.080 40.870 46.140 ;
        RECT 20.310 45.800 26.520 45.940 ;
        RECT 31.810 45.940 32.130 46.000 ;
        RECT 33.205 45.940 33.495 45.985 ;
        RECT 31.810 45.800 33.495 45.940 ;
        RECT 20.310 45.740 20.630 45.800 ;
        RECT 31.810 45.740 32.130 45.800 ;
        RECT 33.205 45.755 33.495 45.800 ;
        RECT 36.425 45.940 36.715 45.985 ;
        RECT 39.170 45.940 39.490 46.000 ;
        RECT 36.425 45.800 39.490 45.940 ;
        RECT 36.425 45.755 36.715 45.800 ;
        RECT 39.170 45.740 39.490 45.800 ;
        RECT 2.300 45.120 44.620 45.600 ;
        RECT 16.645 44.735 16.935 44.965 ;
        RECT 8.805 44.580 9.455 44.625 ;
        RECT 11.570 44.580 11.890 44.640 ;
        RECT 12.405 44.580 12.695 44.625 ;
        RECT 8.805 44.440 12.695 44.580 ;
        RECT 8.805 44.395 9.455 44.440 ;
        RECT 11.570 44.380 11.890 44.440 ;
        RECT 12.105 44.395 12.695 44.440 ;
        RECT 4.210 44.240 4.530 44.300 ;
        RECT 5.145 44.240 5.435 44.285 ;
        RECT 4.210 44.100 5.435 44.240 ;
        RECT 4.210 44.040 4.530 44.100 ;
        RECT 5.145 44.055 5.435 44.100 ;
        RECT 5.610 44.240 5.900 44.285 ;
        RECT 7.445 44.240 7.735 44.285 ;
        RECT 11.025 44.240 11.315 44.285 ;
        RECT 5.610 44.100 11.315 44.240 ;
        RECT 5.610 44.055 5.900 44.100 ;
        RECT 7.445 44.055 7.735 44.100 ;
        RECT 11.025 44.055 11.315 44.100 ;
        RECT 12.105 44.080 12.395 44.395 ;
        RECT 16.720 44.240 16.860 44.735 ;
        RECT 32.270 44.720 32.590 44.980 ;
        RECT 34.570 44.920 34.890 44.980 ;
        RECT 37.805 44.920 38.095 44.965 ;
        RECT 34.570 44.780 38.095 44.920 ;
        RECT 34.570 44.720 34.890 44.780 ;
        RECT 37.805 44.735 38.095 44.780 ;
        RECT 21.230 44.580 21.550 44.640 ;
        RECT 30.445 44.580 30.735 44.625 ;
        RECT 31.810 44.580 32.130 44.640 ;
        RECT 21.230 44.440 24.220 44.580 ;
        RECT 21.230 44.380 21.550 44.440 ;
        RECT 17.090 44.240 17.410 44.300 ;
        RECT 18.470 44.240 18.790 44.300 ;
        RECT 16.720 44.100 17.410 44.240 ;
        RECT 17.090 44.040 17.410 44.100 ;
        RECT 17.640 44.100 18.790 44.240 ;
        RECT 6.510 43.700 6.830 43.960 ;
        RECT 6.970 43.900 7.290 43.960 ;
        RECT 6.970 43.760 15.020 43.900 ;
        RECT 6.970 43.700 7.290 43.760 ;
        RECT 6.015 43.560 6.305 43.605 ;
        RECT 7.905 43.560 8.195 43.605 ;
        RECT 11.025 43.560 11.315 43.605 ;
        RECT 6.015 43.420 11.315 43.560 ;
        RECT 6.015 43.375 6.305 43.420 ;
        RECT 7.905 43.375 8.195 43.420 ;
        RECT 11.025 43.375 11.315 43.420 ;
        RECT 14.880 43.280 15.020 43.760 ;
        RECT 15.725 43.715 16.015 43.945 ;
        RECT 16.170 43.900 16.490 43.960 ;
        RECT 17.640 43.945 17.780 44.100 ;
        RECT 18.470 44.040 18.790 44.100 ;
        RECT 23.530 44.040 23.850 44.300 ;
        RECT 24.080 44.240 24.220 44.440 ;
        RECT 30.445 44.440 32.130 44.580 ;
        RECT 32.360 44.580 32.500 44.720 ;
        RECT 32.725 44.580 33.375 44.625 ;
        RECT 36.325 44.580 36.615 44.625 ;
        RECT 32.360 44.440 36.615 44.580 ;
        RECT 30.445 44.395 30.735 44.440 ;
        RECT 31.810 44.380 32.130 44.440 ;
        RECT 32.725 44.395 33.375 44.440 ;
        RECT 36.025 44.395 36.615 44.440 ;
        RECT 24.370 44.240 24.660 44.285 ;
        RECT 24.080 44.100 24.660 44.240 ;
        RECT 24.370 44.055 24.660 44.100 ;
        RECT 25.830 44.240 26.150 44.300 ;
        RECT 26.305 44.240 26.595 44.285 ;
        RECT 25.830 44.100 26.595 44.240 ;
        RECT 25.830 44.040 26.150 44.100 ;
        RECT 26.305 44.055 26.595 44.100 ;
        RECT 27.225 44.240 27.515 44.285 ;
        RECT 28.130 44.240 28.450 44.300 ;
        RECT 27.225 44.100 28.450 44.240 ;
        RECT 27.225 44.055 27.515 44.100 ;
        RECT 28.130 44.040 28.450 44.100 ;
        RECT 29.530 44.240 29.820 44.285 ;
        RECT 31.365 44.240 31.655 44.285 ;
        RECT 34.945 44.240 35.235 44.285 ;
        RECT 29.530 44.100 35.235 44.240 ;
        RECT 29.530 44.055 29.820 44.100 ;
        RECT 31.365 44.055 31.655 44.100 ;
        RECT 34.945 44.055 35.235 44.100 ;
        RECT 36.025 44.080 36.315 44.395 ;
        RECT 17.565 43.900 17.855 43.945 ;
        RECT 19.865 43.900 20.155 43.945 ;
        RECT 16.170 43.760 17.855 43.900 ;
        RECT 15.800 43.560 15.940 43.715 ;
        RECT 16.170 43.700 16.490 43.760 ;
        RECT 17.565 43.715 17.855 43.760 ;
        RECT 18.100 43.760 20.155 43.900 ;
        RECT 18.100 43.620 18.240 43.760 ;
        RECT 19.865 43.715 20.155 43.760 ;
        RECT 24.925 43.715 25.215 43.945 ;
        RECT 18.010 43.560 18.330 43.620 ;
        RECT 15.800 43.420 18.330 43.560 ;
        RECT 25.000 43.560 25.140 43.715 ;
        RECT 25.370 43.700 25.690 43.960 ;
        RECT 28.590 43.900 28.910 43.960 ;
        RECT 29.065 43.900 29.355 43.945 ;
        RECT 28.590 43.760 29.355 43.900 ;
        RECT 28.590 43.700 28.910 43.760 ;
        RECT 29.065 43.715 29.355 43.760 ;
        RECT 28.130 43.560 28.450 43.620 ;
        RECT 25.000 43.420 28.450 43.560 ;
        RECT 18.010 43.360 18.330 43.420 ;
        RECT 28.130 43.360 28.450 43.420 ;
        RECT 29.935 43.560 30.225 43.605 ;
        RECT 31.825 43.560 32.115 43.605 ;
        RECT 34.945 43.560 35.235 43.605 ;
        RECT 29.935 43.420 35.235 43.560 ;
        RECT 29.935 43.375 30.225 43.420 ;
        RECT 31.825 43.375 32.115 43.420 ;
        RECT 34.945 43.375 35.235 43.420 ;
        RECT 8.350 43.220 8.670 43.280 ;
        RECT 13.410 43.220 13.730 43.280 ;
        RECT 13.885 43.220 14.175 43.265 ;
        RECT 8.350 43.080 14.175 43.220 ;
        RECT 8.350 43.020 8.670 43.080 ;
        RECT 13.410 43.020 13.730 43.080 ;
        RECT 13.885 43.035 14.175 43.080 ;
        RECT 14.790 43.020 15.110 43.280 ;
        RECT 20.325 43.220 20.615 43.265 ;
        RECT 22.150 43.220 22.470 43.280 ;
        RECT 25.370 43.220 25.690 43.280 ;
        RECT 20.325 43.080 25.690 43.220 ;
        RECT 20.325 43.035 20.615 43.080 ;
        RECT 22.150 43.020 22.470 43.080 ;
        RECT 25.370 43.020 25.690 43.080 ;
        RECT 2.300 42.400 44.620 42.880 ;
        RECT 13.410 42.200 13.730 42.260 ;
        RECT 15.725 42.200 16.015 42.245 ;
        RECT 13.410 42.060 16.015 42.200 ;
        RECT 13.410 42.000 13.730 42.060 ;
        RECT 15.725 42.015 16.015 42.060 ;
        RECT 23.070 42.200 23.390 42.260 ;
        RECT 23.545 42.200 23.835 42.245 ;
        RECT 23.070 42.060 23.835 42.200 ;
        RECT 23.070 42.000 23.390 42.060 ;
        RECT 23.545 42.015 23.835 42.060 ;
        RECT 28.590 42.000 28.910 42.260 ;
        RECT 31.825 42.200 32.115 42.245 ;
        RECT 35.490 42.200 35.810 42.260 ;
        RECT 31.825 42.060 35.810 42.200 ;
        RECT 31.825 42.015 32.115 42.060 ;
        RECT 25.830 41.860 26.150 41.920 ;
        RECT 31.900 41.860 32.040 42.015 ;
        RECT 35.490 42.000 35.810 42.060 ;
        RECT 25.830 41.720 32.040 41.860 ;
        RECT 34.685 41.860 34.975 41.905 ;
        RECT 37.805 41.860 38.095 41.905 ;
        RECT 39.695 41.860 39.985 41.905 ;
        RECT 34.685 41.720 39.985 41.860 ;
        RECT 25.830 41.660 26.150 41.720 ;
        RECT 34.685 41.675 34.975 41.720 ;
        RECT 37.805 41.675 38.095 41.720 ;
        RECT 39.695 41.675 39.985 41.720 ;
        RECT 17.090 41.520 17.410 41.580 ;
        RECT 17.090 41.380 20.540 41.520 ;
        RECT 17.090 41.320 17.410 41.380 ;
        RECT 6.985 41.180 7.275 41.225 ;
        RECT 8.350 41.180 8.670 41.240 ;
        RECT 6.985 41.040 8.670 41.180 ;
        RECT 6.985 40.995 7.275 41.040 ;
        RECT 8.350 40.980 8.670 41.040 ;
        RECT 16.645 41.180 16.935 41.225 ;
        RECT 18.010 41.180 18.330 41.240 ;
        RECT 16.645 41.040 18.330 41.180 ;
        RECT 16.645 40.995 16.935 41.040 ;
        RECT 18.010 40.980 18.330 41.040 ;
        RECT 18.470 40.980 18.790 41.240 ;
        RECT 20.400 41.225 20.540 41.380 ;
        RECT 39.170 41.320 39.490 41.580 ;
        RECT 40.550 41.320 40.870 41.580 ;
        RECT 20.325 40.995 20.615 41.225 ;
        RECT 21.230 40.980 21.550 41.240 ;
        RECT 21.690 40.980 22.010 41.240 ;
        RECT 22.150 40.980 22.470 41.240 ;
        RECT 23.085 41.180 23.375 41.225 ;
        RECT 25.830 41.180 26.150 41.240 ;
        RECT 23.085 41.040 26.150 41.180 ;
        RECT 23.085 40.995 23.375 41.040 ;
        RECT 25.830 40.980 26.150 41.040 ;
        RECT 28.130 40.980 28.450 41.240 ;
        RECT 32.270 40.840 32.590 40.900 ;
        RECT 33.605 40.885 33.895 41.200 ;
        RECT 34.685 41.180 34.975 41.225 ;
        RECT 38.265 41.180 38.555 41.225 ;
        RECT 40.100 41.180 40.390 41.225 ;
        RECT 34.685 41.040 40.390 41.180 ;
        RECT 34.685 40.995 34.975 41.040 ;
        RECT 38.265 40.995 38.555 41.040 ;
        RECT 40.100 40.995 40.390 41.040 ;
        RECT 33.305 40.840 33.895 40.885 ;
        RECT 36.410 40.885 36.730 40.900 ;
        RECT 36.410 40.840 37.195 40.885 ;
        RECT 32.270 40.700 37.195 40.840 ;
        RECT 32.270 40.640 32.590 40.700 ;
        RECT 33.305 40.655 33.595 40.700 ;
        RECT 36.410 40.655 37.195 40.700 ;
        RECT 36.410 40.640 36.730 40.655 ;
        RECT 5.130 40.500 5.450 40.560 ;
        RECT 6.525 40.500 6.815 40.545 ;
        RECT 5.130 40.360 6.815 40.500 ;
        RECT 5.130 40.300 5.450 40.360 ;
        RECT 6.525 40.315 6.815 40.360 ;
        RECT 17.565 40.500 17.855 40.545 ;
        RECT 23.530 40.500 23.850 40.560 ;
        RECT 17.565 40.360 23.850 40.500 ;
        RECT 17.565 40.315 17.855 40.360 ;
        RECT 23.530 40.300 23.850 40.360 ;
        RECT 2.300 39.680 44.620 40.160 ;
        RECT 28.130 39.480 28.450 39.540 ;
        RECT 34.125 39.480 34.415 39.525 ;
        RECT 28.130 39.340 34.415 39.480 ;
        RECT 28.130 39.280 28.450 39.340 ;
        RECT 34.125 39.295 34.415 39.340 ;
        RECT 6.050 39.140 6.370 39.200 ;
        RECT 6.525 39.140 6.815 39.185 ;
        RECT 6.050 39.000 6.815 39.140 ;
        RECT 6.050 38.940 6.370 39.000 ;
        RECT 6.525 38.955 6.815 39.000 ;
        RECT 8.805 39.140 9.455 39.185 ;
        RECT 11.570 39.140 11.890 39.200 ;
        RECT 12.405 39.140 12.695 39.185 ;
        RECT 15.710 39.140 16.030 39.200 ;
        RECT 8.805 39.000 16.030 39.140 ;
        RECT 8.805 38.955 9.455 39.000 ;
        RECT 11.570 38.940 11.890 39.000 ;
        RECT 12.105 38.955 12.695 39.000 ;
        RECT 5.130 38.600 5.450 38.860 ;
        RECT 5.610 38.800 5.900 38.845 ;
        RECT 7.445 38.800 7.735 38.845 ;
        RECT 11.025 38.800 11.315 38.845 ;
        RECT 5.610 38.660 11.315 38.800 ;
        RECT 5.610 38.615 5.900 38.660 ;
        RECT 7.445 38.615 7.735 38.660 ;
        RECT 11.025 38.615 11.315 38.660 ;
        RECT 12.105 38.640 12.395 38.955 ;
        RECT 15.710 38.940 16.030 39.000 ;
        RECT 35.605 39.140 35.895 39.185 ;
        RECT 36.410 39.140 36.730 39.200 ;
        RECT 38.845 39.140 39.495 39.185 ;
        RECT 35.605 39.000 39.495 39.140 ;
        RECT 35.605 38.955 36.195 39.000 ;
        RECT 35.905 38.640 36.195 38.955 ;
        RECT 36.410 38.940 36.730 39.000 ;
        RECT 38.845 38.955 39.495 39.000 ;
        RECT 36.985 38.800 37.275 38.845 ;
        RECT 40.565 38.800 40.855 38.845 ;
        RECT 42.400 38.800 42.690 38.845 ;
        RECT 36.985 38.660 42.690 38.800 ;
        RECT 36.985 38.615 37.275 38.660 ;
        RECT 40.565 38.615 40.855 38.660 ;
        RECT 42.400 38.615 42.690 38.660 ;
        RECT 41.470 38.260 41.790 38.520 ;
        RECT 42.850 38.260 43.170 38.520 ;
        RECT 6.015 38.120 6.305 38.165 ;
        RECT 7.905 38.120 8.195 38.165 ;
        RECT 11.025 38.120 11.315 38.165 ;
        RECT 6.015 37.980 11.315 38.120 ;
        RECT 6.015 37.935 6.305 37.980 ;
        RECT 7.905 37.935 8.195 37.980 ;
        RECT 11.025 37.935 11.315 37.980 ;
        RECT 36.985 38.120 37.275 38.165 ;
        RECT 40.105 38.120 40.395 38.165 ;
        RECT 41.995 38.120 42.285 38.165 ;
        RECT 36.985 37.980 42.285 38.120 ;
        RECT 36.985 37.935 37.275 37.980 ;
        RECT 40.105 37.935 40.395 37.980 ;
        RECT 41.995 37.935 42.285 37.980 ;
        RECT 13.870 37.580 14.190 37.840 ;
        RECT 34.110 37.580 34.430 37.840 ;
        RECT 2.300 36.960 44.620 37.440 ;
        RECT 6.050 36.760 6.370 36.820 ;
        RECT 9.285 36.760 9.575 36.805 ;
        RECT 6.050 36.620 9.575 36.760 ;
        RECT 6.050 36.560 6.370 36.620 ;
        RECT 9.285 36.575 9.575 36.620 ;
        RECT 36.885 36.760 37.175 36.805 ;
        RECT 41.470 36.760 41.790 36.820 ;
        RECT 36.885 36.620 41.790 36.760 ;
        RECT 36.885 36.575 37.175 36.620 ;
        RECT 41.470 36.560 41.790 36.620 ;
        RECT 35.505 36.420 35.795 36.465 ;
        RECT 42.850 36.420 43.170 36.480 ;
        RECT 35.505 36.280 43.170 36.420 ;
        RECT 35.505 36.235 35.795 36.280 ;
        RECT 42.850 36.220 43.170 36.280 ;
        RECT 34.110 36.080 34.430 36.140 ;
        RECT 34.110 35.940 36.640 36.080 ;
        RECT 34.110 35.880 34.430 35.940 ;
        RECT 9.745 35.740 10.035 35.785 ;
        RECT 12.045 35.740 12.335 35.785 ;
        RECT 13.870 35.740 14.190 35.800 ;
        RECT 9.745 35.600 14.190 35.740 ;
        RECT 9.745 35.555 10.035 35.600 ;
        RECT 12.045 35.555 12.335 35.600 ;
        RECT 13.870 35.540 14.190 35.600 ;
        RECT 17.565 35.740 17.855 35.785 ;
        RECT 19.390 35.740 19.710 35.800 ;
        RECT 21.690 35.740 22.010 35.800 ;
        RECT 17.565 35.600 22.010 35.740 ;
        RECT 17.565 35.555 17.855 35.600 ;
        RECT 19.390 35.540 19.710 35.600 ;
        RECT 21.690 35.540 22.010 35.600 ;
        RECT 35.030 35.540 35.350 35.800 ;
        RECT 36.500 35.785 36.640 35.940 ;
        RECT 36.425 35.555 36.715 35.785 ;
        RECT 12.505 35.060 12.795 35.105 ;
        RECT 12.950 35.060 13.270 35.120 ;
        RECT 12.505 34.920 13.270 35.060 ;
        RECT 12.505 34.875 12.795 34.920 ;
        RECT 12.950 34.860 13.270 34.920 ;
        RECT 14.330 35.060 14.650 35.120 ;
        RECT 17.105 35.060 17.395 35.105 ;
        RECT 14.330 34.920 17.395 35.060 ;
        RECT 14.330 34.860 14.650 34.920 ;
        RECT 17.105 34.875 17.395 34.920 ;
        RECT 2.300 34.240 44.620 34.720 ;
        RECT 21.690 33.840 22.010 34.100 ;
        RECT 14.330 33.500 14.650 33.760 ;
        RECT 15.710 33.700 16.030 33.760 ;
        RECT 16.625 33.700 17.275 33.745 ;
        RECT 20.225 33.700 20.515 33.745 ;
        RECT 15.710 33.560 20.515 33.700 ;
        RECT 15.710 33.500 16.030 33.560 ;
        RECT 16.625 33.515 17.275 33.560 ;
        RECT 19.925 33.515 20.515 33.560 ;
        RECT 34.105 33.700 34.755 33.745 ;
        RECT 36.870 33.700 37.190 33.760 ;
        RECT 37.705 33.700 37.995 33.745 ;
        RECT 34.105 33.560 37.995 33.700 ;
        RECT 34.105 33.515 34.755 33.560 ;
        RECT 12.950 33.160 13.270 33.420 ;
        RECT 13.430 33.360 13.720 33.405 ;
        RECT 15.265 33.360 15.555 33.405 ;
        RECT 18.845 33.360 19.135 33.405 ;
        RECT 13.430 33.220 19.135 33.360 ;
        RECT 13.430 33.175 13.720 33.220 ;
        RECT 15.265 33.175 15.555 33.220 ;
        RECT 18.845 33.175 19.135 33.220 ;
        RECT 19.925 33.200 20.215 33.515 ;
        RECT 36.870 33.500 37.190 33.560 ;
        RECT 37.405 33.515 37.995 33.560 ;
        RECT 23.070 33.360 23.390 33.420 ;
        RECT 23.545 33.360 23.835 33.405 ;
        RECT 23.070 33.220 23.835 33.360 ;
        RECT 23.070 33.160 23.390 33.220 ;
        RECT 23.545 33.175 23.835 33.220 ;
        RECT 25.830 33.360 26.150 33.420 ;
        RECT 29.050 33.360 29.370 33.420 ;
        RECT 25.830 33.220 29.370 33.360 ;
        RECT 25.830 33.160 26.150 33.220 ;
        RECT 29.050 33.160 29.370 33.220 ;
        RECT 30.910 33.360 31.200 33.405 ;
        RECT 32.745 33.360 33.035 33.405 ;
        RECT 36.325 33.360 36.615 33.405 ;
        RECT 30.910 33.220 36.615 33.360 ;
        RECT 30.910 33.175 31.200 33.220 ;
        RECT 32.745 33.175 33.035 33.220 ;
        RECT 36.325 33.175 36.615 33.220 ;
        RECT 37.405 33.200 37.695 33.515 ;
        RECT 29.525 33.020 29.815 33.065 ;
        RECT 30.445 33.020 30.735 33.065 ;
        RECT 29.525 32.880 30.735 33.020 ;
        RECT 29.525 32.835 29.815 32.880 ;
        RECT 30.445 32.835 30.735 32.880 ;
        RECT 31.810 32.820 32.130 33.080 ;
        RECT 35.030 33.020 35.350 33.080 ;
        RECT 39.185 33.020 39.475 33.065 ;
        RECT 35.030 32.880 39.475 33.020 ;
        RECT 35.030 32.820 35.350 32.880 ;
        RECT 39.185 32.835 39.475 32.880 ;
        RECT 13.835 32.680 14.125 32.725 ;
        RECT 15.725 32.680 16.015 32.725 ;
        RECT 18.845 32.680 19.135 32.725 ;
        RECT 13.835 32.540 19.135 32.680 ;
        RECT 13.835 32.495 14.125 32.540 ;
        RECT 15.725 32.495 16.015 32.540 ;
        RECT 18.845 32.495 19.135 32.540 ;
        RECT 31.315 32.680 31.605 32.725 ;
        RECT 33.205 32.680 33.495 32.725 ;
        RECT 36.325 32.680 36.615 32.725 ;
        RECT 31.315 32.540 36.615 32.680 ;
        RECT 31.315 32.495 31.605 32.540 ;
        RECT 33.205 32.495 33.495 32.540 ;
        RECT 36.325 32.495 36.615 32.540 ;
        RECT 23.990 32.140 24.310 32.400 ;
        RECT 25.370 32.140 25.690 32.400 ;
        RECT 2.300 31.520 44.620 32.000 ;
        RECT 25.370 31.365 25.690 31.380 ;
        RECT 25.320 31.135 25.690 31.365 ;
        RECT 25.370 31.120 25.690 31.135 ;
        RECT 31.810 31.320 32.130 31.380 ;
        RECT 34.125 31.320 34.415 31.365 ;
        RECT 31.810 31.180 34.415 31.320 ;
        RECT 31.810 31.120 32.130 31.180 ;
        RECT 34.125 31.135 34.415 31.180 ;
        RECT 24.875 30.980 25.165 31.025 ;
        RECT 26.765 30.980 27.055 31.025 ;
        RECT 29.885 30.980 30.175 31.025 ;
        RECT 24.875 30.840 30.175 30.980 ;
        RECT 24.875 30.795 25.165 30.840 ;
        RECT 26.765 30.795 27.055 30.840 ;
        RECT 29.885 30.795 30.175 30.840 ;
        RECT 23.990 30.440 24.310 30.700 ;
        RECT 29.050 30.640 29.370 30.700 ;
        RECT 32.745 30.640 33.035 30.685 ;
        RECT 29.050 30.500 33.035 30.640 ;
        RECT 29.050 30.440 29.370 30.500 ;
        RECT 32.745 30.455 33.035 30.500 ;
        RECT 10.665 30.300 10.955 30.345 ;
        RECT 14.790 30.300 15.110 30.360 ;
        RECT 17.550 30.300 17.870 30.360 ;
        RECT 10.665 30.160 17.870 30.300 ;
        RECT 10.665 30.115 10.955 30.160 ;
        RECT 14.790 30.100 15.110 30.160 ;
        RECT 17.550 30.100 17.870 30.160 ;
        RECT 19.390 30.100 19.710 30.360 ;
        RECT 23.070 30.100 23.390 30.360 ;
        RECT 24.470 30.300 24.760 30.345 ;
        RECT 26.305 30.300 26.595 30.345 ;
        RECT 29.885 30.300 30.175 30.345 ;
        RECT 24.470 30.160 30.175 30.300 ;
        RECT 24.470 30.115 24.760 30.160 ;
        RECT 26.305 30.115 26.595 30.160 ;
        RECT 29.885 30.115 30.175 30.160 ;
        RECT 26.750 29.960 27.070 30.020 ;
        RECT 30.965 30.005 31.255 30.320 ;
        RECT 34.585 30.300 34.875 30.345 ;
        RECT 35.030 30.300 35.350 30.360 ;
        RECT 34.585 30.160 35.350 30.300 ;
        RECT 34.585 30.115 34.875 30.160 ;
        RECT 35.030 30.100 35.350 30.160 ;
        RECT 27.665 29.960 28.315 30.005 ;
        RECT 30.965 29.960 31.555 30.005 ;
        RECT 26.750 29.820 31.555 29.960 ;
        RECT 26.750 29.760 27.070 29.820 ;
        RECT 27.665 29.775 28.315 29.820 ;
        RECT 31.265 29.775 31.555 29.820 ;
        RECT 9.270 29.620 9.590 29.680 ;
        RECT 10.205 29.620 10.495 29.665 ;
        RECT 9.270 29.480 10.495 29.620 ;
        RECT 9.270 29.420 9.590 29.480 ;
        RECT 10.205 29.435 10.495 29.480 ;
        RECT 18.470 29.620 18.790 29.680 ;
        RECT 18.945 29.620 19.235 29.665 ;
        RECT 18.470 29.480 19.235 29.620 ;
        RECT 18.470 29.420 18.790 29.480 ;
        RECT 18.945 29.435 19.235 29.480 ;
        RECT 19.850 29.620 20.170 29.680 ;
        RECT 22.625 29.620 22.915 29.665 ;
        RECT 19.850 29.480 22.915 29.620 ;
        RECT 19.850 29.420 20.170 29.480 ;
        RECT 22.625 29.435 22.915 29.480 ;
        RECT 2.300 28.800 44.620 29.280 ;
        RECT 9.270 28.400 9.590 28.660 ;
        RECT 17.550 28.400 17.870 28.660 ;
        RECT 23.070 28.600 23.390 28.660 ;
        RECT 27.225 28.600 27.515 28.645 ;
        RECT 19.480 28.460 21.000 28.600 ;
        RECT 9.360 28.260 9.500 28.400 ;
        RECT 12.490 28.305 12.810 28.320 ;
        RECT 10.205 28.260 10.495 28.305 ;
        RECT 9.360 28.120 10.495 28.260 ;
        RECT 10.205 28.075 10.495 28.120 ;
        RECT 12.485 28.260 13.135 28.305 ;
        RECT 16.085 28.260 16.375 28.305 ;
        RECT 19.480 28.260 19.620 28.460 ;
        RECT 12.485 28.120 19.620 28.260 ;
        RECT 12.485 28.075 13.135 28.120 ;
        RECT 15.785 28.075 16.375 28.120 ;
        RECT 12.490 28.060 12.810 28.075 ;
        RECT 15.785 27.980 16.075 28.075 ;
        RECT 19.850 28.060 20.170 28.320 ;
        RECT 20.860 28.260 21.000 28.460 ;
        RECT 23.070 28.460 27.515 28.600 ;
        RECT 23.070 28.400 23.390 28.460 ;
        RECT 27.225 28.415 27.515 28.460 ;
        RECT 22.145 28.260 22.795 28.305 ;
        RECT 23.530 28.260 23.850 28.320 ;
        RECT 25.745 28.260 26.035 28.305 ;
        RECT 26.750 28.260 27.070 28.320 ;
        RECT 20.860 28.120 27.070 28.260 ;
        RECT 22.145 28.075 22.795 28.120 ;
        RECT 23.530 28.060 23.850 28.120 ;
        RECT 25.445 28.075 26.035 28.120 ;
        RECT 8.350 27.720 8.670 27.980 ;
        RECT 9.290 27.920 9.580 27.965 ;
        RECT 11.125 27.920 11.415 27.965 ;
        RECT 14.705 27.920 14.995 27.965 ;
        RECT 9.290 27.780 14.995 27.920 ;
        RECT 9.290 27.735 9.580 27.780 ;
        RECT 11.125 27.735 11.415 27.780 ;
        RECT 14.705 27.735 14.995 27.780 ;
        RECT 15.710 27.760 16.075 27.980 ;
        RECT 15.710 27.720 16.030 27.760 ;
        RECT 18.470 27.720 18.790 27.980 ;
        RECT 18.950 27.920 19.240 27.965 ;
        RECT 20.785 27.920 21.075 27.965 ;
        RECT 24.365 27.920 24.655 27.965 ;
        RECT 18.950 27.780 24.655 27.920 ;
        RECT 18.950 27.735 19.240 27.780 ;
        RECT 20.785 27.735 21.075 27.780 ;
        RECT 24.365 27.735 24.655 27.780 ;
        RECT 25.445 27.760 25.735 28.075 ;
        RECT 26.750 28.060 27.070 28.120 ;
        RECT 7.905 27.580 8.195 27.625 ;
        RECT 8.825 27.580 9.115 27.625 ;
        RECT 7.905 27.440 9.115 27.580 ;
        RECT 7.905 27.395 8.195 27.440 ;
        RECT 8.825 27.395 9.115 27.440 ;
        RECT 9.695 27.240 9.985 27.285 ;
        RECT 11.585 27.240 11.875 27.285 ;
        RECT 14.705 27.240 14.995 27.285 ;
        RECT 9.695 27.100 14.995 27.240 ;
        RECT 9.695 27.055 9.985 27.100 ;
        RECT 11.585 27.055 11.875 27.100 ;
        RECT 14.705 27.055 14.995 27.100 ;
        RECT 19.355 27.240 19.645 27.285 ;
        RECT 21.245 27.240 21.535 27.285 ;
        RECT 24.365 27.240 24.655 27.285 ;
        RECT 19.355 27.100 24.655 27.240 ;
        RECT 19.355 27.055 19.645 27.100 ;
        RECT 21.245 27.055 21.535 27.100 ;
        RECT 24.365 27.055 24.655 27.100 ;
        RECT 2.300 26.080 44.620 26.560 ;
        RECT 6.475 25.540 6.765 25.585 ;
        RECT 8.365 25.540 8.655 25.585 ;
        RECT 11.485 25.540 11.775 25.585 ;
        RECT 6.475 25.400 11.775 25.540 ;
        RECT 6.475 25.355 6.765 25.400 ;
        RECT 8.365 25.355 8.655 25.400 ;
        RECT 11.485 25.355 11.775 25.400 ;
        RECT 5.590 24.660 5.910 24.920 ;
        RECT 6.070 24.860 6.360 24.905 ;
        RECT 7.905 24.860 8.195 24.905 ;
        RECT 11.485 24.860 11.775 24.905 ;
        RECT 6.070 24.720 11.775 24.860 ;
        RECT 6.070 24.675 6.360 24.720 ;
        RECT 7.905 24.675 8.195 24.720 ;
        RECT 11.485 24.675 11.775 24.720 ;
        RECT 12.490 24.880 12.810 24.920 ;
        RECT 12.490 24.660 12.855 24.880 ;
        RECT 6.970 24.320 7.290 24.580 ;
        RECT 12.565 24.565 12.855 24.660 ;
        RECT 9.265 24.520 9.915 24.565 ;
        RECT 12.565 24.520 13.155 24.565 ;
        RECT 9.265 24.380 13.155 24.520 ;
        RECT 9.265 24.335 9.915 24.380 ;
        RECT 12.865 24.335 13.155 24.380 ;
        RECT 8.350 24.180 8.670 24.240 ;
        RECT 14.345 24.180 14.635 24.225 ;
        RECT 8.350 24.040 14.635 24.180 ;
        RECT 8.350 23.980 8.670 24.040 ;
        RECT 14.345 23.995 14.635 24.040 ;
        RECT 2.300 23.360 44.620 23.840 ;
        RECT 6.970 23.160 7.290 23.220 ;
        RECT 9.745 23.160 10.035 23.205 ;
        RECT 6.970 23.020 10.035 23.160 ;
        RECT 6.970 22.960 7.290 23.020 ;
        RECT 9.745 22.975 10.035 23.020 ;
        RECT 8.350 22.480 8.670 22.540 ;
        RECT 10.205 22.480 10.495 22.525 ;
        RECT 8.350 22.340 10.495 22.480 ;
        RECT 8.350 22.280 8.670 22.340 ;
        RECT 10.205 22.295 10.495 22.340 ;
        RECT 15.710 22.140 16.030 22.200 ;
        RECT 17.105 22.140 17.395 22.185 ;
        RECT 15.710 22.000 17.395 22.140 ;
        RECT 15.710 21.940 16.030 22.000 ;
        RECT 17.105 21.955 17.395 22.000 ;
        RECT 20.325 22.140 20.615 22.185 ;
        RECT 20.785 22.140 21.075 22.185 ;
        RECT 20.325 22.000 21.075 22.140 ;
        RECT 20.325 21.955 20.615 22.000 ;
        RECT 20.785 21.955 21.075 22.000 ;
        RECT 24.005 22.140 24.295 22.185 ;
        RECT 24.465 22.140 24.755 22.185 ;
        RECT 24.005 22.000 24.755 22.140 ;
        RECT 24.005 21.955 24.295 22.000 ;
        RECT 24.465 21.955 24.755 22.000 ;
        RECT 27.685 22.140 27.975 22.185 ;
        RECT 28.605 22.140 28.895 22.185 ;
        RECT 27.685 22.000 28.895 22.140 ;
        RECT 27.685 21.955 27.975 22.000 ;
        RECT 28.605 21.955 28.895 22.000 ;
        RECT 31.825 22.140 32.115 22.185 ;
        RECT 35.045 22.140 35.335 22.185 ;
        RECT 31.825 22.000 35.335 22.140 ;
        RECT 31.825 21.955 32.115 22.000 ;
        RECT 35.045 21.955 35.335 22.000 ;
        RECT 32.270 21.260 32.590 21.520 ;
        RECT 2.300 20.640 44.620 21.120 ;
        RECT 5.590 20.440 5.910 20.500 ;
        RECT 9.285 20.440 9.575 20.485 ;
        RECT 5.590 20.300 9.575 20.440 ;
        RECT 5.590 20.240 5.910 20.300 ;
        RECT 9.285 20.255 9.575 20.300 ;
        RECT 15.710 20.240 16.030 20.500 ;
        RECT 32.270 19.560 32.590 19.820 ;
        RECT 9.270 19.420 9.590 19.480 ;
        RECT 9.745 19.420 10.035 19.465 ;
        RECT 9.270 19.280 10.035 19.420 ;
        RECT 9.270 19.220 9.590 19.280 ;
        RECT 9.745 19.235 10.035 19.280 ;
        RECT 18.945 19.420 19.235 19.465 ;
        RECT 20.310 19.420 20.630 19.480 ;
        RECT 18.945 19.280 20.630 19.420 ;
        RECT 18.945 19.235 19.235 19.280 ;
        RECT 20.310 19.220 20.630 19.280 ;
        RECT 22.150 19.420 22.470 19.480 ;
        RECT 23.085 19.420 23.375 19.465 ;
        RECT 22.150 19.280 23.375 19.420 ;
        RECT 22.150 19.220 22.470 19.280 ;
        RECT 23.085 19.235 23.375 19.280 ;
        RECT 35.505 19.420 35.795 19.465 ;
        RECT 38.725 19.420 39.015 19.465 ;
        RECT 35.505 19.280 39.015 19.420 ;
        RECT 35.505 19.235 35.795 19.280 ;
        RECT 38.725 19.235 39.015 19.280 ;
        RECT 22.610 18.540 22.930 18.800 ;
        RECT 34.570 18.740 34.890 18.800 ;
        RECT 35.965 18.740 36.255 18.785 ;
        RECT 34.570 18.600 36.255 18.740 ;
        RECT 34.570 18.540 34.890 18.600 ;
        RECT 35.965 18.555 36.255 18.600 ;
        RECT 2.300 17.920 44.620 18.400 ;
        RECT 9.270 17.720 9.590 17.780 ;
        RECT 9.745 17.720 10.035 17.765 ;
        RECT 9.270 17.580 10.035 17.720 ;
        RECT 9.270 17.520 9.590 17.580 ;
        RECT 9.745 17.535 10.035 17.580 ;
        RECT 11.225 17.380 11.515 17.425 ;
        RECT 12.030 17.380 12.350 17.440 ;
        RECT 14.465 17.380 15.115 17.425 ;
        RECT 11.225 17.240 15.115 17.380 ;
        RECT 11.225 17.195 11.815 17.240 ;
        RECT 11.525 16.880 11.815 17.195 ;
        RECT 12.030 17.180 12.350 17.240 ;
        RECT 14.465 17.195 15.115 17.240 ;
        RECT 22.700 17.240 24.220 17.380 ;
        RECT 22.700 17.100 22.840 17.240 ;
        RECT 12.605 17.040 12.895 17.085 ;
        RECT 16.185 17.040 16.475 17.085 ;
        RECT 18.020 17.040 18.310 17.085 ;
        RECT 12.605 16.900 18.310 17.040 ;
        RECT 12.605 16.855 12.895 16.900 ;
        RECT 16.185 16.855 16.475 16.900 ;
        RECT 18.020 16.855 18.310 16.900 ;
        RECT 18.485 17.040 18.775 17.085 ;
        RECT 20.310 17.040 20.630 17.100 ;
        RECT 18.485 16.900 20.630 17.040 ;
        RECT 18.485 16.855 18.775 16.900 ;
        RECT 20.310 16.840 20.630 16.900 ;
        RECT 22.610 16.840 22.930 17.100 ;
        RECT 23.530 16.840 23.850 17.100 ;
        RECT 24.080 17.040 24.220 17.240 ;
        RECT 25.970 17.040 26.260 17.085 ;
        RECT 24.080 16.900 26.260 17.040 ;
        RECT 25.970 16.855 26.260 16.900 ;
        RECT 28.130 17.040 28.450 17.100 ;
        RECT 29.240 17.040 29.530 17.085 ;
        RECT 28.130 16.900 29.530 17.040 ;
        RECT 28.130 16.840 28.450 16.900 ;
        RECT 29.240 16.855 29.530 16.900 ;
        RECT 29.755 17.040 30.045 17.085 ;
        RECT 31.080 17.040 31.370 17.085 ;
        RECT 29.755 16.900 31.370 17.040 ;
        RECT 29.755 16.855 30.045 16.900 ;
        RECT 31.080 16.855 31.370 16.900 ;
        RECT 31.595 17.040 31.885 17.085 ;
        RECT 32.460 17.040 32.750 17.085 ;
        RECT 31.595 16.900 32.750 17.040 ;
        RECT 31.595 16.855 31.885 16.900 ;
        RECT 32.460 16.855 32.750 16.900 ;
        RECT 33.650 16.840 33.970 17.100 ;
        RECT 34.570 16.840 34.890 17.100 ;
        RECT 11.110 16.700 11.430 16.760 ;
        RECT 17.105 16.700 17.395 16.745 ;
        RECT 11.110 16.560 17.395 16.700 ;
        RECT 11.110 16.500 11.430 16.560 ;
        RECT 17.105 16.515 17.395 16.560 ;
        RECT 20.770 16.500 21.090 16.760 ;
        RECT 12.605 16.360 12.895 16.405 ;
        RECT 15.725 16.360 16.015 16.405 ;
        RECT 17.615 16.360 17.905 16.405 ;
        RECT 12.605 16.220 17.905 16.360 ;
        RECT 12.605 16.175 12.895 16.220 ;
        RECT 15.725 16.175 16.015 16.220 ;
        RECT 17.615 16.175 17.905 16.220 ;
        RECT 32.270 16.360 32.590 16.420 ;
        RECT 33.665 16.360 33.955 16.405 ;
        RECT 32.270 16.220 33.955 16.360 ;
        RECT 32.270 16.160 32.590 16.220 ;
        RECT 33.665 16.175 33.955 16.220 ;
        RECT 25.830 16.065 26.150 16.080 ;
        RECT 33.190 16.065 33.510 16.080 ;
        RECT 25.615 15.835 26.150 16.065 ;
        RECT 32.975 15.835 33.510 16.065 ;
        RECT 25.830 15.820 26.150 15.835 ;
        RECT 33.190 15.820 33.510 15.835 ;
        RECT 2.300 15.200 44.620 15.680 ;
        RECT 11.110 14.800 11.430 15.060 ;
        RECT 32.285 15.000 32.575 15.045 ;
        RECT 33.650 15.000 33.970 15.060 ;
        RECT 32.285 14.860 33.970 15.000 ;
        RECT 32.285 14.815 32.575 14.860 ;
        RECT 33.650 14.800 33.970 14.860 ;
        RECT 20.310 14.320 20.630 14.380 ;
        RECT 25.830 14.320 26.150 14.380 ;
        RECT 26.305 14.320 26.595 14.365 ;
        RECT 20.310 14.180 25.600 14.320 ;
        RECT 20.310 14.120 20.630 14.180 ;
        RECT 9.270 13.980 9.590 14.040 ;
        RECT 25.460 14.025 25.600 14.180 ;
        RECT 25.830 14.180 26.595 14.320 ;
        RECT 25.830 14.120 26.150 14.180 ;
        RECT 26.305 14.135 26.595 14.180 ;
        RECT 10.665 13.980 10.955 14.025 ;
        RECT 20.960 13.980 21.250 14.025 ;
        RECT 9.270 13.840 10.955 13.980 ;
        RECT 9.270 13.780 9.590 13.840 ;
        RECT 10.665 13.795 10.955 13.840 ;
        RECT 20.860 13.795 21.250 13.980 ;
        RECT 21.475 13.980 21.765 14.025 ;
        RECT 22.165 13.980 22.455 14.025 ;
        RECT 21.475 13.840 22.455 13.980 ;
        RECT 21.475 13.795 21.765 13.840 ;
        RECT 22.165 13.795 22.455 13.840 ;
        RECT 25.385 13.980 25.675 14.025 ;
        RECT 32.270 13.980 32.590 14.040 ;
        RECT 25.385 13.840 32.590 13.980 ;
        RECT 25.385 13.795 25.675 13.840 ;
        RECT 20.860 13.640 21.000 13.795 ;
        RECT 32.270 13.780 32.590 13.840 ;
        RECT 33.190 13.780 33.510 14.040 ;
        RECT 23.530 13.640 23.850 13.700 ;
        RECT 20.860 13.500 23.850 13.640 ;
        RECT 23.530 13.440 23.850 13.500 ;
        RECT 22.625 13.300 22.915 13.345 ;
        RECT 24.910 13.300 25.230 13.360 ;
        RECT 22.625 13.160 25.230 13.300 ;
        RECT 22.625 13.115 22.915 13.160 ;
        RECT 24.910 13.100 25.230 13.160 ;
        RECT 2.300 12.480 44.620 12.960 ;
        RECT 27.070 7.865 27.600 8.265 ;
        RECT 20.750 7.405 21.305 7.805 ;
        RECT 24.845 7.405 25.250 7.805 ;
        RECT 27.630 5.435 28.030 5.835 ;
        RECT 21.520 0.285 21.920 0.685 ;
      LAYER met2 ;
        RECT 15.340 56.030 16.400 56.170 ;
        RECT 15.340 55.970 15.480 56.030 ;
        RECT 15.090 55.960 15.480 55.970 ;
        RECT 6.530 53.335 8.070 53.705 ;
        RECT 5.620 51.830 5.880 52.150 ;
        RECT 4.700 49.110 4.960 49.430 ;
        RECT 5.680 49.170 5.820 51.830 ;
        RECT 6.080 51.150 6.340 51.470 ;
        RECT 6.140 50.110 6.280 51.150 ;
        RECT 9.360 50.450 9.500 55.960 ;
        RECT 9.830 50.615 11.370 50.985 ;
        RECT 9.300 50.130 9.560 50.450 ;
        RECT 6.080 49.790 6.340 50.110 ;
        RECT 11.600 49.450 11.860 49.770 ;
        RECT 6.080 49.170 6.340 49.430 ;
        RECT 5.680 49.110 6.340 49.170 ;
        RECT 4.760 47.730 4.900 49.110 ;
        RECT 5.680 49.030 6.280 49.110 ;
        RECT 11.660 49.090 11.800 49.450 ;
        RECT 4.700 47.410 4.960 47.730 ;
        RECT 5.680 46.710 5.820 49.030 ;
        RECT 11.600 48.770 11.860 49.090 ;
        RECT 6.530 47.895 8.070 48.265 ;
        RECT 5.620 46.390 5.880 46.710 ;
        RECT 6.540 46.450 6.800 46.710 ;
        RECT 6.540 46.390 7.200 46.450 ;
        RECT 8.380 46.390 8.640 46.710 ;
        RECT 6.600 46.310 7.200 46.390 ;
        RECT 4.240 45.710 4.500 46.030 ;
        RECT 6.540 45.710 6.800 46.030 ;
        RECT 4.300 44.330 4.440 45.710 ;
        RECT 4.240 44.010 4.500 44.330 ;
        RECT 6.600 43.990 6.740 45.710 ;
        RECT 7.060 43.990 7.200 46.310 ;
        RECT 6.540 43.670 6.800 43.990 ;
        RECT 7.000 43.670 7.260 43.990 ;
        RECT 8.440 43.310 8.580 46.390 ;
        RECT 9.830 45.175 11.370 45.545 ;
        RECT 11.660 44.670 11.800 48.770 ;
        RECT 12.120 46.710 12.260 55.960 ;
        RECT 14.880 55.830 15.480 55.960 ;
        RECT 16.260 49.770 16.400 56.030 ;
        RECT 30.980 56.030 32.040 56.170 ;
        RECT 30.980 55.970 31.120 56.030 ;
        RECT 30.730 55.960 31.120 55.970 ;
        RECT 17.640 50.110 17.780 55.960 ;
        RECT 30.520 55.830 31.120 55.960 ;
        RECT 26.530 53.335 28.070 53.705 ;
        RECT 29.080 51.150 29.340 51.470 ;
        RECT 29.140 50.450 29.280 51.150 ;
        RECT 29.830 50.615 31.370 50.985 ;
        RECT 29.080 50.130 29.340 50.450 ;
        RECT 17.580 49.790 17.840 50.110 ;
        RECT 12.980 49.450 13.240 49.770 ;
        RECT 16.200 49.450 16.460 49.770 ;
        RECT 13.040 47.730 13.180 49.450 ;
        RECT 12.980 47.410 13.240 47.730 ;
        RECT 16.260 46.710 16.400 49.450 ;
        RECT 12.060 46.390 12.320 46.710 ;
        RECT 16.200 46.390 16.460 46.710 ;
        RECT 17.640 46.620 17.780 49.790 ;
        RECT 24.480 49.110 24.740 49.430 ;
        RECT 28.160 49.110 28.420 49.430 ;
        RECT 20.340 48.770 20.600 49.090 ;
        RECT 18.040 46.620 18.300 46.710 ;
        RECT 17.640 46.480 18.300 46.620 ;
        RECT 18.040 46.390 18.300 46.480 ;
        RECT 11.600 44.350 11.860 44.670 ;
        RECT 8.380 42.990 8.640 43.310 ;
        RECT 6.530 42.455 8.070 42.825 ;
        RECT 8.440 41.270 8.580 42.990 ;
        RECT 8.380 40.950 8.640 41.270 ;
        RECT 5.160 40.270 5.420 40.590 ;
        RECT 5.220 38.890 5.360 40.270 ;
        RECT 9.830 39.735 11.370 40.105 ;
        RECT 11.660 39.230 11.800 44.350 ;
        RECT 16.260 43.990 16.400 46.390 ;
        RECT 17.120 44.010 17.380 44.330 ;
        RECT 16.200 43.670 16.460 43.990 ;
        RECT 13.440 42.990 13.700 43.310 ;
        RECT 14.820 42.990 15.080 43.310 ;
        RECT 13.500 42.290 13.640 42.990 ;
        RECT 13.440 41.970 13.700 42.290 ;
        RECT 6.080 38.910 6.340 39.230 ;
        RECT 11.600 38.910 11.860 39.230 ;
        RECT 5.160 38.570 5.420 38.890 ;
        RECT 6.140 36.850 6.280 38.910 ;
        RECT 13.900 37.550 14.160 37.870 ;
        RECT 6.530 37.015 8.070 37.385 ;
        RECT 6.080 36.530 6.340 36.850 ;
        RECT 13.960 35.830 14.100 37.550 ;
        RECT 13.900 35.510 14.160 35.830 ;
        RECT 12.980 34.830 13.240 35.150 ;
        RECT 14.360 34.830 14.620 35.150 ;
        RECT 9.830 34.295 11.370 34.665 ;
        RECT 13.040 33.450 13.180 34.830 ;
        RECT 14.420 33.790 14.560 34.830 ;
        RECT 14.360 33.470 14.620 33.790 ;
        RECT 12.980 33.130 13.240 33.450 ;
        RECT 6.530 31.575 8.070 31.945 ;
        RECT 14.880 30.390 15.020 42.990 ;
        RECT 17.180 41.610 17.320 44.010 ;
        RECT 18.100 43.650 18.240 46.390 ;
        RECT 20.400 46.030 20.540 48.770 ;
        RECT 24.540 47.050 24.680 49.110 ;
        RECT 26.530 47.895 28.070 48.265 ;
        RECT 24.480 46.730 24.740 47.050 ;
        RECT 23.100 46.390 23.360 46.710 ;
        RECT 21.260 46.050 21.520 46.370 ;
        RECT 20.340 45.710 20.600 46.030 ;
        RECT 21.320 44.670 21.460 46.050 ;
        RECT 21.260 44.350 21.520 44.670 ;
        RECT 18.500 44.010 18.760 44.330 ;
        RECT 18.040 43.330 18.300 43.650 ;
        RECT 17.120 41.290 17.380 41.610 ;
        RECT 18.100 41.270 18.240 43.330 ;
        RECT 18.560 41.270 18.700 44.010 ;
        RECT 21.320 41.270 21.460 44.350 ;
        RECT 22.180 42.990 22.440 43.310 ;
        RECT 22.240 41.270 22.380 42.990 ;
        RECT 23.160 42.290 23.300 46.390 ;
        RECT 28.220 44.330 28.360 49.110 ;
        RECT 31.900 47.730 32.040 56.030 ;
        RECT 33.280 50.450 33.420 55.960 ;
        RECT 33.220 50.130 33.480 50.450 ;
        RECT 32.300 49.790 32.560 50.110 ;
        RECT 31.840 47.410 32.100 47.730 ;
        RECT 32.360 46.370 32.500 49.790 ;
        RECT 34.600 46.390 34.860 46.710 ;
        RECT 35.520 46.390 35.780 46.710 ;
        RECT 32.300 46.050 32.560 46.370 ;
        RECT 31.840 45.710 32.100 46.030 ;
        RECT 29.830 45.175 31.370 45.545 ;
        RECT 31.900 44.670 32.040 45.710 ;
        RECT 32.360 45.010 32.500 46.050 ;
        RECT 34.660 45.010 34.800 46.390 ;
        RECT 32.300 44.690 32.560 45.010 ;
        RECT 34.600 44.690 34.860 45.010 ;
        RECT 31.840 44.350 32.100 44.670 ;
        RECT 23.560 44.010 23.820 44.330 ;
        RECT 25.860 44.010 26.120 44.330 ;
        RECT 28.160 44.010 28.420 44.330 ;
        RECT 23.100 41.970 23.360 42.290 ;
        RECT 18.040 40.950 18.300 41.270 ;
        RECT 18.500 40.950 18.760 41.270 ;
        RECT 21.260 40.950 21.520 41.270 ;
        RECT 21.720 40.950 21.980 41.270 ;
        RECT 22.180 40.950 22.440 41.270 ;
        RECT 15.740 38.910 16.000 39.230 ;
        RECT 15.800 33.790 15.940 38.910 ;
        RECT 21.780 35.830 21.920 40.950 ;
        RECT 19.420 35.510 19.680 35.830 ;
        RECT 21.720 35.510 21.980 35.830 ;
        RECT 15.740 33.470 16.000 33.790 ;
        RECT 14.820 30.070 15.080 30.390 ;
        RECT 9.300 29.390 9.560 29.710 ;
        RECT 9.360 28.690 9.500 29.390 ;
        RECT 9.830 28.855 11.370 29.225 ;
        RECT 9.300 28.370 9.560 28.690 ;
        RECT 12.520 28.030 12.780 28.350 ;
        RECT 8.380 27.690 8.640 28.010 ;
        RECT 6.530 26.135 8.070 26.505 ;
        RECT 5.620 24.630 5.880 24.950 ;
        RECT 5.680 20.530 5.820 24.630 ;
        RECT 7.000 24.290 7.260 24.610 ;
        RECT 7.060 23.250 7.200 24.290 ;
        RECT 8.440 24.270 8.580 27.690 ;
        RECT 12.580 24.950 12.720 28.030 ;
        RECT 15.800 28.010 15.940 33.470 ;
        RECT 19.480 30.390 19.620 35.510 ;
        RECT 21.780 34.130 21.920 35.510 ;
        RECT 21.720 33.810 21.980 34.130 ;
        RECT 17.580 30.070 17.840 30.390 ;
        RECT 19.420 30.070 19.680 30.390 ;
        RECT 17.640 28.690 17.780 30.070 ;
        RECT 18.500 29.390 18.760 29.710 ;
        RECT 19.880 29.390 20.140 29.710 ;
        RECT 17.580 28.370 17.840 28.690 ;
        RECT 18.560 28.010 18.700 29.390 ;
        RECT 19.940 28.350 20.080 29.390 ;
        RECT 19.880 28.030 20.140 28.350 ;
        RECT 15.740 27.690 16.000 28.010 ;
        RECT 18.500 27.690 18.760 28.010 ;
        RECT 12.520 24.690 12.780 24.950 ;
        RECT 12.120 24.630 12.780 24.690 ;
        RECT 12.120 24.550 12.720 24.630 ;
        RECT 8.380 23.950 8.640 24.270 ;
        RECT 7.000 22.930 7.260 23.250 ;
        RECT 8.440 22.570 8.580 23.950 ;
        RECT 9.830 23.415 11.370 23.785 ;
        RECT 8.380 22.250 8.640 22.570 ;
        RECT 6.530 20.695 8.070 21.065 ;
        RECT 5.620 20.210 5.880 20.530 ;
        RECT 9.300 19.190 9.560 19.510 ;
        RECT 9.360 17.810 9.500 19.190 ;
        RECT 9.830 17.975 11.370 18.345 ;
        RECT 9.300 17.490 9.560 17.810 ;
        RECT 6.530 15.255 8.070 15.625 ;
        RECT 9.360 14.070 9.500 17.490 ;
        RECT 12.120 17.470 12.260 24.550 ;
        RECT 15.740 21.910 16.000 22.230 ;
        RECT 15.800 20.530 15.940 21.910 ;
        RECT 15.740 20.210 16.000 20.530 ;
        RECT 22.240 19.510 22.380 40.950 ;
        RECT 23.620 40.590 23.760 44.010 ;
        RECT 25.400 43.670 25.660 43.990 ;
        RECT 25.460 43.310 25.600 43.670 ;
        RECT 25.400 42.990 25.660 43.310 ;
        RECT 25.920 41.950 26.060 44.010 ;
        RECT 28.620 43.670 28.880 43.990 ;
        RECT 28.160 43.330 28.420 43.650 ;
        RECT 26.530 42.455 28.070 42.825 ;
        RECT 25.860 41.630 26.120 41.950 ;
        RECT 28.220 41.270 28.360 43.330 ;
        RECT 28.680 42.290 28.820 43.670 ;
        RECT 28.620 41.970 28.880 42.290 ;
        RECT 25.860 40.950 26.120 41.270 ;
        RECT 28.160 40.950 28.420 41.270 ;
        RECT 23.560 40.270 23.820 40.590 ;
        RECT 25.920 33.450 26.060 40.950 ;
        RECT 28.220 39.570 28.360 40.950 ;
        RECT 32.360 40.930 32.500 44.690 ;
        RECT 35.580 42.290 35.720 46.390 ;
        RECT 40.580 46.050 40.840 46.370 ;
        RECT 39.200 45.710 39.460 46.030 ;
        RECT 35.520 41.970 35.780 42.290 ;
        RECT 39.260 41.610 39.400 45.710 ;
        RECT 40.640 41.610 40.780 46.050 ;
        RECT 39.200 41.290 39.460 41.610 ;
        RECT 40.580 41.290 40.840 41.610 ;
        RECT 32.300 40.610 32.560 40.930 ;
        RECT 36.440 40.610 36.700 40.930 ;
        RECT 29.830 39.735 31.370 40.105 ;
        RECT 28.160 39.250 28.420 39.570 ;
        RECT 36.500 39.230 36.640 40.610 ;
        RECT 36.440 39.140 36.700 39.230 ;
        RECT 36.440 39.000 37.100 39.140 ;
        RECT 36.440 38.910 36.700 39.000 ;
        RECT 34.140 37.550 34.400 37.870 ;
        RECT 26.530 37.015 28.070 37.385 ;
        RECT 34.200 36.170 34.340 37.550 ;
        RECT 34.140 35.850 34.400 36.170 ;
        RECT 35.060 35.510 35.320 35.830 ;
        RECT 29.830 34.295 31.370 34.665 ;
        RECT 23.100 33.130 23.360 33.450 ;
        RECT 25.860 33.130 26.120 33.450 ;
        RECT 29.080 33.130 29.340 33.450 ;
        RECT 23.160 30.390 23.300 33.130 ;
        RECT 24.020 32.110 24.280 32.430 ;
        RECT 25.400 32.110 25.660 32.430 ;
        RECT 24.080 30.730 24.220 32.110 ;
        RECT 25.460 31.410 25.600 32.110 ;
        RECT 26.530 31.575 28.070 31.945 ;
        RECT 25.400 31.090 25.660 31.410 ;
        RECT 29.140 30.730 29.280 33.130 ;
        RECT 35.120 33.110 35.260 35.510 ;
        RECT 36.960 33.790 37.100 39.000 ;
        RECT 41.500 38.230 41.760 38.550 ;
        RECT 42.880 38.230 43.140 38.550 ;
        RECT 41.560 36.850 41.700 38.230 ;
        RECT 41.500 36.530 41.760 36.850 ;
        RECT 42.940 36.510 43.080 38.230 ;
        RECT 42.880 36.190 43.140 36.510 ;
        RECT 36.900 33.470 37.160 33.790 ;
        RECT 31.840 32.790 32.100 33.110 ;
        RECT 35.060 32.790 35.320 33.110 ;
        RECT 31.900 31.410 32.040 32.790 ;
        RECT 31.840 31.090 32.100 31.410 ;
        RECT 24.020 30.410 24.280 30.730 ;
        RECT 29.080 30.410 29.340 30.730 ;
        RECT 35.120 30.390 35.260 32.790 ;
        RECT 23.100 30.070 23.360 30.390 ;
        RECT 35.060 30.070 35.320 30.390 ;
        RECT 23.160 28.690 23.300 30.070 ;
        RECT 26.780 29.730 27.040 30.050 ;
        RECT 23.100 28.370 23.360 28.690 ;
        RECT 26.840 28.350 26.980 29.730 ;
        RECT 29.830 28.855 31.370 29.225 ;
        RECT 23.560 28.030 23.820 28.350 ;
        RECT 26.780 28.030 27.040 28.350 ;
        RECT 20.340 19.190 20.600 19.510 ;
        RECT 22.180 19.190 22.440 19.510 ;
        RECT 12.060 17.150 12.320 17.470 ;
        RECT 20.400 17.130 20.540 19.190 ;
        RECT 22.640 18.510 22.900 18.830 ;
        RECT 22.700 17.130 22.840 18.510 ;
        RECT 23.620 17.130 23.760 28.030 ;
        RECT 26.530 26.135 28.070 26.505 ;
        RECT 29.830 23.415 31.370 23.785 ;
        RECT 32.300 21.230 32.560 21.550 ;
        RECT 26.530 20.695 28.070 21.065 ;
        RECT 32.360 19.850 32.500 21.230 ;
        RECT 32.300 19.530 32.560 19.850 ;
        RECT 34.600 18.510 34.860 18.830 ;
        RECT 29.830 17.975 31.370 18.345 ;
        RECT 34.660 17.130 34.800 18.510 ;
        RECT 20.340 16.810 20.600 17.130 ;
        RECT 22.640 16.810 22.900 17.130 ;
        RECT 23.560 16.810 23.820 17.130 ;
        RECT 28.160 16.810 28.420 17.130 ;
        RECT 33.680 16.810 33.940 17.130 ;
        RECT 34.600 16.810 34.860 17.130 ;
        RECT 11.140 16.470 11.400 16.790 ;
        RECT 11.200 15.090 11.340 16.470 ;
        RECT 11.140 14.770 11.400 15.090 ;
        RECT 20.400 14.410 20.540 16.810 ;
        RECT 20.800 16.470 21.060 16.790 ;
        RECT 20.340 14.090 20.600 14.410 ;
        RECT 9.300 13.750 9.560 14.070 ;
        RECT 9.830 12.535 11.370 12.905 ;
        RECT 20.860 10.280 21.000 16.470 ;
        RECT 23.620 13.730 23.760 16.810 ;
        RECT 25.860 15.790 26.120 16.110 ;
        RECT 25.920 14.410 26.060 15.790 ;
        RECT 26.530 15.255 28.070 15.625 ;
        RECT 25.860 14.090 26.120 14.410 ;
        RECT 28.220 13.810 28.360 16.810 ;
        RECT 32.300 16.130 32.560 16.450 ;
        RECT 32.360 14.070 32.500 16.130 ;
        RECT 33.220 15.790 33.480 16.110 ;
        RECT 33.280 14.070 33.420 15.790 ;
        RECT 33.740 15.090 33.880 16.810 ;
        RECT 33.680 14.770 33.940 15.090 ;
        RECT 23.560 13.410 23.820 13.730 ;
        RECT 27.760 13.670 28.360 13.810 ;
        RECT 32.300 13.750 32.560 14.070 ;
        RECT 33.220 13.750 33.480 14.070 ;
        RECT 24.940 13.070 25.200 13.390 ;
        RECT 25.000 10.280 25.140 13.070 ;
        RECT 27.760 10.280 27.900 13.670 ;
        RECT 29.830 12.535 31.370 12.905 ;
        RECT 20.790 7.835 21.070 10.280 ;
        RECT 24.930 7.835 25.210 10.280 ;
        RECT 27.690 9.400 27.970 10.280 ;
        RECT 27.070 7.835 27.430 8.295 ;
        RECT 20.750 7.375 21.110 7.835 ;
        RECT 24.890 7.375 25.250 7.835 ;
        RECT 27.690 5.865 27.970 9.000 ;
        RECT 27.650 5.405 28.010 5.865 ;
        RECT 21.540 0.255 21.900 0.715 ;
      LAYER met3 ;
        RECT 6.510 53.355 8.090 53.685 ;
        RECT 26.510 53.355 28.090 53.685 ;
        RECT 9.810 50.635 11.390 50.965 ;
        RECT 29.810 50.635 31.390 50.965 ;
        RECT 6.510 47.915 8.090 48.245 ;
        RECT 26.510 47.915 28.090 48.245 ;
        RECT 9.810 45.195 11.390 45.525 ;
        RECT 29.810 45.195 31.390 45.525 ;
        RECT 6.510 42.475 8.090 42.805 ;
        RECT 26.510 42.475 28.090 42.805 ;
        RECT 9.810 39.755 11.390 40.085 ;
        RECT 29.810 39.755 31.390 40.085 ;
        RECT 6.510 37.035 8.090 37.365 ;
        RECT 26.510 37.035 28.090 37.365 ;
        RECT 9.810 34.315 11.390 34.645 ;
        RECT 29.810 34.315 31.390 34.645 ;
        RECT 6.510 31.595 8.090 31.925 ;
        RECT 26.510 31.595 28.090 31.925 ;
        RECT 9.810 28.875 11.390 29.205 ;
        RECT 29.810 28.875 31.390 29.205 ;
        RECT 6.510 26.155 8.090 26.485 ;
        RECT 26.510 26.155 28.090 26.485 ;
        RECT 9.810 23.435 11.390 23.765 ;
        RECT 29.810 23.435 31.390 23.765 ;
        RECT 6.510 20.715 8.090 21.045 ;
        RECT 26.510 20.715 28.090 21.045 ;
        RECT 9.810 17.995 11.390 18.325 ;
        RECT 29.810 17.995 31.390 18.325 ;
        RECT 6.510 15.275 8.090 15.605 ;
        RECT 26.510 15.275 28.090 15.605 ;
        RECT 9.810 12.555 11.390 12.885 ;
        RECT 29.810 12.555 31.390 12.885 ;
        RECT 27.070 8.315 27.430 8.415 ;
        RECT 27.000 7.815 27.500 8.315 ;
        RECT 27.070 7.715 27.430 7.815 ;
        RECT 21.540 0.665 21.900 0.835 ;
        RECT 30.350 0.665 30.850 0.735 ;
        RECT 21.540 0.305 30.850 0.665 ;
        RECT 21.540 0.135 21.900 0.305 ;
        RECT 30.350 0.235 30.850 0.305 ;
      LAYER met4 ;
        RECT 6.500 12.480 8.100 53.760 ;
        RECT 9.800 12.480 11.400 53.760 ;
        RECT 26.500 12.480 28.100 53.760 ;
        RECT 26.500 8.715 27.550 12.480 ;
        RECT 29.800 1.135 31.400 53.760 ;
  END
END reader2_unit
END LIBRARY

